VERSION 5.8 ;
BUSBITCHARS "[]" ;
DIVIDERCHAR "/" ;
UNITS
    DATABASE MICRONS 1000 ;
END UNITS

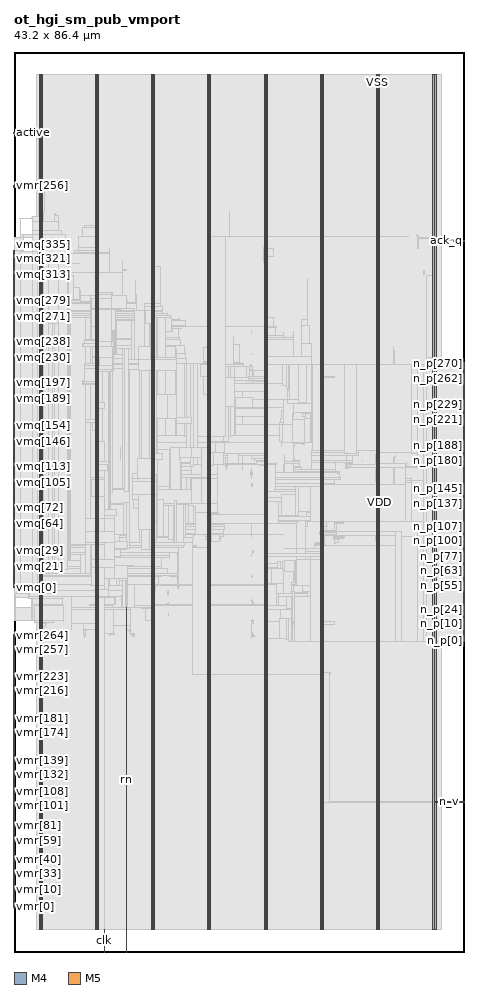
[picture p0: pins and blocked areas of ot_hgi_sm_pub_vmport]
MACRO ot_hgi_sm_pub_vmport
  FOREIGN ot_hgi_sm_pub_vmport 0 0 ;
  CLASS BLOCK ;
  SIZE 43.2 BY 86.4 ;
  PIN ack_q
    DIRECTION OUTPUT ;
    USE SIGNAL ;
    PORT
      LAYER M4 ;
        RECT  43.158 68.256 43.242 68.28 ;
    END
    PORT
      LAYER M4 ;
        RECT  42.145 68.256 43.2 68.28 ;
    END
  END ack_q
  PIN active
    DIRECTION OUTPUT ;
    USE SIGNAL ;
    PORT
      LAYER M4 ;
        RECT  -0.042 78.624 0.042 78.648 ;
    END
    PORT
      LAYER M4 ;
        RECT  0.012 78.624 2.408 78.648 ;
    END
  END active
  PIN clk
    DIRECTION INPUT ;
    USE SIGNAL ;
    PORT
      LAYER M5 ;
        RECT  8.64 -0.042 8.664 0.042 ;
    END
    PORT
      LAYER M5 ;
        RECT  8.64 0.016 8.664 2.137 ;
    END
  END clk
  PIN n_p[0]
    DIRECTION INPUT ;
    USE SIGNAL ;
    PORT
      LAYER M4 ;
        RECT  43.158 29.856 43.242 29.88 ;
    END
  END n_p[0]
  PIN n_p[100]
    DIRECTION INPUT ;
    USE SIGNAL ;
    PORT
      LAYER M4 ;
        RECT  43.158 39.456 43.242 39.48 ;
    END
  END n_p[100]
  PIN n_p[101]
    DIRECTION INPUT ;
    USE SIGNAL ;
    PORT
      LAYER M4 ;
        RECT  43.158 39.552 43.242 39.576 ;
    END
  END n_p[101]
  PIN n_p[102]
    DIRECTION INPUT ;
    USE SIGNAL ;
    PORT
      LAYER M4 ;
        RECT  43.158 39.648 43.242 39.672 ;
    END
  END n_p[102]
  PIN n_p[103]
    DIRECTION INPUT ;
    USE SIGNAL ;
    PORT
      LAYER M4 ;
        RECT  43.158 39.744 43.242 39.768 ;
    END
  END n_p[103]
  PIN n_p[104]
    DIRECTION INPUT ;
    USE SIGNAL ;
    PORT
      LAYER M4 ;
        RECT  43.158 39.84 43.242 39.864 ;
    END
  END n_p[104]
  PIN n_p[105]
    DIRECTION INPUT ;
    USE SIGNAL ;
    PORT
      LAYER M4 ;
        RECT  43.158 39.936 43.242 39.96 ;
    END
  END n_p[105]
  PIN n_p[106]
    DIRECTION INPUT ;
    USE SIGNAL ;
    PORT
      LAYER M4 ;
        RECT  43.158 40.032 43.242 40.056 ;
    END
  END n_p[106]
  PIN n_p[107]
    DIRECTION INPUT ;
    USE SIGNAL ;
    PORT
      LAYER M4 ;
        RECT  43.158 40.128 43.242 40.152 ;
    END
  END n_p[107]
  PIN n_p[108]
    DIRECTION INPUT ;
    USE SIGNAL ;
    PORT
      LAYER M4 ;
        RECT  43.158 40.224 43.242 40.248 ;
    END
  END n_p[108]
  PIN n_p[109]
    DIRECTION INPUT ;
    USE SIGNAL ;
    PORT
      LAYER M4 ;
        RECT  43.158 40.32 43.242 40.344 ;
    END
  END n_p[109]
  PIN n_p[10]
    DIRECTION INPUT ;
    USE SIGNAL ;
    PORT
      LAYER M4 ;
        RECT  43.158 30.816 43.242 30.84 ;
    END
  END n_p[10]
  PIN n_p[110]
    DIRECTION INPUT ;
    USE SIGNAL ;
    PORT
      LAYER M4 ;
        RECT  43.158 40.416 43.242 40.44 ;
    END
  END n_p[110]
  PIN n_p[111]
    DIRECTION INPUT ;
    USE SIGNAL ;
    PORT
      LAYER M4 ;
        RECT  43.158 40.512 43.242 40.536 ;
    END
  END n_p[111]
  PIN n_p[112]
    DIRECTION INPUT ;
    USE SIGNAL ;
    PORT
      LAYER M4 ;
        RECT  43.158 40.608 43.242 40.632 ;
    END
  END n_p[112]
  PIN n_p[113]
    DIRECTION INPUT ;
    USE SIGNAL ;
    PORT
      LAYER M4 ;
        RECT  43.158 40.704 43.242 40.728 ;
    END
  END n_p[113]
  PIN n_p[114]
    DIRECTION INPUT ;
    USE SIGNAL ;
    PORT
      LAYER M4 ;
        RECT  43.158 40.8 43.242 40.824 ;
    END
  END n_p[114]
  PIN n_p[115]
    DIRECTION INPUT ;
    USE SIGNAL ;
    PORT
      LAYER M4 ;
        RECT  43.158 40.896 43.242 40.92 ;
    END
  END n_p[115]
  PIN n_p[116]
    DIRECTION INPUT ;
    USE SIGNAL ;
    PORT
      LAYER M4 ;
        RECT  43.158 40.992 43.242 41.016 ;
    END
  END n_p[116]
  PIN n_p[117]
    DIRECTION INPUT ;
    USE SIGNAL ;
    PORT
      LAYER M4 ;
        RECT  43.158 41.088 43.242 41.112 ;
    END
  END n_p[117]
  PIN n_p[118]
    DIRECTION INPUT ;
    USE SIGNAL ;
    PORT
      LAYER M4 ;
        RECT  43.158 41.184 43.242 41.208 ;
    END
  END n_p[118]
  PIN n_p[119]
    DIRECTION INPUT ;
    USE SIGNAL ;
    PORT
      LAYER M4 ;
        RECT  43.158 41.28 43.242 41.304 ;
    END
  END n_p[119]
  PIN n_p[11]
    DIRECTION INPUT ;
    USE SIGNAL ;
    PORT
      LAYER M4 ;
        RECT  43.158 30.912 43.242 30.936 ;
    END
  END n_p[11]
  PIN n_p[120]
    DIRECTION INPUT ;
    USE SIGNAL ;
    PORT
      LAYER M4 ;
        RECT  43.158 41.376 43.242 41.4 ;
    END
  END n_p[120]
  PIN n_p[121]
    DIRECTION INPUT ;
    USE SIGNAL ;
    PORT
      LAYER M4 ;
        RECT  43.158 41.472 43.242 41.496 ;
    END
  END n_p[121]
  PIN n_p[122]
    DIRECTION INPUT ;
    USE SIGNAL ;
    PORT
      LAYER M4 ;
        RECT  43.158 41.568 43.242 41.592 ;
    END
  END n_p[122]
  PIN n_p[123]
    DIRECTION INPUT ;
    USE SIGNAL ;
    PORT
      LAYER M4 ;
        RECT  43.158 41.664 43.242 41.688 ;
    END
  END n_p[123]
  PIN n_p[124]
    DIRECTION INPUT ;
    USE SIGNAL ;
    PORT
      LAYER M4 ;
        RECT  43.158 41.76 43.242 41.784 ;
    END
  END n_p[124]
  PIN n_p[125]
    DIRECTION INPUT ;
    USE SIGNAL ;
    PORT
      LAYER M4 ;
        RECT  43.158 41.856 43.242 41.88 ;
    END
  END n_p[125]
  PIN n_p[126]
    DIRECTION INPUT ;
    USE SIGNAL ;
    PORT
      LAYER M4 ;
        RECT  43.158 41.952 43.242 41.976 ;
    END
  END n_p[126]
  PIN n_p[127]
    DIRECTION INPUT ;
    USE SIGNAL ;
    PORT
      LAYER M4 ;
        RECT  43.158 42.048 43.242 42.072 ;
    END
  END n_p[127]
  PIN n_p[128]
    DIRECTION INPUT ;
    USE SIGNAL ;
    PORT
      LAYER M4 ;
        RECT  43.158 42.144 43.242 42.168 ;
    END
  END n_p[128]
  PIN n_p[129]
    DIRECTION INPUT ;
    USE SIGNAL ;
    PORT
      LAYER M4 ;
        RECT  43.158 42.24 43.242 42.264 ;
    END
  END n_p[129]
  PIN n_p[12]
    DIRECTION INPUT ;
    USE SIGNAL ;
    PORT
      LAYER M4 ;
        RECT  43.158 31.008 43.242 31.032 ;
    END
  END n_p[12]
  PIN n_p[130]
    DIRECTION INPUT ;
    USE SIGNAL ;
    PORT
      LAYER M4 ;
        RECT  43.158 42.336 43.242 42.36 ;
    END
  END n_p[130]
  PIN n_p[131]
    DIRECTION INPUT ;
    USE SIGNAL ;
    PORT
      LAYER M4 ;
        RECT  43.158 42.432 43.242 42.456 ;
    END
  END n_p[131]
  PIN n_p[132]
    DIRECTION INPUT ;
    USE SIGNAL ;
    PORT
      LAYER M4 ;
        RECT  43.158 42.528 43.242 42.552 ;
    END
  END n_p[132]
  PIN n_p[133]
    DIRECTION INPUT ;
    USE SIGNAL ;
    PORT
      LAYER M4 ;
        RECT  43.158 42.624 43.242 42.648 ;
    END
  END n_p[133]
  PIN n_p[134]
    DIRECTION INPUT ;
    USE SIGNAL ;
    PORT
      LAYER M4 ;
        RECT  43.158 42.72 43.242 42.744 ;
    END
  END n_p[134]
  PIN n_p[135]
    DIRECTION INPUT ;
    USE SIGNAL ;
    PORT
      LAYER M4 ;
        RECT  43.158 42.816 43.242 42.84 ;
    END
  END n_p[135]
  PIN n_p[136]
    DIRECTION INPUT ;
    USE SIGNAL ;
    PORT
      LAYER M4 ;
        RECT  43.158 42.912 43.242 42.936 ;
    END
  END n_p[136]
  PIN n_p[137]
    DIRECTION INPUT ;
    USE SIGNAL ;
    PORT
      LAYER M4 ;
        RECT  43.158 43.008 43.242 43.032 ;
    END
  END n_p[137]
  PIN n_p[138]
    DIRECTION INPUT ;
    USE SIGNAL ;
    PORT
      LAYER M4 ;
        RECT  43.158 43.104 43.242 43.128 ;
    END
  END n_p[138]
  PIN n_p[139]
    DIRECTION INPUT ;
    USE SIGNAL ;
    PORT
      LAYER M4 ;
        RECT  43.158 43.2 43.242 43.224 ;
    END
  END n_p[139]
  PIN n_p[13]
    DIRECTION INPUT ;
    USE SIGNAL ;
    PORT
      LAYER M4 ;
        RECT  43.158 31.104 43.242 31.128 ;
    END
  END n_p[13]
  PIN n_p[140]
    DIRECTION INPUT ;
    USE SIGNAL ;
    PORT
      LAYER M4 ;
        RECT  43.158 43.296 43.242 43.32 ;
    END
  END n_p[140]
  PIN n_p[141]
    DIRECTION INPUT ;
    USE SIGNAL ;
    PORT
      LAYER M4 ;
        RECT  43.158 43.392 43.242 43.416 ;
    END
  END n_p[141]
  PIN n_p[142]
    DIRECTION INPUT ;
    USE SIGNAL ;
    PORT
      LAYER M4 ;
        RECT  43.158 43.488 43.242 43.512 ;
    END
  END n_p[142]
  PIN n_p[143]
    DIRECTION INPUT ;
    USE SIGNAL ;
    PORT
      LAYER M4 ;
        RECT  43.158 43.584 43.242 43.608 ;
    END
  END n_p[143]
  PIN n_p[144]
    DIRECTION INPUT ;
    USE SIGNAL ;
    PORT
      LAYER M4 ;
        RECT  43.158 43.68 43.242 43.704 ;
    END
  END n_p[144]
  PIN n_p[145]
    DIRECTION INPUT ;
    USE SIGNAL ;
    PORT
      LAYER M4 ;
        RECT  43.158 43.776 43.242 43.8 ;
    END
  END n_p[145]
  PIN n_p[146]
    DIRECTION INPUT ;
    USE SIGNAL ;
    PORT
      LAYER M4 ;
        RECT  43.158 43.872 43.242 43.896 ;
    END
  END n_p[146]
  PIN n_p[147]
    DIRECTION INPUT ;
    USE SIGNAL ;
    PORT
      LAYER M4 ;
        RECT  43.158 43.968 43.242 43.992 ;
    END
  END n_p[147]
  PIN n_p[148]
    DIRECTION INPUT ;
    USE SIGNAL ;
    PORT
      LAYER M4 ;
        RECT  43.158 44.064 43.242 44.088 ;
    END
  END n_p[148]
  PIN n_p[149]
    DIRECTION INPUT ;
    USE SIGNAL ;
    PORT
      LAYER M4 ;
        RECT  43.158 44.16 43.242 44.184 ;
    END
  END n_p[149]
  PIN n_p[14]
    DIRECTION INPUT ;
    USE SIGNAL ;
    PORT
      LAYER M4 ;
        RECT  43.158 31.2 43.242 31.224 ;
    END
  END n_p[14]
  PIN n_p[150]
    DIRECTION INPUT ;
    USE SIGNAL ;
    PORT
      LAYER M4 ;
        RECT  43.158 44.256 43.242 44.28 ;
    END
  END n_p[150]
  PIN n_p[151]
    DIRECTION INPUT ;
    USE SIGNAL ;
    PORT
      LAYER M4 ;
        RECT  43.158 44.352 43.242 44.376 ;
    END
  END n_p[151]
  PIN n_p[152]
    DIRECTION INPUT ;
    USE SIGNAL ;
    PORT
      LAYER M4 ;
        RECT  43.158 44.448 43.242 44.472 ;
    END
  END n_p[152]
  PIN n_p[153]
    DIRECTION INPUT ;
    USE SIGNAL ;
    PORT
      LAYER M4 ;
        RECT  43.158 44.544 43.242 44.568 ;
    END
  END n_p[153]
  PIN n_p[154]
    DIRECTION INPUT ;
    USE SIGNAL ;
    PORT
      LAYER M4 ;
        RECT  43.158 44.64 43.242 44.664 ;
    END
  END n_p[154]
  PIN n_p[155]
    DIRECTION INPUT ;
    USE SIGNAL ;
    PORT
      LAYER M4 ;
        RECT  43.158 44.736 43.242 44.76 ;
    END
  END n_p[155]
  PIN n_p[156]
    DIRECTION INPUT ;
    USE SIGNAL ;
    PORT
      LAYER M4 ;
        RECT  43.158 44.832 43.242 44.856 ;
    END
  END n_p[156]
  PIN n_p[157]
    DIRECTION INPUT ;
    USE SIGNAL ;
    PORT
      LAYER M4 ;
        RECT  43.158 44.928 43.242 44.952 ;
    END
  END n_p[157]
  PIN n_p[158]
    DIRECTION INPUT ;
    USE SIGNAL ;
    PORT
      LAYER M4 ;
        RECT  43.158 45.024 43.242 45.048 ;
    END
  END n_p[158]
  PIN n_p[159]
    DIRECTION INPUT ;
    USE SIGNAL ;
    PORT
      LAYER M4 ;
        RECT  43.158 45.12 43.242 45.144 ;
    END
  END n_p[159]
  PIN n_p[15]
    DIRECTION INPUT ;
    USE SIGNAL ;
    PORT
      LAYER M4 ;
        RECT  43.158 31.296 43.242 31.32 ;
    END
  END n_p[15]
  PIN n_p[160]
    DIRECTION INPUT ;
    USE SIGNAL ;
    PORT
      LAYER M4 ;
        RECT  43.158 45.216 43.242 45.24 ;
    END
  END n_p[160]
  PIN n_p[161]
    DIRECTION INPUT ;
    USE SIGNAL ;
    PORT
      LAYER M4 ;
        RECT  43.158 45.312 43.242 45.336 ;
    END
  END n_p[161]
  PIN n_p[162]
    DIRECTION INPUT ;
    USE SIGNAL ;
    PORT
      LAYER M4 ;
        RECT  43.158 45.408 43.242 45.432 ;
    END
  END n_p[162]
  PIN n_p[163]
    DIRECTION INPUT ;
    USE SIGNAL ;
    PORT
      LAYER M4 ;
        RECT  43.158 45.504 43.242 45.528 ;
    END
  END n_p[163]
  PIN n_p[164]
    DIRECTION INPUT ;
    USE SIGNAL ;
    PORT
      LAYER M4 ;
        RECT  43.158 45.6 43.242 45.624 ;
    END
  END n_p[164]
  PIN n_p[165]
    DIRECTION INPUT ;
    USE SIGNAL ;
    PORT
      LAYER M4 ;
        RECT  43.158 45.696 43.242 45.72 ;
    END
  END n_p[165]
  PIN n_p[166]
    DIRECTION INPUT ;
    USE SIGNAL ;
    PORT
      LAYER M4 ;
        RECT  43.158 45.792 43.242 45.816 ;
    END
  END n_p[166]
  PIN n_p[167]
    DIRECTION INPUT ;
    USE SIGNAL ;
    PORT
      LAYER M4 ;
        RECT  43.158 45.888 43.242 45.912 ;
    END
  END n_p[167]
  PIN n_p[168]
    DIRECTION INPUT ;
    USE SIGNAL ;
    PORT
      LAYER M4 ;
        RECT  43.158 45.984 43.242 46.008 ;
    END
  END n_p[168]
  PIN n_p[169]
    DIRECTION INPUT ;
    USE SIGNAL ;
    PORT
      LAYER M4 ;
        RECT  43.158 46.08 43.242 46.104 ;
    END
  END n_p[169]
  PIN n_p[16]
    DIRECTION INPUT ;
    USE SIGNAL ;
    PORT
      LAYER M4 ;
        RECT  43.158 31.392 43.242 31.416 ;
    END
  END n_p[16]
  PIN n_p[170]
    DIRECTION INPUT ;
    USE SIGNAL ;
    PORT
      LAYER M4 ;
        RECT  43.158 46.176 43.242 46.2 ;
    END
  END n_p[170]
  PIN n_p[171]
    DIRECTION INPUT ;
    USE SIGNAL ;
    PORT
      LAYER M4 ;
        RECT  43.158 46.272 43.242 46.296 ;
    END
  END n_p[171]
  PIN n_p[172]
    DIRECTION INPUT ;
    USE SIGNAL ;
    PORT
      LAYER M4 ;
        RECT  43.158 46.368 43.242 46.392 ;
    END
  END n_p[172]
  PIN n_p[173]
    DIRECTION INPUT ;
    USE SIGNAL ;
    PORT
      LAYER M4 ;
        RECT  43.158 46.464 43.242 46.488 ;
    END
  END n_p[173]
  PIN n_p[174]
    DIRECTION INPUT ;
    USE SIGNAL ;
    PORT
      LAYER M4 ;
        RECT  43.158 46.56 43.242 46.584 ;
    END
  END n_p[174]
  PIN n_p[175]
    DIRECTION INPUT ;
    USE SIGNAL ;
    PORT
      LAYER M4 ;
        RECT  43.158 46.656 43.242 46.68 ;
    END
  END n_p[175]
  PIN n_p[176]
    DIRECTION INPUT ;
    USE SIGNAL ;
    PORT
      LAYER M4 ;
        RECT  43.158 46.752 43.242 46.776 ;
    END
  END n_p[176]
  PIN n_p[177]
    DIRECTION INPUT ;
    USE SIGNAL ;
    PORT
      LAYER M4 ;
        RECT  43.158 46.848 43.242 46.872 ;
    END
  END n_p[177]
  PIN n_p[178]
    DIRECTION INPUT ;
    USE SIGNAL ;
    PORT
      LAYER M4 ;
        RECT  43.158 46.944 43.242 46.968 ;
    END
  END n_p[178]
  PIN n_p[179]
    DIRECTION INPUT ;
    USE SIGNAL ;
    PORT
      LAYER M4 ;
        RECT  43.158 47.04 43.242 47.064 ;
    END
  END n_p[179]
  PIN n_p[17]
    DIRECTION INPUT ;
    USE SIGNAL ;
    PORT
      LAYER M4 ;
        RECT  43.158 31.488 43.242 31.512 ;
    END
  END n_p[17]
  PIN n_p[180]
    DIRECTION INPUT ;
    USE SIGNAL ;
    PORT
      LAYER M4 ;
        RECT  43.158 47.136 43.242 47.16 ;
    END
  END n_p[180]
  PIN n_p[181]
    DIRECTION INPUT ;
    USE SIGNAL ;
    PORT
      LAYER M4 ;
        RECT  43.158 47.232 43.242 47.256 ;
    END
  END n_p[181]
  PIN n_p[182]
    DIRECTION INPUT ;
    USE SIGNAL ;
    PORT
      LAYER M4 ;
        RECT  43.158 47.328 43.242 47.352 ;
    END
  END n_p[182]
  PIN n_p[183]
    DIRECTION INPUT ;
    USE SIGNAL ;
    PORT
      LAYER M4 ;
        RECT  43.158 47.424 43.242 47.448 ;
    END
  END n_p[183]
  PIN n_p[184]
    DIRECTION INPUT ;
    USE SIGNAL ;
    PORT
      LAYER M4 ;
        RECT  43.158 47.52 43.242 47.544 ;
    END
  END n_p[184]
  PIN n_p[185]
    DIRECTION INPUT ;
    USE SIGNAL ;
    PORT
      LAYER M4 ;
        RECT  43.158 47.616 43.242 47.64 ;
    END
  END n_p[185]
  PIN n_p[186]
    DIRECTION INPUT ;
    USE SIGNAL ;
    PORT
      LAYER M4 ;
        RECT  43.158 47.712 43.242 47.736 ;
    END
  END n_p[186]
  PIN n_p[187]
    DIRECTION INPUT ;
    USE SIGNAL ;
    PORT
      LAYER M4 ;
        RECT  43.158 47.808 43.242 47.832 ;
    END
  END n_p[187]
  PIN n_p[188]
    DIRECTION INPUT ;
    USE SIGNAL ;
    PORT
      LAYER M4 ;
        RECT  43.158 47.904 43.242 47.928 ;
    END
  END n_p[188]
  PIN n_p[189]
    DIRECTION INPUT ;
    USE SIGNAL ;
    PORT
      LAYER M4 ;
        RECT  43.158 48 43.242 48.024 ;
    END
  END n_p[189]
  PIN n_p[18]
    DIRECTION INPUT ;
    USE SIGNAL ;
    PORT
      LAYER M4 ;
        RECT  43.158 31.584 43.242 31.608 ;
    END
  END n_p[18]
  PIN n_p[190]
    DIRECTION INPUT ;
    USE SIGNAL ;
    PORT
      LAYER M4 ;
        RECT  43.158 48.096 43.242 48.12 ;
    END
  END n_p[190]
  PIN n_p[191]
    DIRECTION INPUT ;
    USE SIGNAL ;
    PORT
      LAYER M4 ;
        RECT  43.158 48.192 43.242 48.216 ;
    END
  END n_p[191]
  PIN n_p[192]
    DIRECTION INPUT ;
    USE SIGNAL ;
    PORT
      LAYER M4 ;
        RECT  43.158 48.288 43.242 48.312 ;
    END
  END n_p[192]
  PIN n_p[193]
    DIRECTION INPUT ;
    USE SIGNAL ;
    PORT
      LAYER M4 ;
        RECT  43.158 48.384 43.242 48.408 ;
    END
  END n_p[193]
  PIN n_p[194]
    DIRECTION INPUT ;
    USE SIGNAL ;
    PORT
      LAYER M4 ;
        RECT  43.158 48.48 43.242 48.504 ;
    END
  END n_p[194]
  PIN n_p[195]
    DIRECTION INPUT ;
    USE SIGNAL ;
    PORT
      LAYER M4 ;
        RECT  43.158 48.576 43.242 48.6 ;
    END
  END n_p[195]
  PIN n_p[196]
    DIRECTION INPUT ;
    USE SIGNAL ;
    PORT
      LAYER M4 ;
        RECT  43.158 48.672 43.242 48.696 ;
    END
  END n_p[196]
  PIN n_p[197]
    DIRECTION INPUT ;
    USE SIGNAL ;
    PORT
      LAYER M4 ;
        RECT  43.158 48.768 43.242 48.792 ;
    END
  END n_p[197]
  PIN n_p[198]
    DIRECTION INPUT ;
    USE SIGNAL ;
    PORT
      LAYER M4 ;
        RECT  43.158 48.864 43.242 48.888 ;
    END
  END n_p[198]
  PIN n_p[199]
    DIRECTION INPUT ;
    USE SIGNAL ;
    PORT
      LAYER M4 ;
        RECT  43.158 48.96 43.242 48.984 ;
    END
  END n_p[199]
  PIN n_p[19]
    DIRECTION INPUT ;
    USE SIGNAL ;
    PORT
      LAYER M4 ;
        RECT  43.158 31.68 43.242 31.704 ;
    END
  END n_p[19]
  PIN n_p[1]
    DIRECTION INPUT ;
    USE SIGNAL ;
    PORT
      LAYER M4 ;
        RECT  43.158 29.952 43.242 29.976 ;
    END
  END n_p[1]
  PIN n_p[200]
    DIRECTION INPUT ;
    USE SIGNAL ;
    PORT
      LAYER M4 ;
        RECT  43.158 49.056 43.242 49.08 ;
    END
  END n_p[200]
  PIN n_p[201]
    DIRECTION INPUT ;
    USE SIGNAL ;
    PORT
      LAYER M4 ;
        RECT  43.158 49.152 43.242 49.176 ;
    END
  END n_p[201]
  PIN n_p[202]
    DIRECTION INPUT ;
    USE SIGNAL ;
    PORT
      LAYER M4 ;
        RECT  43.158 49.248 43.242 49.272 ;
    END
  END n_p[202]
  PIN n_p[203]
    DIRECTION INPUT ;
    USE SIGNAL ;
    PORT
      LAYER M4 ;
        RECT  43.158 49.344 43.242 49.368 ;
    END
  END n_p[203]
  PIN n_p[204]
    DIRECTION INPUT ;
    USE SIGNAL ;
    PORT
      LAYER M4 ;
        RECT  43.158 49.44 43.242 49.464 ;
    END
  END n_p[204]
  PIN n_p[205]
    DIRECTION INPUT ;
    USE SIGNAL ;
    PORT
      LAYER M4 ;
        RECT  43.158 49.536 43.242 49.56 ;
    END
  END n_p[205]
  PIN n_p[206]
    DIRECTION INPUT ;
    USE SIGNAL ;
    PORT
      LAYER M4 ;
        RECT  43.158 49.632 43.242 49.656 ;
    END
  END n_p[206]
  PIN n_p[207]
    DIRECTION INPUT ;
    USE SIGNAL ;
    PORT
      LAYER M4 ;
        RECT  43.158 49.728 43.242 49.752 ;
    END
  END n_p[207]
  PIN n_p[208]
    DIRECTION INPUT ;
    USE SIGNAL ;
    PORT
      LAYER M4 ;
        RECT  43.158 49.824 43.242 49.848 ;
    END
  END n_p[208]
  PIN n_p[209]
    DIRECTION INPUT ;
    USE SIGNAL ;
    PORT
      LAYER M4 ;
        RECT  43.158 49.92 43.242 49.944 ;
    END
  END n_p[209]
  PIN n_p[20]
    DIRECTION INPUT ;
    USE SIGNAL ;
    PORT
      LAYER M4 ;
        RECT  43.158 31.776 43.242 31.8 ;
    END
  END n_p[20]
  PIN n_p[210]
    DIRECTION INPUT ;
    USE SIGNAL ;
    PORT
      LAYER M4 ;
        RECT  43.158 50.016 43.242 50.04 ;
    END
  END n_p[210]
  PIN n_p[211]
    DIRECTION INPUT ;
    USE SIGNAL ;
    PORT
      LAYER M4 ;
        RECT  43.158 50.112 43.242 50.136 ;
    END
  END n_p[211]
  PIN n_p[212]
    DIRECTION INPUT ;
    USE SIGNAL ;
    PORT
      LAYER M4 ;
        RECT  43.158 50.208 43.242 50.232 ;
    END
  END n_p[212]
  PIN n_p[213]
    DIRECTION INPUT ;
    USE SIGNAL ;
    PORT
      LAYER M4 ;
        RECT  43.158 50.304 43.242 50.328 ;
    END
  END n_p[213]
  PIN n_p[214]
    DIRECTION INPUT ;
    USE SIGNAL ;
    PORT
      LAYER M4 ;
        RECT  43.158 50.4 43.242 50.424 ;
    END
  END n_p[214]
  PIN n_p[215]
    DIRECTION INPUT ;
    USE SIGNAL ;
    PORT
      LAYER M4 ;
        RECT  43.158 50.496 43.242 50.52 ;
    END
  END n_p[215]
  PIN n_p[216]
    DIRECTION INPUT ;
    USE SIGNAL ;
    PORT
      LAYER M4 ;
        RECT  43.158 50.592 43.242 50.616 ;
    END
  END n_p[216]
  PIN n_p[217]
    DIRECTION INPUT ;
    USE SIGNAL ;
    PORT
      LAYER M4 ;
        RECT  43.158 50.688 43.242 50.712 ;
    END
  END n_p[217]
  PIN n_p[218]
    DIRECTION INPUT ;
    USE SIGNAL ;
    PORT
      LAYER M4 ;
        RECT  43.158 50.784 43.242 50.808 ;
    END
  END n_p[218]
  PIN n_p[219]
    DIRECTION INPUT ;
    USE SIGNAL ;
    PORT
      LAYER M4 ;
        RECT  43.158 50.88 43.242 50.904 ;
    END
  END n_p[219]
  PIN n_p[21]
    DIRECTION INPUT ;
    USE SIGNAL ;
    PORT
      LAYER M4 ;
        RECT  43.158 31.872 43.242 31.896 ;
    END
  END n_p[21]
  PIN n_p[220]
    DIRECTION INPUT ;
    USE SIGNAL ;
    PORT
      LAYER M4 ;
        RECT  43.158 50.976 43.242 51 ;
    END
  END n_p[220]
  PIN n_p[221]
    DIRECTION INPUT ;
    USE SIGNAL ;
    PORT
      LAYER M4 ;
        RECT  43.158 51.072 43.242 51.096 ;
    END
  END n_p[221]
  PIN n_p[222]
    DIRECTION INPUT ;
    USE SIGNAL ;
    PORT
      LAYER M4 ;
        RECT  43.158 51.168 43.242 51.192 ;
    END
  END n_p[222]
  PIN n_p[223]
    DIRECTION INPUT ;
    USE SIGNAL ;
    PORT
      LAYER M4 ;
        RECT  43.158 51.264 43.242 51.288 ;
    END
  END n_p[223]
  PIN n_p[224]
    DIRECTION INPUT ;
    USE SIGNAL ;
    PORT
      LAYER M4 ;
        RECT  43.158 51.36 43.242 51.384 ;
    END
  END n_p[224]
  PIN n_p[225]
    DIRECTION INPUT ;
    USE SIGNAL ;
    PORT
      LAYER M4 ;
        RECT  43.158 51.456 43.242 51.48 ;
    END
  END n_p[225]
  PIN n_p[226]
    DIRECTION INPUT ;
    USE SIGNAL ;
    PORT
      LAYER M4 ;
        RECT  43.158 51.552 43.242 51.576 ;
    END
  END n_p[226]
  PIN n_p[227]
    DIRECTION INPUT ;
    USE SIGNAL ;
    PORT
      LAYER M4 ;
        RECT  43.158 51.648 43.242 51.672 ;
    END
  END n_p[227]
  PIN n_p[228]
    DIRECTION INPUT ;
    USE SIGNAL ;
    PORT
      LAYER M4 ;
        RECT  43.158 51.744 43.242 51.768 ;
    END
  END n_p[228]
  PIN n_p[229]
    DIRECTION INPUT ;
    USE SIGNAL ;
    PORT
      LAYER M4 ;
        RECT  43.158 51.84 43.242 51.864 ;
    END
  END n_p[229]
  PIN n_p[22]
    DIRECTION INPUT ;
    USE SIGNAL ;
    PORT
      LAYER M4 ;
        RECT  43.158 31.968 43.242 31.992 ;
    END
  END n_p[22]
  PIN n_p[230]
    DIRECTION INPUT ;
    USE SIGNAL ;
    PORT
      LAYER M4 ;
        RECT  43.158 51.936 43.242 51.96 ;
    END
  END n_p[230]
  PIN n_p[231]
    DIRECTION INPUT ;
    USE SIGNAL ;
    PORT
      LAYER M4 ;
        RECT  43.158 52.032 43.242 52.056 ;
    END
  END n_p[231]
  PIN n_p[232]
    DIRECTION INPUT ;
    USE SIGNAL ;
    PORT
      LAYER M4 ;
        RECT  43.158 52.128 43.242 52.152 ;
    END
  END n_p[232]
  PIN n_p[233]
    DIRECTION INPUT ;
    USE SIGNAL ;
    PORT
      LAYER M4 ;
        RECT  43.158 52.224 43.242 52.248 ;
    END
  END n_p[233]
  PIN n_p[234]
    DIRECTION INPUT ;
    USE SIGNAL ;
    PORT
      LAYER M4 ;
        RECT  43.158 52.32 43.242 52.344 ;
    END
  END n_p[234]
  PIN n_p[235]
    DIRECTION INPUT ;
    USE SIGNAL ;
    PORT
      LAYER M4 ;
        RECT  43.158 52.416 43.242 52.44 ;
    END
  END n_p[235]
  PIN n_p[236]
    DIRECTION INPUT ;
    USE SIGNAL ;
    PORT
      LAYER M4 ;
        RECT  43.158 52.512 43.242 52.536 ;
    END
  END n_p[236]
  PIN n_p[237]
    DIRECTION INPUT ;
    USE SIGNAL ;
    PORT
      LAYER M4 ;
        RECT  43.158 52.608 43.242 52.632 ;
    END
  END n_p[237]
  PIN n_p[238]
    DIRECTION INPUT ;
    USE SIGNAL ;
    PORT
      LAYER M4 ;
        RECT  43.158 52.704 43.242 52.728 ;
    END
  END n_p[238]
  PIN n_p[239]
    DIRECTION INPUT ;
    USE SIGNAL ;
    PORT
      LAYER M4 ;
        RECT  43.158 52.8 43.242 52.824 ;
    END
  END n_p[239]
  PIN n_p[23]
    DIRECTION INPUT ;
    USE SIGNAL ;
    PORT
      LAYER M4 ;
        RECT  43.158 32.064 43.242 32.088 ;
    END
  END n_p[23]
  PIN n_p[240]
    DIRECTION INPUT ;
    USE SIGNAL ;
    PORT
      LAYER M4 ;
        RECT  43.158 52.896 43.242 52.92 ;
    END
  END n_p[240]
  PIN n_p[241]
    DIRECTION INPUT ;
    USE SIGNAL ;
    PORT
      LAYER M4 ;
        RECT  43.158 52.992 43.242 53.016 ;
    END
  END n_p[241]
  PIN n_p[242]
    DIRECTION INPUT ;
    USE SIGNAL ;
    PORT
      LAYER M4 ;
        RECT  43.158 53.088 43.242 53.112 ;
    END
  END n_p[242]
  PIN n_p[243]
    DIRECTION INPUT ;
    USE SIGNAL ;
    PORT
      LAYER M4 ;
        RECT  43.158 53.184 43.242 53.208 ;
    END
  END n_p[243]
  PIN n_p[244]
    DIRECTION INPUT ;
    USE SIGNAL ;
    PORT
      LAYER M4 ;
        RECT  43.158 53.28 43.242 53.304 ;
    END
  END n_p[244]
  PIN n_p[245]
    DIRECTION INPUT ;
    USE SIGNAL ;
    PORT
      LAYER M4 ;
        RECT  43.158 53.376 43.242 53.4 ;
    END
  END n_p[245]
  PIN n_p[246]
    DIRECTION INPUT ;
    USE SIGNAL ;
    PORT
      LAYER M4 ;
        RECT  43.158 53.472 43.242 53.496 ;
    END
  END n_p[246]
  PIN n_p[247]
    DIRECTION INPUT ;
    USE SIGNAL ;
    PORT
      LAYER M4 ;
        RECT  43.158 53.568 43.242 53.592 ;
    END
  END n_p[247]
  PIN n_p[248]
    DIRECTION INPUT ;
    USE SIGNAL ;
    PORT
      LAYER M4 ;
        RECT  43.158 53.664 43.242 53.688 ;
    END
  END n_p[248]
  PIN n_p[249]
    DIRECTION INPUT ;
    USE SIGNAL ;
    PORT
      LAYER M4 ;
        RECT  43.158 53.76 43.242 53.784 ;
    END
  END n_p[249]
  PIN n_p[24]
    DIRECTION INPUT ;
    USE SIGNAL ;
    PORT
      LAYER M4 ;
        RECT  43.158 32.16 43.242 32.184 ;
    END
  END n_p[24]
  PIN n_p[250]
    DIRECTION INPUT ;
    USE SIGNAL ;
    PORT
      LAYER M4 ;
        RECT  43.158 53.856 43.242 53.88 ;
    END
  END n_p[250]
  PIN n_p[251]
    DIRECTION INPUT ;
    USE SIGNAL ;
    PORT
      LAYER M4 ;
        RECT  43.158 53.952 43.242 53.976 ;
    END
  END n_p[251]
  PIN n_p[252]
    DIRECTION INPUT ;
    USE SIGNAL ;
    PORT
      LAYER M4 ;
        RECT  43.158 54.048 43.242 54.072 ;
    END
  END n_p[252]
  PIN n_p[253]
    DIRECTION INPUT ;
    USE SIGNAL ;
    PORT
      LAYER M4 ;
        RECT  43.158 54.144 43.242 54.168 ;
    END
  END n_p[253]
  PIN n_p[254]
    DIRECTION INPUT ;
    USE SIGNAL ;
    PORT
      LAYER M4 ;
        RECT  43.158 54.24 43.242 54.264 ;
    END
  END n_p[254]
  PIN n_p[255]
    DIRECTION INPUT ;
    USE SIGNAL ;
    PORT
      LAYER M4 ;
        RECT  43.158 54.336 43.242 54.36 ;
    END
  END n_p[255]
  PIN n_p[256]
    DIRECTION INPUT ;
    USE SIGNAL ;
    PORT
      LAYER M4 ;
        RECT  43.158 54.432 43.242 54.456 ;
    END
  END n_p[256]
  PIN n_p[257]
    DIRECTION INPUT ;
    USE SIGNAL ;
    PORT
      LAYER M4 ;
        RECT  43.158 54.528 43.242 54.552 ;
    END
  END n_p[257]
  PIN n_p[258]
    DIRECTION INPUT ;
    USE SIGNAL ;
    PORT
      LAYER M4 ;
        RECT  43.158 54.624 43.242 54.648 ;
    END
  END n_p[258]
  PIN n_p[259]
    DIRECTION INPUT ;
    USE SIGNAL ;
    PORT
      LAYER M4 ;
        RECT  43.158 54.72 43.242 54.744 ;
    END
  END n_p[259]
  PIN n_p[25]
    DIRECTION INPUT ;
    USE SIGNAL ;
    PORT
      LAYER M4 ;
        RECT  43.158 32.256 43.242 32.28 ;
    END
  END n_p[25]
  PIN n_p[260]
    DIRECTION INPUT ;
    USE SIGNAL ;
    PORT
      LAYER M4 ;
        RECT  43.158 54.816 43.242 54.84 ;
    END
  END n_p[260]
  PIN n_p[261]
    DIRECTION INPUT ;
    USE SIGNAL ;
    PORT
      LAYER M4 ;
        RECT  43.158 54.912 43.242 54.936 ;
    END
  END n_p[261]
  PIN n_p[262]
    DIRECTION INPUT ;
    USE SIGNAL ;
    PORT
      LAYER M4 ;
        RECT  43.158 55.008 43.242 55.032 ;
    END
  END n_p[262]
  PIN n_p[263]
    DIRECTION INPUT ;
    USE SIGNAL ;
    PORT
      LAYER M4 ;
        RECT  43.158 55.104 43.242 55.128 ;
    END
  END n_p[263]
  PIN n_p[264]
    DIRECTION INPUT ;
    USE SIGNAL ;
    PORT
      LAYER M4 ;
        RECT  43.158 55.2 43.242 55.224 ;
    END
  END n_p[264]
  PIN n_p[265]
    DIRECTION INPUT ;
    USE SIGNAL ;
    PORT
      LAYER M4 ;
        RECT  43.158 55.296 43.242 55.32 ;
    END
  END n_p[265]
  PIN n_p[266]
    DIRECTION INPUT ;
    USE SIGNAL ;
    PORT
      LAYER M4 ;
        RECT  43.158 55.392 43.242 55.416 ;
    END
  END n_p[266]
  PIN n_p[267]
    DIRECTION INPUT ;
    USE SIGNAL ;
    PORT
      LAYER M4 ;
        RECT  43.158 55.488 43.242 55.512 ;
    END
  END n_p[267]
  PIN n_p[268]
    DIRECTION INPUT ;
    USE SIGNAL ;
    PORT
      LAYER M4 ;
        RECT  43.158 55.584 43.242 55.608 ;
    END
  END n_p[268]
  PIN n_p[269]
    DIRECTION INPUT ;
    USE SIGNAL ;
    PORT
      LAYER M4 ;
        RECT  43.158 55.68 43.242 55.704 ;
    END
  END n_p[269]
  PIN n_p[26]
    DIRECTION INPUT ;
    USE SIGNAL ;
    PORT
      LAYER M4 ;
        RECT  43.158 32.352 43.242 32.376 ;
    END
  END n_p[26]
  PIN n_p[270]
    DIRECTION INPUT ;
    USE SIGNAL ;
    PORT
      LAYER M4 ;
        RECT  43.158 55.776 43.242 55.8 ;
    END
  END n_p[270]
  PIN n_p[271]
    DIRECTION INPUT ;
    USE SIGNAL ;
    PORT
      LAYER M4 ;
        RECT  43.158 55.872 43.242 55.896 ;
    END
  END n_p[271]
  PIN n_p[272]
    DIRECTION INPUT ;
    USE SIGNAL ;
    PORT
      LAYER M4 ;
        RECT  43.158 55.968 43.242 55.992 ;
    END
  END n_p[272]
  PIN n_p[273]
    DIRECTION INPUT ;
    USE SIGNAL ;
    PORT
      LAYER M4 ;
        RECT  43.158 56.064 43.242 56.088 ;
    END
  END n_p[273]
  PIN n_p[274]
    DIRECTION INPUT ;
    USE SIGNAL ;
    PORT
      LAYER M4 ;
        RECT  43.158 56.16 43.242 56.184 ;
    END
  END n_p[274]
  PIN n_p[275]
    DIRECTION INPUT ;
    USE SIGNAL ;
    PORT
      LAYER M4 ;
        RECT  43.158 56.256 43.242 56.28 ;
    END
  END n_p[275]
  PIN n_p[276]
    DIRECTION INPUT ;
    USE SIGNAL ;
    PORT
      LAYER M4 ;
        RECT  43.158 56.352 43.242 56.376 ;
    END
  END n_p[276]
  PIN n_p[277]
    DIRECTION INPUT ;
    USE SIGNAL ;
    PORT
      LAYER M4 ;
        RECT  43.158 56.448 43.242 56.472 ;
    END
  END n_p[277]
  PIN n_p[278]
    DIRECTION INPUT ;
    USE SIGNAL ;
    PORT
      LAYER M4 ;
        RECT  43.158 56.544 43.242 56.568 ;
    END
  END n_p[278]
  PIN n_p[27]
    DIRECTION INPUT ;
    USE SIGNAL ;
    PORT
      LAYER M4 ;
        RECT  43.158 32.448 43.242 32.472 ;
    END
  END n_p[27]
  PIN n_p[28]
    DIRECTION INPUT ;
    USE SIGNAL ;
    PORT
      LAYER M4 ;
        RECT  43.158 32.544 43.242 32.568 ;
    END
  END n_p[28]
  PIN n_p[29]
    DIRECTION INPUT ;
    USE SIGNAL ;
    PORT
      LAYER M4 ;
        RECT  43.158 32.64 43.242 32.664 ;
    END
  END n_p[29]
  PIN n_p[2]
    DIRECTION INPUT ;
    USE SIGNAL ;
    PORT
      LAYER M4 ;
        RECT  43.158 30.048 43.242 30.072 ;
    END
  END n_p[2]
  PIN n_p[30]
    DIRECTION INPUT ;
    USE SIGNAL ;
    PORT
      LAYER M4 ;
        RECT  43.158 32.736 43.242 32.76 ;
    END
  END n_p[30]
  PIN n_p[31]
    DIRECTION INPUT ;
    USE SIGNAL ;
    PORT
      LAYER M4 ;
        RECT  43.158 32.832 43.242 32.856 ;
    END
  END n_p[31]
  PIN n_p[32]
    DIRECTION INPUT ;
    USE SIGNAL ;
    PORT
      LAYER M4 ;
        RECT  43.158 32.928 43.242 32.952 ;
    END
  END n_p[32]
  PIN n_p[33]
    DIRECTION INPUT ;
    USE SIGNAL ;
    PORT
      LAYER M4 ;
        RECT  43.158 33.024 43.242 33.048 ;
    END
  END n_p[33]
  PIN n_p[34]
    DIRECTION INPUT ;
    USE SIGNAL ;
    PORT
      LAYER M4 ;
        RECT  43.158 33.12 43.242 33.144 ;
    END
  END n_p[34]
  PIN n_p[35]
    DIRECTION INPUT ;
    USE SIGNAL ;
    PORT
      LAYER M4 ;
        RECT  43.158 33.216 43.242 33.24 ;
    END
  END n_p[35]
  PIN n_p[36]
    DIRECTION INPUT ;
    USE SIGNAL ;
    PORT
      LAYER M4 ;
        RECT  43.158 33.312 43.242 33.336 ;
    END
  END n_p[36]
  PIN n_p[37]
    DIRECTION INPUT ;
    USE SIGNAL ;
    PORT
      LAYER M4 ;
        RECT  43.158 33.408 43.242 33.432 ;
    END
  END n_p[37]
  PIN n_p[38]
    DIRECTION INPUT ;
    USE SIGNAL ;
    PORT
      LAYER M4 ;
        RECT  43.158 33.504 43.242 33.528 ;
    END
  END n_p[38]
  PIN n_p[39]
    DIRECTION INPUT ;
    USE SIGNAL ;
    PORT
      LAYER M4 ;
        RECT  43.158 33.6 43.242 33.624 ;
    END
  END n_p[39]
  PIN n_p[3]
    DIRECTION INPUT ;
    USE SIGNAL ;
    PORT
      LAYER M4 ;
        RECT  43.158 30.144 43.242 30.168 ;
    END
  END n_p[3]
  PIN n_p[40]
    DIRECTION INPUT ;
    USE SIGNAL ;
    PORT
      LAYER M4 ;
        RECT  43.158 33.696 43.242 33.72 ;
    END
  END n_p[40]
  PIN n_p[41]
    DIRECTION INPUT ;
    USE SIGNAL ;
    PORT
      LAYER M4 ;
        RECT  43.158 33.792 43.242 33.816 ;
    END
  END n_p[41]
  PIN n_p[42]
    DIRECTION INPUT ;
    USE SIGNAL ;
    PORT
      LAYER M4 ;
        RECT  43.158 33.888 43.242 33.912 ;
    END
  END n_p[42]
  PIN n_p[43]
    DIRECTION INPUT ;
    USE SIGNAL ;
    PORT
      LAYER M4 ;
        RECT  43.158 33.984 43.242 34.008 ;
    END
  END n_p[43]
  PIN n_p[44]
    DIRECTION INPUT ;
    USE SIGNAL ;
    PORT
      LAYER M4 ;
        RECT  43.158 34.08 43.242 34.104 ;
    END
  END n_p[44]
  PIN n_p[45]
    DIRECTION INPUT ;
    USE SIGNAL ;
    PORT
      LAYER M4 ;
        RECT  43.158 34.176 43.242 34.2 ;
    END
  END n_p[45]
  PIN n_p[46]
    DIRECTION INPUT ;
    USE SIGNAL ;
    PORT
      LAYER M4 ;
        RECT  43.158 34.272 43.242 34.296 ;
    END
  END n_p[46]
  PIN n_p[47]
    DIRECTION INPUT ;
    USE SIGNAL ;
    PORT
      LAYER M4 ;
        RECT  43.158 34.368 43.242 34.392 ;
    END
  END n_p[47]
  PIN n_p[48]
    DIRECTION INPUT ;
    USE SIGNAL ;
    PORT
      LAYER M4 ;
        RECT  43.158 34.464 43.242 34.488 ;
    END
  END n_p[48]
  PIN n_p[49]
    DIRECTION INPUT ;
    USE SIGNAL ;
    PORT
      LAYER M4 ;
        RECT  43.158 34.56 43.242 34.584 ;
    END
  END n_p[49]
  PIN n_p[4]
    DIRECTION INPUT ;
    USE SIGNAL ;
    PORT
      LAYER M4 ;
        RECT  43.158 30.24 43.242 30.264 ;
    END
  END n_p[4]
  PIN n_p[50]
    DIRECTION INPUT ;
    USE SIGNAL ;
    PORT
      LAYER M4 ;
        RECT  43.158 34.656 43.242 34.68 ;
    END
  END n_p[50]
  PIN n_p[51]
    DIRECTION INPUT ;
    USE SIGNAL ;
    PORT
      LAYER M4 ;
        RECT  43.158 34.752 43.242 34.776 ;
    END
  END n_p[51]
  PIN n_p[52]
    DIRECTION INPUT ;
    USE SIGNAL ;
    PORT
      LAYER M4 ;
        RECT  43.158 34.848 43.242 34.872 ;
    END
  END n_p[52]
  PIN n_p[53]
    DIRECTION INPUT ;
    USE SIGNAL ;
    PORT
      LAYER M4 ;
        RECT  43.158 34.944 43.242 34.968 ;
    END
  END n_p[53]
  PIN n_p[54]
    DIRECTION INPUT ;
    USE SIGNAL ;
    PORT
      LAYER M4 ;
        RECT  43.158 35.04 43.242 35.064 ;
    END
  END n_p[54]
  PIN n_p[55]
    DIRECTION INPUT ;
    USE SIGNAL ;
    PORT
      LAYER M4 ;
        RECT  43.158 35.136 43.242 35.16 ;
    END
  END n_p[55]
  PIN n_p[56]
    DIRECTION INPUT ;
    USE SIGNAL ;
    PORT
      LAYER M4 ;
        RECT  43.158 35.232 43.242 35.256 ;
    END
  END n_p[56]
  PIN n_p[57]
    DIRECTION INPUT ;
    USE SIGNAL ;
    PORT
      LAYER M4 ;
        RECT  43.158 35.328 43.242 35.352 ;
    END
  END n_p[57]
  PIN n_p[58]
    DIRECTION INPUT ;
    USE SIGNAL ;
    PORT
      LAYER M4 ;
        RECT  43.158 35.424 43.242 35.448 ;
    END
  END n_p[58]
  PIN n_p[59]
    DIRECTION INPUT ;
    USE SIGNAL ;
    PORT
      LAYER M4 ;
        RECT  43.158 35.52 43.242 35.544 ;
    END
  END n_p[59]
  PIN n_p[5]
    DIRECTION INPUT ;
    USE SIGNAL ;
    PORT
      LAYER M4 ;
        RECT  43.158 30.336 43.242 30.36 ;
    END
  END n_p[5]
  PIN n_p[60]
    DIRECTION INPUT ;
    USE SIGNAL ;
    PORT
      LAYER M4 ;
        RECT  43.158 35.616 43.242 35.64 ;
    END
  END n_p[60]
  PIN n_p[61]
    DIRECTION INPUT ;
    USE SIGNAL ;
    PORT
      LAYER M4 ;
        RECT  43.158 35.712 43.242 35.736 ;
    END
  END n_p[61]
  PIN n_p[62]
    DIRECTION INPUT ;
    USE SIGNAL ;
    PORT
      LAYER M4 ;
        RECT  43.158 35.808 43.242 35.832 ;
    END
  END n_p[62]
  PIN n_p[63]
    DIRECTION INPUT ;
    USE SIGNAL ;
    PORT
      LAYER M4 ;
        RECT  43.158 35.904 43.242 35.928 ;
    END
  END n_p[63]
  PIN n_p[64]
    DIRECTION INPUT ;
    USE SIGNAL ;
    PORT
      LAYER M4 ;
        RECT  43.158 36 43.242 36.024 ;
    END
  END n_p[64]
  PIN n_p[65]
    DIRECTION INPUT ;
    USE SIGNAL ;
    PORT
      LAYER M4 ;
        RECT  43.158 36.096 43.242 36.12 ;
    END
  END n_p[65]
  PIN n_p[66]
    DIRECTION INPUT ;
    USE SIGNAL ;
    PORT
      LAYER M4 ;
        RECT  43.158 36.192 43.242 36.216 ;
    END
  END n_p[66]
  PIN n_p[67]
    DIRECTION INPUT ;
    USE SIGNAL ;
    PORT
      LAYER M4 ;
        RECT  43.158 36.288 43.242 36.312 ;
    END
  END n_p[67]
  PIN n_p[68]
    DIRECTION INPUT ;
    USE SIGNAL ;
    PORT
      LAYER M4 ;
        RECT  43.158 36.384 43.242 36.408 ;
    END
  END n_p[68]
  PIN n_p[69]
    DIRECTION INPUT ;
    USE SIGNAL ;
    PORT
      LAYER M4 ;
        RECT  43.158 36.48 43.242 36.504 ;
    END
  END n_p[69]
  PIN n_p[6]
    DIRECTION INPUT ;
    USE SIGNAL ;
    PORT
      LAYER M4 ;
        RECT  43.158 30.432 43.242 30.456 ;
    END
  END n_p[6]
  PIN n_p[70]
    DIRECTION INPUT ;
    USE SIGNAL ;
    PORT
      LAYER M4 ;
        RECT  43.158 36.576 43.242 36.6 ;
    END
  END n_p[70]
  PIN n_p[71]
    DIRECTION INPUT ;
    USE SIGNAL ;
    PORT
      LAYER M4 ;
        RECT  43.158 36.672 43.242 36.696 ;
    END
  END n_p[71]
  PIN n_p[72]
    DIRECTION INPUT ;
    USE SIGNAL ;
    PORT
      LAYER M4 ;
        RECT  43.158 36.768 43.242 36.792 ;
    END
  END n_p[72]
  PIN n_p[73]
    DIRECTION INPUT ;
    USE SIGNAL ;
    PORT
      LAYER M4 ;
        RECT  43.158 36.864 43.242 36.888 ;
    END
  END n_p[73]
  PIN n_p[74]
    DIRECTION INPUT ;
    USE SIGNAL ;
    PORT
      LAYER M4 ;
        RECT  43.158 36.96 43.242 36.984 ;
    END
  END n_p[74]
  PIN n_p[75]
    DIRECTION INPUT ;
    USE SIGNAL ;
    PORT
      LAYER M4 ;
        RECT  43.158 37.056 43.242 37.08 ;
    END
  END n_p[75]
  PIN n_p[76]
    DIRECTION INPUT ;
    USE SIGNAL ;
    PORT
      LAYER M4 ;
        RECT  43.158 37.152 43.242 37.176 ;
    END
  END n_p[76]
  PIN n_p[77]
    DIRECTION INPUT ;
    USE SIGNAL ;
    PORT
      LAYER M4 ;
        RECT  43.158 37.248 43.242 37.272 ;
    END
  END n_p[77]
  PIN n_p[78]
    DIRECTION INPUT ;
    USE SIGNAL ;
    PORT
      LAYER M4 ;
        RECT  43.158 37.344 43.242 37.368 ;
    END
  END n_p[78]
  PIN n_p[79]
    DIRECTION INPUT ;
    USE SIGNAL ;
    PORT
      LAYER M4 ;
        RECT  43.158 37.44 43.242 37.464 ;
    END
  END n_p[79]
  PIN n_p[7]
    DIRECTION INPUT ;
    USE SIGNAL ;
    PORT
      LAYER M4 ;
        RECT  43.158 30.528 43.242 30.552 ;
    END
  END n_p[7]
  PIN n_p[80]
    DIRECTION INPUT ;
    USE SIGNAL ;
    PORT
      LAYER M4 ;
        RECT  43.158 37.536 43.242 37.56 ;
    END
  END n_p[80]
  PIN n_p[81]
    DIRECTION INPUT ;
    USE SIGNAL ;
    PORT
      LAYER M4 ;
        RECT  43.158 37.632 43.242 37.656 ;
    END
  END n_p[81]
  PIN n_p[82]
    DIRECTION INPUT ;
    USE SIGNAL ;
    PORT
      LAYER M4 ;
        RECT  43.158 37.728 43.242 37.752 ;
    END
  END n_p[82]
  PIN n_p[83]
    DIRECTION INPUT ;
    USE SIGNAL ;
    PORT
      LAYER M4 ;
        RECT  43.158 37.824 43.242 37.848 ;
    END
  END n_p[83]
  PIN n_p[84]
    DIRECTION INPUT ;
    USE SIGNAL ;
    PORT
      LAYER M4 ;
        RECT  43.158 37.92 43.242 37.944 ;
    END
  END n_p[84]
  PIN n_p[85]
    DIRECTION INPUT ;
    USE SIGNAL ;
    PORT
      LAYER M4 ;
        RECT  43.158 38.016 43.242 38.04 ;
    END
  END n_p[85]
  PIN n_p[86]
    DIRECTION INPUT ;
    USE SIGNAL ;
    PORT
      LAYER M4 ;
        RECT  43.158 38.112 43.242 38.136 ;
    END
  END n_p[86]
  PIN n_p[87]
    DIRECTION INPUT ;
    USE SIGNAL ;
    PORT
      LAYER M4 ;
        RECT  43.158 38.208 43.242 38.232 ;
    END
  END n_p[87]
  PIN n_p[88]
    DIRECTION INPUT ;
    USE SIGNAL ;
    PORT
      LAYER M4 ;
        RECT  43.158 38.304 43.242 38.328 ;
    END
  END n_p[88]
  PIN n_p[89]
    DIRECTION INPUT ;
    USE SIGNAL ;
    PORT
      LAYER M4 ;
        RECT  43.158 38.4 43.242 38.424 ;
    END
  END n_p[89]
  PIN n_p[8]
    DIRECTION INPUT ;
    USE SIGNAL ;
    PORT
      LAYER M4 ;
        RECT  43.158 30.624 43.242 30.648 ;
    END
  END n_p[8]
  PIN n_p[90]
    DIRECTION INPUT ;
    USE SIGNAL ;
    PORT
      LAYER M4 ;
        RECT  43.158 38.496 43.242 38.52 ;
    END
  END n_p[90]
  PIN n_p[91]
    DIRECTION INPUT ;
    USE SIGNAL ;
    PORT
      LAYER M4 ;
        RECT  43.158 38.592 43.242 38.616 ;
    END
  END n_p[91]
  PIN n_p[92]
    DIRECTION INPUT ;
    USE SIGNAL ;
    PORT
      LAYER M4 ;
        RECT  43.158 38.688 43.242 38.712 ;
    END
  END n_p[92]
  PIN n_p[93]
    DIRECTION INPUT ;
    USE SIGNAL ;
    PORT
      LAYER M4 ;
        RECT  43.158 38.784 43.242 38.808 ;
    END
  END n_p[93]
  PIN n_p[94]
    DIRECTION INPUT ;
    USE SIGNAL ;
    PORT
      LAYER M4 ;
        RECT  43.158 38.88 43.242 38.904 ;
    END
  END n_p[94]
  PIN n_p[95]
    DIRECTION INPUT ;
    USE SIGNAL ;
    PORT
      LAYER M4 ;
        RECT  43.158 38.976 43.242 39 ;
    END
  END n_p[95]
  PIN n_p[96]
    DIRECTION INPUT ;
    USE SIGNAL ;
    PORT
      LAYER M4 ;
        RECT  43.158 39.072 43.242 39.096 ;
    END
  END n_p[96]
  PIN n_p[97]
    DIRECTION INPUT ;
    USE SIGNAL ;
    PORT
      LAYER M4 ;
        RECT  43.158 39.168 43.242 39.192 ;
    END
  END n_p[97]
  PIN n_p[98]
    DIRECTION INPUT ;
    USE SIGNAL ;
    PORT
      LAYER M4 ;
        RECT  43.158 39.264 43.242 39.288 ;
    END
  END n_p[98]
  PIN n_p[99]
    DIRECTION INPUT ;
    USE SIGNAL ;
    PORT
      LAYER M4 ;
        RECT  43.158 39.36 43.242 39.384 ;
    END
  END n_p[99]
  PIN n_p[9]
    DIRECTION INPUT ;
    USE SIGNAL ;
    PORT
      LAYER M4 ;
        RECT  43.158 30.72 43.242 30.744 ;
    END
  END n_p[9]
  PIN n_v
    DIRECTION INPUT ;
    USE SIGNAL ;
    PORT
      LAYER M4 ;
        RECT  43.158 14.4 43.242 14.424 ;
    END
    PORT
      LAYER M4 ;
        RECT  40.504 14.4 43.2 14.424 ;
    END
  END n_v
  PIN rn
    DIRECTION INPUT ;
    USE SIGNAL ;
    PORT
      LAYER M5 ;
        RECT  10.8 -0.042 10.824 0.042 ;
    END
    PORT
      LAYER M5 ;
        RECT  10.8 0.016 10.824 33.107 ;
    END
  END rn
  PIN vmq[0]
    DIRECTION OUTPUT ;
    USE SIGNAL ;
    PORT
      LAYER M4 ;
        RECT  -0.042 34.992 0.042 35.016 ;
    END
  END vmq[0]
  PIN vmq[100]
    DIRECTION OUTPUT ;
    USE SIGNAL ;
    PORT
      LAYER M4 ;
        RECT  -0.042 44.592 0.042 44.616 ;
    END
  END vmq[100]
  PIN vmq[101]
    DIRECTION OUTPUT ;
    USE SIGNAL ;
    PORT
      LAYER M4 ;
        RECT  -0.042 44.688 0.042 44.712 ;
    END
  END vmq[101]
  PIN vmq[102]
    DIRECTION OUTPUT ;
    USE SIGNAL ;
    PORT
      LAYER M4 ;
        RECT  -0.042 44.784 0.042 44.808 ;
    END
  END vmq[102]
  PIN vmq[103]
    DIRECTION OUTPUT ;
    USE SIGNAL ;
    PORT
      LAYER M4 ;
        RECT  -0.042 44.88 0.042 44.904 ;
    END
  END vmq[103]
  PIN vmq[104]
    DIRECTION OUTPUT ;
    USE SIGNAL ;
    PORT
      LAYER M4 ;
        RECT  -0.042 44.976 0.042 45 ;
    END
  END vmq[104]
  PIN vmq[105]
    DIRECTION OUTPUT ;
    USE SIGNAL ;
    PORT
      LAYER M4 ;
        RECT  -0.042 45.072 0.042 45.096 ;
    END
  END vmq[105]
  PIN vmq[106]
    DIRECTION OUTPUT ;
    USE SIGNAL ;
    PORT
      LAYER M4 ;
        RECT  -0.042 45.168 0.042 45.192 ;
    END
  END vmq[106]
  PIN vmq[107]
    DIRECTION OUTPUT ;
    USE SIGNAL ;
    PORT
      LAYER M4 ;
        RECT  -0.042 45.264 0.042 45.288 ;
    END
  END vmq[107]
  PIN vmq[108]
    DIRECTION OUTPUT ;
    USE SIGNAL ;
    PORT
      LAYER M4 ;
        RECT  -0.042 45.36 0.042 45.384 ;
    END
  END vmq[108]
  PIN vmq[109]
    DIRECTION OUTPUT ;
    USE SIGNAL ;
    PORT
      LAYER M4 ;
        RECT  -0.042 45.456 0.042 45.48 ;
    END
  END vmq[109]
  PIN vmq[10]
    DIRECTION OUTPUT ;
    USE SIGNAL ;
    PORT
      LAYER M4 ;
        RECT  -0.042 35.952 0.042 35.976 ;
    END
  END vmq[10]
  PIN vmq[110]
    DIRECTION OUTPUT ;
    USE SIGNAL ;
    PORT
      LAYER M4 ;
        RECT  -0.042 45.552 0.042 45.576 ;
    END
  END vmq[110]
  PIN vmq[111]
    DIRECTION OUTPUT ;
    USE SIGNAL ;
    PORT
      LAYER M4 ;
        RECT  -0.042 45.648 0.042 45.672 ;
    END
  END vmq[111]
  PIN vmq[112]
    DIRECTION OUTPUT ;
    USE SIGNAL ;
    PORT
      LAYER M4 ;
        RECT  -0.042 45.744 0.042 45.768 ;
    END
  END vmq[112]
  PIN vmq[113]
    DIRECTION OUTPUT ;
    USE SIGNAL ;
    PORT
      LAYER M4 ;
        RECT  -0.042 45.84 0.042 45.864 ;
    END
  END vmq[113]
  PIN vmq[114]
    DIRECTION OUTPUT ;
    USE SIGNAL ;
    PORT
      LAYER M4 ;
        RECT  -0.042 45.936 0.042 45.96 ;
    END
  END vmq[114]
  PIN vmq[115]
    DIRECTION OUTPUT ;
    USE SIGNAL ;
    PORT
      LAYER M4 ;
        RECT  -0.042 46.032 0.042 46.056 ;
    END
  END vmq[115]
  PIN vmq[116]
    DIRECTION OUTPUT ;
    USE SIGNAL ;
    PORT
      LAYER M4 ;
        RECT  -0.042 46.128 0.042 46.152 ;
    END
  END vmq[116]
  PIN vmq[117]
    DIRECTION OUTPUT ;
    USE SIGNAL ;
    PORT
      LAYER M4 ;
        RECT  -0.042 46.224 0.042 46.248 ;
    END
  END vmq[117]
  PIN vmq[118]
    DIRECTION OUTPUT ;
    USE SIGNAL ;
    PORT
      LAYER M4 ;
        RECT  -0.042 46.32 0.042 46.344 ;
    END
  END vmq[118]
  PIN vmq[119]
    DIRECTION OUTPUT ;
    USE SIGNAL ;
    PORT
      LAYER M4 ;
        RECT  -0.042 46.416 0.042 46.44 ;
    END
  END vmq[119]
  PIN vmq[11]
    DIRECTION OUTPUT ;
    USE SIGNAL ;
    PORT
      LAYER M4 ;
        RECT  -0.042 36.048 0.042 36.072 ;
    END
  END vmq[11]
  PIN vmq[120]
    DIRECTION OUTPUT ;
    USE SIGNAL ;
    PORT
      LAYER M4 ;
        RECT  -0.042 46.512 0.042 46.536 ;
    END
  END vmq[120]
  PIN vmq[121]
    DIRECTION OUTPUT ;
    USE SIGNAL ;
    PORT
      LAYER M4 ;
        RECT  -0.042 46.608 0.042 46.632 ;
    END
  END vmq[121]
  PIN vmq[122]
    DIRECTION OUTPUT ;
    USE SIGNAL ;
    PORT
      LAYER M4 ;
        RECT  -0.042 46.704 0.042 46.728 ;
    END
  END vmq[122]
  PIN vmq[123]
    DIRECTION OUTPUT ;
    USE SIGNAL ;
    PORT
      LAYER M4 ;
        RECT  -0.042 46.8 0.042 46.824 ;
    END
  END vmq[123]
  PIN vmq[124]
    DIRECTION OUTPUT ;
    USE SIGNAL ;
    PORT
      LAYER M4 ;
        RECT  -0.042 46.896 0.042 46.92 ;
    END
  END vmq[124]
  PIN vmq[125]
    DIRECTION OUTPUT ;
    USE SIGNAL ;
    PORT
      LAYER M4 ;
        RECT  -0.042 46.992 0.042 47.016 ;
    END
  END vmq[125]
  PIN vmq[126]
    DIRECTION OUTPUT ;
    USE SIGNAL ;
    PORT
      LAYER M4 ;
        RECT  -0.042 47.088 0.042 47.112 ;
    END
  END vmq[126]
  PIN vmq[127]
    DIRECTION OUTPUT ;
    USE SIGNAL ;
    PORT
      LAYER M4 ;
        RECT  -0.042 47.184 0.042 47.208 ;
    END
  END vmq[127]
  PIN vmq[128]
    DIRECTION OUTPUT ;
    USE SIGNAL ;
    PORT
      LAYER M4 ;
        RECT  -0.042 47.28 0.042 47.304 ;
    END
  END vmq[128]
  PIN vmq[129]
    DIRECTION OUTPUT ;
    USE SIGNAL ;
    PORT
      LAYER M4 ;
        RECT  -0.042 47.376 0.042 47.4 ;
    END
  END vmq[129]
  PIN vmq[12]
    DIRECTION OUTPUT ;
    USE SIGNAL ;
    PORT
      LAYER M4 ;
        RECT  -0.042 36.144 0.042 36.168 ;
    END
  END vmq[12]
  PIN vmq[130]
    DIRECTION OUTPUT ;
    USE SIGNAL ;
    PORT
      LAYER M4 ;
        RECT  -0.042 47.472 0.042 47.496 ;
    END
  END vmq[130]
  PIN vmq[131]
    DIRECTION OUTPUT ;
    USE SIGNAL ;
    PORT
      LAYER M4 ;
        RECT  -0.042 47.568 0.042 47.592 ;
    END
  END vmq[131]
  PIN vmq[132]
    DIRECTION OUTPUT ;
    USE SIGNAL ;
    PORT
      LAYER M4 ;
        RECT  -0.042 47.664 0.042 47.688 ;
    END
  END vmq[132]
  PIN vmq[133]
    DIRECTION OUTPUT ;
    USE SIGNAL ;
    PORT
      LAYER M4 ;
        RECT  -0.042 47.76 0.042 47.784 ;
    END
  END vmq[133]
  PIN vmq[134]
    DIRECTION OUTPUT ;
    USE SIGNAL ;
    PORT
      LAYER M4 ;
        RECT  -0.042 47.856 0.042 47.88 ;
    END
  END vmq[134]
  PIN vmq[135]
    DIRECTION OUTPUT ;
    USE SIGNAL ;
    PORT
      LAYER M4 ;
        RECT  -0.042 47.952 0.042 47.976 ;
    END
  END vmq[135]
  PIN vmq[136]
    DIRECTION OUTPUT ;
    USE SIGNAL ;
    PORT
      LAYER M4 ;
        RECT  -0.042 48.048 0.042 48.072 ;
    END
  END vmq[136]
  PIN vmq[137]
    DIRECTION OUTPUT ;
    USE SIGNAL ;
    PORT
      LAYER M4 ;
        RECT  -0.042 48.144 0.042 48.168 ;
    END
  END vmq[137]
  PIN vmq[138]
    DIRECTION OUTPUT ;
    USE SIGNAL ;
    PORT
      LAYER M4 ;
        RECT  -0.042 48.24 0.042 48.264 ;
    END
  END vmq[138]
  PIN vmq[139]
    DIRECTION OUTPUT ;
    USE SIGNAL ;
    PORT
      LAYER M4 ;
        RECT  -0.042 48.336 0.042 48.36 ;
    END
  END vmq[139]
  PIN vmq[13]
    DIRECTION OUTPUT ;
    USE SIGNAL ;
    PORT
      LAYER M4 ;
        RECT  -0.042 36.24 0.042 36.264 ;
    END
  END vmq[13]
  PIN vmq[140]
    DIRECTION OUTPUT ;
    USE SIGNAL ;
    PORT
      LAYER M4 ;
        RECT  -0.042 48.432 0.042 48.456 ;
    END
  END vmq[140]
  PIN vmq[141]
    DIRECTION OUTPUT ;
    USE SIGNAL ;
    PORT
      LAYER M4 ;
        RECT  -0.042 48.528 0.042 48.552 ;
    END
  END vmq[141]
  PIN vmq[142]
    DIRECTION OUTPUT ;
    USE SIGNAL ;
    PORT
      LAYER M4 ;
        RECT  -0.042 48.624 0.042 48.648 ;
    END
  END vmq[142]
  PIN vmq[143]
    DIRECTION OUTPUT ;
    USE SIGNAL ;
    PORT
      LAYER M4 ;
        RECT  -0.042 48.72 0.042 48.744 ;
    END
  END vmq[143]
  PIN vmq[144]
    DIRECTION OUTPUT ;
    USE SIGNAL ;
    PORT
      LAYER M4 ;
        RECT  -0.042 48.816 0.042 48.84 ;
    END
  END vmq[144]
  PIN vmq[145]
    DIRECTION OUTPUT ;
    USE SIGNAL ;
    PORT
      LAYER M4 ;
        RECT  -0.042 48.912 0.042 48.936 ;
    END
  END vmq[145]
  PIN vmq[146]
    DIRECTION OUTPUT ;
    USE SIGNAL ;
    PORT
      LAYER M4 ;
        RECT  -0.042 49.008 0.042 49.032 ;
    END
  END vmq[146]
  PIN vmq[147]
    DIRECTION OUTPUT ;
    USE SIGNAL ;
    PORT
      LAYER M4 ;
        RECT  -0.042 49.104 0.042 49.128 ;
    END
  END vmq[147]
  PIN vmq[148]
    DIRECTION OUTPUT ;
    USE SIGNAL ;
    PORT
      LAYER M4 ;
        RECT  -0.042 49.2 0.042 49.224 ;
    END
  END vmq[148]
  PIN vmq[149]
    DIRECTION OUTPUT ;
    USE SIGNAL ;
    PORT
      LAYER M4 ;
        RECT  -0.042 49.296 0.042 49.32 ;
    END
  END vmq[149]
  PIN vmq[14]
    DIRECTION OUTPUT ;
    USE SIGNAL ;
    PORT
      LAYER M4 ;
        RECT  -0.042 36.336 0.042 36.36 ;
    END
  END vmq[14]
  PIN vmq[150]
    DIRECTION OUTPUT ;
    USE SIGNAL ;
    PORT
      LAYER M4 ;
        RECT  -0.042 49.392 0.042 49.416 ;
    END
  END vmq[150]
  PIN vmq[151]
    DIRECTION OUTPUT ;
    USE SIGNAL ;
    PORT
      LAYER M4 ;
        RECT  -0.042 49.488 0.042 49.512 ;
    END
  END vmq[151]
  PIN vmq[152]
    DIRECTION OUTPUT ;
    USE SIGNAL ;
    PORT
      LAYER M4 ;
        RECT  -0.042 49.584 0.042 49.608 ;
    END
  END vmq[152]
  PIN vmq[153]
    DIRECTION OUTPUT ;
    USE SIGNAL ;
    PORT
      LAYER M4 ;
        RECT  -0.042 49.68 0.042 49.704 ;
    END
  END vmq[153]
  PIN vmq[154]
    DIRECTION OUTPUT ;
    USE SIGNAL ;
    PORT
      LAYER M4 ;
        RECT  -0.042 49.776 0.042 49.8 ;
    END
  END vmq[154]
  PIN vmq[155]
    DIRECTION OUTPUT ;
    USE SIGNAL ;
    PORT
      LAYER M4 ;
        RECT  -0.042 49.872 0.042 49.896 ;
    END
  END vmq[155]
  PIN vmq[156]
    DIRECTION OUTPUT ;
    USE SIGNAL ;
    PORT
      LAYER M4 ;
        RECT  -0.042 49.968 0.042 49.992 ;
    END
  END vmq[156]
  PIN vmq[157]
    DIRECTION OUTPUT ;
    USE SIGNAL ;
    PORT
      LAYER M4 ;
        RECT  -0.042 50.064 0.042 50.088 ;
    END
  END vmq[157]
  PIN vmq[158]
    DIRECTION OUTPUT ;
    USE SIGNAL ;
    PORT
      LAYER M4 ;
        RECT  -0.042 50.16 0.042 50.184 ;
    END
  END vmq[158]
  PIN vmq[159]
    DIRECTION OUTPUT ;
    USE SIGNAL ;
    PORT
      LAYER M4 ;
        RECT  -0.042 50.256 0.042 50.28 ;
    END
  END vmq[159]
  PIN vmq[15]
    DIRECTION OUTPUT ;
    USE SIGNAL ;
    PORT
      LAYER M4 ;
        RECT  -0.042 36.432 0.042 36.456 ;
    END
  END vmq[15]
  PIN vmq[160]
    DIRECTION OUTPUT ;
    USE SIGNAL ;
    PORT
      LAYER M4 ;
        RECT  -0.042 50.352 0.042 50.376 ;
    END
  END vmq[160]
  PIN vmq[161]
    DIRECTION OUTPUT ;
    USE SIGNAL ;
    PORT
      LAYER M4 ;
        RECT  -0.042 50.448 0.042 50.472 ;
    END
  END vmq[161]
  PIN vmq[162]
    DIRECTION OUTPUT ;
    USE SIGNAL ;
    PORT
      LAYER M4 ;
        RECT  -0.042 50.544 0.042 50.568 ;
    END
  END vmq[162]
  PIN vmq[163]
    DIRECTION OUTPUT ;
    USE SIGNAL ;
    PORT
      LAYER M4 ;
        RECT  -0.042 50.64 0.042 50.664 ;
    END
  END vmq[163]
  PIN vmq[164]
    DIRECTION OUTPUT ;
    USE SIGNAL ;
    PORT
      LAYER M4 ;
        RECT  -0.042 50.736 0.042 50.76 ;
    END
  END vmq[164]
  PIN vmq[165]
    DIRECTION OUTPUT ;
    USE SIGNAL ;
    PORT
      LAYER M4 ;
        RECT  -0.042 50.832 0.042 50.856 ;
    END
  END vmq[165]
  PIN vmq[166]
    DIRECTION OUTPUT ;
    USE SIGNAL ;
    PORT
      LAYER M4 ;
        RECT  -0.042 50.928 0.042 50.952 ;
    END
  END vmq[166]
  PIN vmq[167]
    DIRECTION OUTPUT ;
    USE SIGNAL ;
    PORT
      LAYER M4 ;
        RECT  -0.042 51.024 0.042 51.048 ;
    END
  END vmq[167]
  PIN vmq[168]
    DIRECTION OUTPUT ;
    USE SIGNAL ;
    PORT
      LAYER M4 ;
        RECT  -0.042 51.12 0.042 51.144 ;
    END
  END vmq[168]
  PIN vmq[169]
    DIRECTION OUTPUT ;
    USE SIGNAL ;
    PORT
      LAYER M4 ;
        RECT  -0.042 51.216 0.042 51.24 ;
    END
  END vmq[169]
  PIN vmq[16]
    DIRECTION OUTPUT ;
    USE SIGNAL ;
    PORT
      LAYER M4 ;
        RECT  -0.042 36.528 0.042 36.552 ;
    END
  END vmq[16]
  PIN vmq[170]
    DIRECTION OUTPUT ;
    USE SIGNAL ;
    PORT
      LAYER M4 ;
        RECT  -0.042 51.312 0.042 51.336 ;
    END
  END vmq[170]
  PIN vmq[171]
    DIRECTION OUTPUT ;
    USE SIGNAL ;
    PORT
      LAYER M4 ;
        RECT  -0.042 51.408 0.042 51.432 ;
    END
  END vmq[171]
  PIN vmq[172]
    DIRECTION OUTPUT ;
    USE SIGNAL ;
    PORT
      LAYER M4 ;
        RECT  -0.042 51.504 0.042 51.528 ;
    END
  END vmq[172]
  PIN vmq[173]
    DIRECTION OUTPUT ;
    USE SIGNAL ;
    PORT
      LAYER M4 ;
        RECT  -0.042 51.6 0.042 51.624 ;
    END
  END vmq[173]
  PIN vmq[174]
    DIRECTION OUTPUT ;
    USE SIGNAL ;
    PORT
      LAYER M4 ;
        RECT  -0.042 51.696 0.042 51.72 ;
    END
  END vmq[174]
  PIN vmq[175]
    DIRECTION OUTPUT ;
    USE SIGNAL ;
    PORT
      LAYER M4 ;
        RECT  -0.042 51.792 0.042 51.816 ;
    END
  END vmq[175]
  PIN vmq[176]
    DIRECTION OUTPUT ;
    USE SIGNAL ;
    PORT
      LAYER M4 ;
        RECT  -0.042 51.888 0.042 51.912 ;
    END
  END vmq[176]
  PIN vmq[177]
    DIRECTION OUTPUT ;
    USE SIGNAL ;
    PORT
      LAYER M4 ;
        RECT  -0.042 51.984 0.042 52.008 ;
    END
  END vmq[177]
  PIN vmq[178]
    DIRECTION OUTPUT ;
    USE SIGNAL ;
    PORT
      LAYER M4 ;
        RECT  -0.042 52.08 0.042 52.104 ;
    END
  END vmq[178]
  PIN vmq[179]
    DIRECTION OUTPUT ;
    USE SIGNAL ;
    PORT
      LAYER M4 ;
        RECT  -0.042 52.176 0.042 52.2 ;
    END
  END vmq[179]
  PIN vmq[17]
    DIRECTION OUTPUT ;
    USE SIGNAL ;
    PORT
      LAYER M4 ;
        RECT  -0.042 36.624 0.042 36.648 ;
    END
  END vmq[17]
  PIN vmq[180]
    DIRECTION OUTPUT ;
    USE SIGNAL ;
    PORT
      LAYER M4 ;
        RECT  -0.042 52.272 0.042 52.296 ;
    END
  END vmq[180]
  PIN vmq[181]
    DIRECTION OUTPUT ;
    USE SIGNAL ;
    PORT
      LAYER M4 ;
        RECT  -0.042 52.368 0.042 52.392 ;
    END
  END vmq[181]
  PIN vmq[182]
    DIRECTION OUTPUT ;
    USE SIGNAL ;
    PORT
      LAYER M4 ;
        RECT  -0.042 52.464 0.042 52.488 ;
    END
  END vmq[182]
  PIN vmq[183]
    DIRECTION OUTPUT ;
    USE SIGNAL ;
    PORT
      LAYER M4 ;
        RECT  -0.042 52.56 0.042 52.584 ;
    END
  END vmq[183]
  PIN vmq[184]
    DIRECTION OUTPUT ;
    USE SIGNAL ;
    PORT
      LAYER M4 ;
        RECT  -0.042 52.656 0.042 52.68 ;
    END
  END vmq[184]
  PIN vmq[185]
    DIRECTION OUTPUT ;
    USE SIGNAL ;
    PORT
      LAYER M4 ;
        RECT  -0.042 52.752 0.042 52.776 ;
    END
  END vmq[185]
  PIN vmq[186]
    DIRECTION OUTPUT ;
    USE SIGNAL ;
    PORT
      LAYER M4 ;
        RECT  -0.042 52.848 0.042 52.872 ;
    END
  END vmq[186]
  PIN vmq[187]
    DIRECTION OUTPUT ;
    USE SIGNAL ;
    PORT
      LAYER M4 ;
        RECT  -0.042 52.944 0.042 52.968 ;
    END
  END vmq[187]
  PIN vmq[188]
    DIRECTION OUTPUT ;
    USE SIGNAL ;
    PORT
      LAYER M4 ;
        RECT  -0.042 53.04 0.042 53.064 ;
    END
  END vmq[188]
  PIN vmq[189]
    DIRECTION OUTPUT ;
    USE SIGNAL ;
    PORT
      LAYER M4 ;
        RECT  -0.042 53.136 0.042 53.16 ;
    END
  END vmq[189]
  PIN vmq[18]
    DIRECTION OUTPUT ;
    USE SIGNAL ;
    PORT
      LAYER M4 ;
        RECT  -0.042 36.72 0.042 36.744 ;
    END
  END vmq[18]
  PIN vmq[190]
    DIRECTION OUTPUT ;
    USE SIGNAL ;
    PORT
      LAYER M4 ;
        RECT  -0.042 53.232 0.042 53.256 ;
    END
  END vmq[190]
  PIN vmq[191]
    DIRECTION OUTPUT ;
    USE SIGNAL ;
    PORT
      LAYER M4 ;
        RECT  -0.042 53.328 0.042 53.352 ;
    END
  END vmq[191]
  PIN vmq[192]
    DIRECTION OUTPUT ;
    USE SIGNAL ;
    PORT
      LAYER M4 ;
        RECT  -0.042 53.424 0.042 53.448 ;
    END
  END vmq[192]
  PIN vmq[193]
    DIRECTION OUTPUT ;
    USE SIGNAL ;
    PORT
      LAYER M4 ;
        RECT  -0.042 53.52 0.042 53.544 ;
    END
  END vmq[193]
  PIN vmq[194]
    DIRECTION OUTPUT ;
    USE SIGNAL ;
    PORT
      LAYER M4 ;
        RECT  -0.042 53.616 0.042 53.64 ;
    END
  END vmq[194]
  PIN vmq[195]
    DIRECTION OUTPUT ;
    USE SIGNAL ;
    PORT
      LAYER M4 ;
        RECT  -0.042 53.712 0.042 53.736 ;
    END
  END vmq[195]
  PIN vmq[196]
    DIRECTION OUTPUT ;
    USE SIGNAL ;
    PORT
      LAYER M4 ;
        RECT  -0.042 53.808 0.042 53.832 ;
    END
  END vmq[196]
  PIN vmq[197]
    DIRECTION OUTPUT ;
    USE SIGNAL ;
    PORT
      LAYER M4 ;
        RECT  -0.042 53.904 0.042 53.928 ;
    END
  END vmq[197]
  PIN vmq[198]
    DIRECTION OUTPUT ;
    USE SIGNAL ;
    PORT
      LAYER M4 ;
        RECT  -0.042 54 0.042 54.024 ;
    END
  END vmq[198]
  PIN vmq[199]
    DIRECTION OUTPUT ;
    USE SIGNAL ;
    PORT
      LAYER M4 ;
        RECT  -0.042 54.096 0.042 54.12 ;
    END
  END vmq[199]
  PIN vmq[19]
    DIRECTION OUTPUT ;
    USE SIGNAL ;
    PORT
      LAYER M4 ;
        RECT  -0.042 36.816 0.042 36.84 ;
    END
  END vmq[19]
  PIN vmq[1]
    DIRECTION OUTPUT ;
    USE SIGNAL ;
    PORT
      LAYER M4 ;
        RECT  -0.042 35.088 0.042 35.112 ;
    END
  END vmq[1]
  PIN vmq[200]
    DIRECTION OUTPUT ;
    USE SIGNAL ;
    PORT
      LAYER M4 ;
        RECT  -0.042 54.192 0.042 54.216 ;
    END
  END vmq[200]
  PIN vmq[201]
    DIRECTION OUTPUT ;
    USE SIGNAL ;
    PORT
      LAYER M4 ;
        RECT  -0.042 54.288 0.042 54.312 ;
    END
  END vmq[201]
  PIN vmq[202]
    DIRECTION OUTPUT ;
    USE SIGNAL ;
    PORT
      LAYER M4 ;
        RECT  -0.042 54.384 0.042 54.408 ;
    END
  END vmq[202]
  PIN vmq[203]
    DIRECTION OUTPUT ;
    USE SIGNAL ;
    PORT
      LAYER M4 ;
        RECT  -0.042 54.48 0.042 54.504 ;
    END
  END vmq[203]
  PIN vmq[204]
    DIRECTION OUTPUT ;
    USE SIGNAL ;
    PORT
      LAYER M4 ;
        RECT  -0.042 54.576 0.042 54.6 ;
    END
  END vmq[204]
  PIN vmq[205]
    DIRECTION OUTPUT ;
    USE SIGNAL ;
    PORT
      LAYER M4 ;
        RECT  -0.042 54.672 0.042 54.696 ;
    END
  END vmq[205]
  PIN vmq[206]
    DIRECTION OUTPUT ;
    USE SIGNAL ;
    PORT
      LAYER M4 ;
        RECT  -0.042 54.768 0.042 54.792 ;
    END
  END vmq[206]
  PIN vmq[207]
    DIRECTION OUTPUT ;
    USE SIGNAL ;
    PORT
      LAYER M4 ;
        RECT  -0.042 54.864 0.042 54.888 ;
    END
  END vmq[207]
  PIN vmq[208]
    DIRECTION OUTPUT ;
    USE SIGNAL ;
    PORT
      LAYER M4 ;
        RECT  -0.042 54.96 0.042 54.984 ;
    END
  END vmq[208]
  PIN vmq[209]
    DIRECTION OUTPUT ;
    USE SIGNAL ;
    PORT
      LAYER M4 ;
        RECT  -0.042 55.056 0.042 55.08 ;
    END
  END vmq[209]
  PIN vmq[20]
    DIRECTION OUTPUT ;
    USE SIGNAL ;
    PORT
      LAYER M4 ;
        RECT  -0.042 36.912 0.042 36.936 ;
    END
  END vmq[20]
  PIN vmq[210]
    DIRECTION OUTPUT ;
    USE SIGNAL ;
    PORT
      LAYER M4 ;
        RECT  -0.042 55.152 0.042 55.176 ;
    END
  END vmq[210]
  PIN vmq[211]
    DIRECTION OUTPUT ;
    USE SIGNAL ;
    PORT
      LAYER M4 ;
        RECT  -0.042 55.248 0.042 55.272 ;
    END
  END vmq[211]
  PIN vmq[212]
    DIRECTION OUTPUT ;
    USE SIGNAL ;
    PORT
      LAYER M4 ;
        RECT  -0.042 55.344 0.042 55.368 ;
    END
  END vmq[212]
  PIN vmq[213]
    DIRECTION OUTPUT ;
    USE SIGNAL ;
    PORT
      LAYER M4 ;
        RECT  -0.042 55.44 0.042 55.464 ;
    END
  END vmq[213]
  PIN vmq[214]
    DIRECTION OUTPUT ;
    USE SIGNAL ;
    PORT
      LAYER M4 ;
        RECT  -0.042 55.536 0.042 55.56 ;
    END
  END vmq[214]
  PIN vmq[215]
    DIRECTION OUTPUT ;
    USE SIGNAL ;
    PORT
      LAYER M4 ;
        RECT  -0.042 55.632 0.042 55.656 ;
    END
  END vmq[215]
  PIN vmq[216]
    DIRECTION OUTPUT ;
    USE SIGNAL ;
    PORT
      LAYER M4 ;
        RECT  -0.042 55.728 0.042 55.752 ;
    END
  END vmq[216]
  PIN vmq[217]
    DIRECTION OUTPUT ;
    USE SIGNAL ;
    PORT
      LAYER M4 ;
        RECT  -0.042 55.824 0.042 55.848 ;
    END
  END vmq[217]
  PIN vmq[218]
    DIRECTION OUTPUT ;
    USE SIGNAL ;
    PORT
      LAYER M4 ;
        RECT  -0.042 55.92 0.042 55.944 ;
    END
  END vmq[218]
  PIN vmq[219]
    DIRECTION OUTPUT ;
    USE SIGNAL ;
    PORT
      LAYER M4 ;
        RECT  -0.042 56.016 0.042 56.04 ;
    END
  END vmq[219]
  PIN vmq[21]
    DIRECTION OUTPUT ;
    USE SIGNAL ;
    PORT
      LAYER M4 ;
        RECT  -0.042 37.008 0.042 37.032 ;
    END
  END vmq[21]
  PIN vmq[220]
    DIRECTION OUTPUT ;
    USE SIGNAL ;
    PORT
      LAYER M4 ;
        RECT  -0.042 56.112 0.042 56.136 ;
    END
  END vmq[220]
  PIN vmq[221]
    DIRECTION OUTPUT ;
    USE SIGNAL ;
    PORT
      LAYER M4 ;
        RECT  -0.042 56.208 0.042 56.232 ;
    END
  END vmq[221]
  PIN vmq[222]
    DIRECTION OUTPUT ;
    USE SIGNAL ;
    PORT
      LAYER M4 ;
        RECT  -0.042 56.304 0.042 56.328 ;
    END
  END vmq[222]
  PIN vmq[223]
    DIRECTION OUTPUT ;
    USE SIGNAL ;
    PORT
      LAYER M4 ;
        RECT  -0.042 56.4 0.042 56.424 ;
    END
  END vmq[223]
  PIN vmq[224]
    DIRECTION OUTPUT ;
    USE SIGNAL ;
    PORT
      LAYER M4 ;
        RECT  -0.042 56.496 0.042 56.52 ;
    END
  END vmq[224]
  PIN vmq[225]
    DIRECTION OUTPUT ;
    USE SIGNAL ;
    PORT
      LAYER M4 ;
        RECT  -0.042 56.592 0.042 56.616 ;
    END
  END vmq[225]
  PIN vmq[226]
    DIRECTION OUTPUT ;
    USE SIGNAL ;
    PORT
      LAYER M4 ;
        RECT  -0.042 56.688 0.042 56.712 ;
    END
  END vmq[226]
  PIN vmq[227]
    DIRECTION OUTPUT ;
    USE SIGNAL ;
    PORT
      LAYER M4 ;
        RECT  -0.042 56.784 0.042 56.808 ;
    END
  END vmq[227]
  PIN vmq[228]
    DIRECTION OUTPUT ;
    USE SIGNAL ;
    PORT
      LAYER M4 ;
        RECT  -0.042 56.88 0.042 56.904 ;
    END
  END vmq[228]
  PIN vmq[229]
    DIRECTION OUTPUT ;
    USE SIGNAL ;
    PORT
      LAYER M4 ;
        RECT  -0.042 56.976 0.042 57 ;
    END
  END vmq[229]
  PIN vmq[22]
    DIRECTION OUTPUT ;
    USE SIGNAL ;
    PORT
      LAYER M4 ;
        RECT  -0.042 37.104 0.042 37.128 ;
    END
  END vmq[22]
  PIN vmq[230]
    DIRECTION OUTPUT ;
    USE SIGNAL ;
    PORT
      LAYER M4 ;
        RECT  -0.042 57.072 0.042 57.096 ;
    END
  END vmq[230]
  PIN vmq[231]
    DIRECTION OUTPUT ;
    USE SIGNAL ;
    PORT
      LAYER M4 ;
        RECT  -0.042 57.168 0.042 57.192 ;
    END
  END vmq[231]
  PIN vmq[232]
    DIRECTION OUTPUT ;
    USE SIGNAL ;
    PORT
      LAYER M4 ;
        RECT  -0.042 57.264 0.042 57.288 ;
    END
  END vmq[232]
  PIN vmq[233]
    DIRECTION OUTPUT ;
    USE SIGNAL ;
    PORT
      LAYER M4 ;
        RECT  -0.042 57.36 0.042 57.384 ;
    END
  END vmq[233]
  PIN vmq[234]
    DIRECTION OUTPUT ;
    USE SIGNAL ;
    PORT
      LAYER M4 ;
        RECT  -0.042 57.456 0.042 57.48 ;
    END
  END vmq[234]
  PIN vmq[235]
    DIRECTION OUTPUT ;
    USE SIGNAL ;
    PORT
      LAYER M4 ;
        RECT  -0.042 57.552 0.042 57.576 ;
    END
  END vmq[235]
  PIN vmq[236]
    DIRECTION OUTPUT ;
    USE SIGNAL ;
    PORT
      LAYER M4 ;
        RECT  -0.042 57.648 0.042 57.672 ;
    END
  END vmq[236]
  PIN vmq[237]
    DIRECTION OUTPUT ;
    USE SIGNAL ;
    PORT
      LAYER M4 ;
        RECT  -0.042 57.744 0.042 57.768 ;
    END
  END vmq[237]
  PIN vmq[238]
    DIRECTION OUTPUT ;
    USE SIGNAL ;
    PORT
      LAYER M4 ;
        RECT  -0.042 57.84 0.042 57.864 ;
    END
  END vmq[238]
  PIN vmq[239]
    DIRECTION OUTPUT ;
    USE SIGNAL ;
    PORT
      LAYER M4 ;
        RECT  -0.042 57.936 0.042 57.96 ;
    END
  END vmq[239]
  PIN vmq[23]
    DIRECTION OUTPUT ;
    USE SIGNAL ;
    PORT
      LAYER M4 ;
        RECT  -0.042 37.2 0.042 37.224 ;
    END
  END vmq[23]
  PIN vmq[240]
    DIRECTION OUTPUT ;
    USE SIGNAL ;
    PORT
      LAYER M4 ;
        RECT  -0.042 58.032 0.042 58.056 ;
    END
  END vmq[240]
  PIN vmq[241]
    DIRECTION OUTPUT ;
    USE SIGNAL ;
    PORT
      LAYER M4 ;
        RECT  -0.042 58.128 0.042 58.152 ;
    END
  END vmq[241]
  PIN vmq[242]
    DIRECTION OUTPUT ;
    USE SIGNAL ;
    PORT
      LAYER M4 ;
        RECT  -0.042 58.224 0.042 58.248 ;
    END
  END vmq[242]
  PIN vmq[243]
    DIRECTION OUTPUT ;
    USE SIGNAL ;
    PORT
      LAYER M4 ;
        RECT  -0.042 58.32 0.042 58.344 ;
    END
  END vmq[243]
  PIN vmq[244]
    DIRECTION OUTPUT ;
    USE SIGNAL ;
    PORT
      LAYER M4 ;
        RECT  -0.042 58.416 0.042 58.44 ;
    END
  END vmq[244]
  PIN vmq[245]
    DIRECTION OUTPUT ;
    USE SIGNAL ;
    PORT
      LAYER M4 ;
        RECT  -0.042 58.512 0.042 58.536 ;
    END
  END vmq[245]
  PIN vmq[246]
    DIRECTION OUTPUT ;
    USE SIGNAL ;
    PORT
      LAYER M4 ;
        RECT  -0.042 58.608 0.042 58.632 ;
    END
  END vmq[246]
  PIN vmq[247]
    DIRECTION OUTPUT ;
    USE SIGNAL ;
    PORT
      LAYER M4 ;
        RECT  -0.042 58.704 0.042 58.728 ;
    END
  END vmq[247]
  PIN vmq[248]
    DIRECTION OUTPUT ;
    USE SIGNAL ;
    PORT
      LAYER M4 ;
        RECT  -0.042 58.8 0.042 58.824 ;
    END
  END vmq[248]
  PIN vmq[249]
    DIRECTION OUTPUT ;
    USE SIGNAL ;
    PORT
      LAYER M4 ;
        RECT  -0.042 58.896 0.042 58.92 ;
    END
  END vmq[249]
  PIN vmq[24]
    DIRECTION OUTPUT ;
    USE SIGNAL ;
    PORT
      LAYER M4 ;
        RECT  -0.042 37.296 0.042 37.32 ;
    END
  END vmq[24]
  PIN vmq[250]
    DIRECTION OUTPUT ;
    USE SIGNAL ;
    PORT
      LAYER M4 ;
        RECT  -0.042 58.992 0.042 59.016 ;
    END
  END vmq[250]
  PIN vmq[251]
    DIRECTION OUTPUT ;
    USE SIGNAL ;
    PORT
      LAYER M4 ;
        RECT  -0.042 59.088 0.042 59.112 ;
    END
  END vmq[251]
  PIN vmq[252]
    DIRECTION OUTPUT ;
    USE SIGNAL ;
    PORT
      LAYER M4 ;
        RECT  -0.042 59.184 0.042 59.208 ;
    END
  END vmq[252]
  PIN vmq[253]
    DIRECTION OUTPUT ;
    USE SIGNAL ;
    PORT
      LAYER M4 ;
        RECT  -0.042 59.28 0.042 59.304 ;
    END
  END vmq[253]
  PIN vmq[254]
    DIRECTION OUTPUT ;
    USE SIGNAL ;
    PORT
      LAYER M4 ;
        RECT  -0.042 59.376 0.042 59.4 ;
    END
  END vmq[254]
  PIN vmq[255]
    DIRECTION OUTPUT ;
    USE SIGNAL ;
    PORT
      LAYER M4 ;
        RECT  -0.042 59.472 0.042 59.496 ;
    END
  END vmq[255]
  PIN vmq[256]
    DIRECTION OUTPUT ;
    USE SIGNAL ;
    PORT
      LAYER M4 ;
        RECT  -0.042 59.568 0.042 59.592 ;
    END
  END vmq[256]
  PIN vmq[257]
    DIRECTION OUTPUT ;
    USE SIGNAL ;
    PORT
      LAYER M4 ;
        RECT  -0.042 59.664 0.042 59.688 ;
    END
  END vmq[257]
  PIN vmq[258]
    DIRECTION OUTPUT ;
    USE SIGNAL ;
    PORT
      LAYER M4 ;
        RECT  -0.042 59.76 0.042 59.784 ;
    END
  END vmq[258]
  PIN vmq[259]
    DIRECTION OUTPUT ;
    USE SIGNAL ;
    PORT
      LAYER M4 ;
        RECT  -0.042 59.856 0.042 59.88 ;
    END
  END vmq[259]
  PIN vmq[25]
    DIRECTION OUTPUT ;
    USE SIGNAL ;
    PORT
      LAYER M4 ;
        RECT  -0.042 37.392 0.042 37.416 ;
    END
  END vmq[25]
  PIN vmq[260]
    DIRECTION OUTPUT ;
    USE SIGNAL ;
    PORT
      LAYER M4 ;
        RECT  -0.042 59.952 0.042 59.976 ;
    END
  END vmq[260]
  PIN vmq[261]
    DIRECTION OUTPUT ;
    USE SIGNAL ;
    PORT
      LAYER M4 ;
        RECT  -0.042 60.048 0.042 60.072 ;
    END
  END vmq[261]
  PIN vmq[262]
    DIRECTION OUTPUT ;
    USE SIGNAL ;
    PORT
      LAYER M4 ;
        RECT  -0.042 60.144 0.042 60.168 ;
    END
  END vmq[262]
  PIN vmq[263]
    DIRECTION OUTPUT ;
    USE SIGNAL ;
    PORT
      LAYER M4 ;
        RECT  -0.042 60.24 0.042 60.264 ;
    END
  END vmq[263]
  PIN vmq[264]
    DIRECTION OUTPUT ;
    USE SIGNAL ;
    PORT
      LAYER M4 ;
        RECT  -0.042 60.336 0.042 60.36 ;
    END
  END vmq[264]
  PIN vmq[265]
    DIRECTION OUTPUT ;
    USE SIGNAL ;
    PORT
      LAYER M4 ;
        RECT  -0.042 60.432 0.042 60.456 ;
    END
  END vmq[265]
  PIN vmq[266]
    DIRECTION OUTPUT ;
    USE SIGNAL ;
    PORT
      LAYER M4 ;
        RECT  -0.042 60.528 0.042 60.552 ;
    END
  END vmq[266]
  PIN vmq[267]
    DIRECTION OUTPUT ;
    USE SIGNAL ;
    PORT
      LAYER M4 ;
        RECT  -0.042 60.624 0.042 60.648 ;
    END
  END vmq[267]
  PIN vmq[268]
    DIRECTION OUTPUT ;
    USE SIGNAL ;
    PORT
      LAYER M4 ;
        RECT  -0.042 60.72 0.042 60.744 ;
    END
  END vmq[268]
  PIN vmq[269]
    DIRECTION OUTPUT ;
    USE SIGNAL ;
    PORT
      LAYER M4 ;
        RECT  -0.042 60.816 0.042 60.84 ;
    END
  END vmq[269]
  PIN vmq[26]
    DIRECTION OUTPUT ;
    USE SIGNAL ;
    PORT
      LAYER M4 ;
        RECT  -0.042 37.488 0.042 37.512 ;
    END
  END vmq[26]
  PIN vmq[270]
    DIRECTION OUTPUT ;
    USE SIGNAL ;
    PORT
      LAYER M4 ;
        RECT  -0.042 60.912 0.042 60.936 ;
    END
  END vmq[270]
  PIN vmq[271]
    DIRECTION OUTPUT ;
    USE SIGNAL ;
    PORT
      LAYER M4 ;
        RECT  -0.042 61.008 0.042 61.032 ;
    END
  END vmq[271]
  PIN vmq[272]
    DIRECTION OUTPUT ;
    USE SIGNAL ;
    PORT
      LAYER M4 ;
        RECT  -0.042 61.104 0.042 61.128 ;
    END
  END vmq[272]
  PIN vmq[273]
    DIRECTION OUTPUT ;
    USE SIGNAL ;
    PORT
      LAYER M4 ;
        RECT  -0.042 61.2 0.042 61.224 ;
    END
  END vmq[273]
  PIN vmq[274]
    DIRECTION OUTPUT ;
    USE SIGNAL ;
    PORT
      LAYER M4 ;
        RECT  -0.042 61.296 0.042 61.32 ;
    END
  END vmq[274]
  PIN vmq[275]
    DIRECTION OUTPUT ;
    USE SIGNAL ;
    PORT
      LAYER M4 ;
        RECT  -0.042 61.392 0.042 61.416 ;
    END
  END vmq[275]
  PIN vmq[276]
    DIRECTION OUTPUT ;
    USE SIGNAL ;
    PORT
      LAYER M4 ;
        RECT  -0.042 61.488 0.042 61.512 ;
    END
  END vmq[276]
  PIN vmq[277]
    DIRECTION OUTPUT ;
    USE SIGNAL ;
    PORT
      LAYER M4 ;
        RECT  -0.042 61.584 0.042 61.608 ;
    END
  END vmq[277]
  PIN vmq[278]
    DIRECTION OUTPUT ;
    USE SIGNAL ;
    PORT
      LAYER M4 ;
        RECT  -0.042 61.68 0.042 61.704 ;
    END
  END vmq[278]
  PIN vmq[279]
    DIRECTION OUTPUT ;
    USE SIGNAL ;
    PORT
      LAYER M4 ;
        RECT  -0.042 61.776 0.042 61.8 ;
    END
  END vmq[279]
  PIN vmq[27]
    DIRECTION OUTPUT ;
    USE SIGNAL ;
    PORT
      LAYER M4 ;
        RECT  -0.042 37.584 0.042 37.608 ;
    END
  END vmq[27]
  PIN vmq[280]
    DIRECTION OUTPUT ;
    USE SIGNAL ;
    PORT
      LAYER M4 ;
        RECT  -0.042 61.872 0.042 61.896 ;
    END
  END vmq[280]
  PIN vmq[281]
    DIRECTION OUTPUT ;
    USE SIGNAL ;
    PORT
      LAYER M4 ;
        RECT  -0.042 61.968 0.042 61.992 ;
    END
  END vmq[281]
  PIN vmq[282]
    DIRECTION OUTPUT ;
    USE SIGNAL ;
    PORT
      LAYER M4 ;
        RECT  -0.042 62.064 0.042 62.088 ;
    END
  END vmq[282]
  PIN vmq[283]
    DIRECTION OUTPUT ;
    USE SIGNAL ;
    PORT
      LAYER M4 ;
        RECT  -0.042 62.16 0.042 62.184 ;
    END
  END vmq[283]
  PIN vmq[284]
    DIRECTION OUTPUT ;
    USE SIGNAL ;
    PORT
      LAYER M4 ;
        RECT  -0.042 62.256 0.042 62.28 ;
    END
  END vmq[284]
  PIN vmq[285]
    DIRECTION OUTPUT ;
    USE SIGNAL ;
    PORT
      LAYER M4 ;
        RECT  -0.042 62.352 0.042 62.376 ;
    END
  END vmq[285]
  PIN vmq[286]
    DIRECTION OUTPUT ;
    USE SIGNAL ;
    PORT
      LAYER M4 ;
        RECT  -0.042 62.448 0.042 62.472 ;
    END
  END vmq[286]
  PIN vmq[287]
    DIRECTION OUTPUT ;
    USE SIGNAL ;
    PORT
      LAYER M4 ;
        RECT  -0.042 62.544 0.042 62.568 ;
    END
  END vmq[287]
  PIN vmq[288]
    DIRECTION OUTPUT ;
    USE SIGNAL ;
    PORT
      LAYER M4 ;
        RECT  -0.042 62.64 0.042 62.664 ;
    END
  END vmq[288]
  PIN vmq[289]
    DIRECTION OUTPUT ;
    USE SIGNAL ;
    PORT
      LAYER M4 ;
        RECT  -0.042 62.736 0.042 62.76 ;
    END
  END vmq[289]
  PIN vmq[28]
    DIRECTION OUTPUT ;
    USE SIGNAL ;
    PORT
      LAYER M4 ;
        RECT  -0.042 37.68 0.042 37.704 ;
    END
  END vmq[28]
  PIN vmq[290]
    DIRECTION OUTPUT ;
    USE SIGNAL ;
    PORT
      LAYER M4 ;
        RECT  -0.042 62.832 0.042 62.856 ;
    END
  END vmq[290]
  PIN vmq[291]
    DIRECTION OUTPUT ;
    USE SIGNAL ;
    PORT
      LAYER M4 ;
        RECT  -0.042 62.928 0.042 62.952 ;
    END
  END vmq[291]
  PIN vmq[292]
    DIRECTION OUTPUT ;
    USE SIGNAL ;
    PORT
      LAYER M4 ;
        RECT  -0.042 63.024 0.042 63.048 ;
    END
  END vmq[292]
  PIN vmq[293]
    DIRECTION OUTPUT ;
    USE SIGNAL ;
    PORT
      LAYER M4 ;
        RECT  -0.042 63.12 0.042 63.144 ;
    END
  END vmq[293]
  PIN vmq[294]
    DIRECTION OUTPUT ;
    USE SIGNAL ;
    PORT
      LAYER M4 ;
        RECT  -0.042 63.216 0.042 63.24 ;
    END
  END vmq[294]
  PIN vmq[295]
    DIRECTION OUTPUT ;
    USE SIGNAL ;
    PORT
      LAYER M4 ;
        RECT  -0.042 63.312 0.042 63.336 ;
    END
  END vmq[295]
  PIN vmq[296]
    DIRECTION OUTPUT ;
    USE SIGNAL ;
    PORT
      LAYER M4 ;
        RECT  -0.042 63.408 0.042 63.432 ;
    END
  END vmq[296]
  PIN vmq[297]
    DIRECTION OUTPUT ;
    USE SIGNAL ;
    PORT
      LAYER M4 ;
        RECT  -0.042 63.504 0.042 63.528 ;
    END
  END vmq[297]
  PIN vmq[298]
    DIRECTION OUTPUT ;
    USE SIGNAL ;
    PORT
      LAYER M4 ;
        RECT  -0.042 63.6 0.042 63.624 ;
    END
  END vmq[298]
  PIN vmq[299]
    DIRECTION OUTPUT ;
    USE SIGNAL ;
    PORT
      LAYER M4 ;
        RECT  -0.042 63.696 0.042 63.72 ;
    END
  END vmq[299]
  PIN vmq[29]
    DIRECTION OUTPUT ;
    USE SIGNAL ;
    PORT
      LAYER M4 ;
        RECT  -0.042 37.776 0.042 37.8 ;
    END
  END vmq[29]
  PIN vmq[2]
    DIRECTION OUTPUT ;
    USE SIGNAL ;
    PORT
      LAYER M4 ;
        RECT  -0.042 35.184 0.042 35.208 ;
    END
  END vmq[2]
  PIN vmq[300]
    DIRECTION OUTPUT ;
    USE SIGNAL ;
    PORT
      LAYER M4 ;
        RECT  -0.042 63.792 0.042 63.816 ;
    END
  END vmq[300]
  PIN vmq[301]
    DIRECTION OUTPUT ;
    USE SIGNAL ;
    PORT
      LAYER M4 ;
        RECT  -0.042 63.888 0.042 63.912 ;
    END
  END vmq[301]
  PIN vmq[302]
    DIRECTION OUTPUT ;
    USE SIGNAL ;
    PORT
      LAYER M4 ;
        RECT  -0.042 63.984 0.042 64.008 ;
    END
  END vmq[302]
  PIN vmq[303]
    DIRECTION OUTPUT ;
    USE SIGNAL ;
    PORT
      LAYER M4 ;
        RECT  -0.042 64.08 0.042 64.104 ;
    END
  END vmq[303]
  PIN vmq[304]
    DIRECTION OUTPUT ;
    USE SIGNAL ;
    PORT
      LAYER M4 ;
        RECT  -0.042 64.176 0.042 64.2 ;
    END
  END vmq[304]
  PIN vmq[305]
    DIRECTION OUTPUT ;
    USE SIGNAL ;
    PORT
      LAYER M4 ;
        RECT  -0.042 64.272 0.042 64.296 ;
    END
  END vmq[305]
  PIN vmq[306]
    DIRECTION OUTPUT ;
    USE SIGNAL ;
    PORT
      LAYER M4 ;
        RECT  -0.042 64.368 0.042 64.392 ;
    END
  END vmq[306]
  PIN vmq[307]
    DIRECTION OUTPUT ;
    USE SIGNAL ;
    PORT
      LAYER M4 ;
        RECT  -0.042 64.464 0.042 64.488 ;
    END
  END vmq[307]
  PIN vmq[308]
    DIRECTION OUTPUT ;
    USE SIGNAL ;
    PORT
      LAYER M4 ;
        RECT  -0.042 64.56 0.042 64.584 ;
    END
  END vmq[308]
  PIN vmq[309]
    DIRECTION OUTPUT ;
    USE SIGNAL ;
    PORT
      LAYER M4 ;
        RECT  -0.042 64.656 0.042 64.68 ;
    END
  END vmq[309]
  PIN vmq[30]
    DIRECTION OUTPUT ;
    USE SIGNAL ;
    PORT
      LAYER M4 ;
        RECT  -0.042 37.872 0.042 37.896 ;
    END
  END vmq[30]
  PIN vmq[310]
    DIRECTION OUTPUT ;
    USE SIGNAL ;
    PORT
      LAYER M4 ;
        RECT  -0.042 64.752 0.042 64.776 ;
    END
  END vmq[310]
  PIN vmq[311]
    DIRECTION OUTPUT ;
    USE SIGNAL ;
    PORT
      LAYER M4 ;
        RECT  -0.042 64.848 0.042 64.872 ;
    END
  END vmq[311]
  PIN vmq[312]
    DIRECTION OUTPUT ;
    USE SIGNAL ;
    PORT
      LAYER M4 ;
        RECT  -0.042 64.944 0.042 64.968 ;
    END
  END vmq[312]
  PIN vmq[313]
    DIRECTION OUTPUT ;
    USE SIGNAL ;
    PORT
      LAYER M4 ;
        RECT  -0.042 65.04 0.042 65.064 ;
    END
  END vmq[313]
  PIN vmq[314]
    DIRECTION OUTPUT ;
    USE SIGNAL ;
    PORT
      LAYER M4 ;
        RECT  -0.042 65.136 0.042 65.16 ;
    END
  END vmq[314]
  PIN vmq[315]
    DIRECTION OUTPUT ;
    USE SIGNAL ;
    PORT
      LAYER M4 ;
        RECT  -0.042 65.232 0.042 65.256 ;
    END
  END vmq[315]
  PIN vmq[316]
    DIRECTION OUTPUT ;
    USE SIGNAL ;
    PORT
      LAYER M4 ;
        RECT  -0.042 65.328 0.042 65.352 ;
    END
  END vmq[316]
  PIN vmq[317]
    DIRECTION OUTPUT ;
    USE SIGNAL ;
    PORT
      LAYER M4 ;
        RECT  -0.042 65.424 0.042 65.448 ;
    END
  END vmq[317]
  PIN vmq[318]
    DIRECTION OUTPUT ;
    USE SIGNAL ;
    PORT
      LAYER M4 ;
        RECT  -0.042 65.52 0.042 65.544 ;
    END
  END vmq[318]
  PIN vmq[319]
    DIRECTION OUTPUT ;
    USE SIGNAL ;
    PORT
      LAYER M4 ;
        RECT  -0.042 65.616 0.042 65.64 ;
    END
  END vmq[319]
  PIN vmq[31]
    DIRECTION OUTPUT ;
    USE SIGNAL ;
    PORT
      LAYER M4 ;
        RECT  -0.042 37.968 0.042 37.992 ;
    END
  END vmq[31]
  PIN vmq[320]
    DIRECTION OUTPUT ;
    USE SIGNAL ;
    PORT
      LAYER M4 ;
        RECT  -0.042 65.712 0.042 65.736 ;
    END
  END vmq[320]
  PIN vmq[321]
    DIRECTION OUTPUT ;
    USE SIGNAL ;
    PORT
      LAYER M4 ;
        RECT  -0.042 65.808 0.042 65.832 ;
    END
  END vmq[321]
  PIN vmq[322]
    DIRECTION OUTPUT ;
    USE SIGNAL ;
    PORT
      LAYER M4 ;
        RECT  -0.042 65.904 0.042 65.928 ;
    END
  END vmq[322]
  PIN vmq[323]
    DIRECTION OUTPUT ;
    USE SIGNAL ;
    PORT
      LAYER M4 ;
        RECT  -0.042 66 0.042 66.024 ;
    END
  END vmq[323]
  PIN vmq[324]
    DIRECTION OUTPUT ;
    USE SIGNAL ;
    PORT
      LAYER M4 ;
        RECT  -0.042 66.096 0.042 66.12 ;
    END
  END vmq[324]
  PIN vmq[325]
    DIRECTION OUTPUT ;
    USE SIGNAL ;
    PORT
      LAYER M4 ;
        RECT  -0.042 66.192 0.042 66.216 ;
    END
  END vmq[325]
  PIN vmq[326]
    DIRECTION OUTPUT ;
    USE SIGNAL ;
    PORT
      LAYER M4 ;
        RECT  -0.042 66.288 0.042 66.312 ;
    END
  END vmq[326]
  PIN vmq[327]
    DIRECTION OUTPUT ;
    USE SIGNAL ;
    PORT
      LAYER M4 ;
        RECT  -0.042 66.384 0.042 66.408 ;
    END
  END vmq[327]
  PIN vmq[328]
    DIRECTION OUTPUT ;
    USE SIGNAL ;
    PORT
      LAYER M4 ;
        RECT  -0.042 66.48 0.042 66.504 ;
    END
  END vmq[328]
  PIN vmq[329]
    DIRECTION OUTPUT ;
    USE SIGNAL ;
    PORT
      LAYER M4 ;
        RECT  -0.042 66.576 0.042 66.6 ;
    END
  END vmq[329]
  PIN vmq[32]
    DIRECTION OUTPUT ;
    USE SIGNAL ;
    PORT
      LAYER M4 ;
        RECT  -0.042 38.064 0.042 38.088 ;
    END
  END vmq[32]
  PIN vmq[330]
    DIRECTION OUTPUT ;
    USE SIGNAL ;
    PORT
      LAYER M4 ;
        RECT  -0.042 66.672 0.042 66.696 ;
    END
  END vmq[330]
  PIN vmq[331]
    DIRECTION OUTPUT ;
    USE SIGNAL ;
    PORT
      LAYER M4 ;
        RECT  -0.042 66.768 0.042 66.792 ;
    END
  END vmq[331]
  PIN vmq[332]
    DIRECTION OUTPUT ;
    USE SIGNAL ;
    PORT
      LAYER M4 ;
        RECT  -0.042 66.864 0.042 66.888 ;
    END
  END vmq[332]
  PIN vmq[333]
    DIRECTION OUTPUT ;
    USE SIGNAL ;
    PORT
      LAYER M4 ;
        RECT  -0.042 66.96 0.042 66.984 ;
    END
  END vmq[333]
  PIN vmq[334]
    DIRECTION OUTPUT ;
    USE SIGNAL ;
    PORT
      LAYER M4 ;
        RECT  -0.042 67.056 0.042 67.08 ;
    END
  END vmq[334]
  PIN vmq[335]
    DIRECTION OUTPUT ;
    USE SIGNAL ;
    PORT
      LAYER M4 ;
        RECT  -0.042 67.152 0.042 67.176 ;
    END
  END vmq[335]
  PIN vmq[336]
    DIRECTION OUTPUT ;
    USE SIGNAL ;
    PORT
      LAYER M4 ;
        RECT  -0.042 67.248 0.042 67.272 ;
    END
  END vmq[336]
  PIN vmq[337]
    DIRECTION OUTPUT ;
    USE SIGNAL ;
    PORT
      LAYER M4 ;
        RECT  -0.042 67.344 0.042 67.368 ;
    END
  END vmq[337]
  PIN vmq[33]
    DIRECTION OUTPUT ;
    USE SIGNAL ;
    PORT
      LAYER M4 ;
        RECT  -0.042 38.16 0.042 38.184 ;
    END
  END vmq[33]
  PIN vmq[34]
    DIRECTION OUTPUT ;
    USE SIGNAL ;
    PORT
      LAYER M4 ;
        RECT  -0.042 38.256 0.042 38.28 ;
    END
  END vmq[34]
  PIN vmq[35]
    DIRECTION OUTPUT ;
    USE SIGNAL ;
    PORT
      LAYER M4 ;
        RECT  -0.042 38.352 0.042 38.376 ;
    END
  END vmq[35]
  PIN vmq[36]
    DIRECTION OUTPUT ;
    USE SIGNAL ;
    PORT
      LAYER M4 ;
        RECT  -0.042 38.448 0.042 38.472 ;
    END
  END vmq[36]
  PIN vmq[37]
    DIRECTION OUTPUT ;
    USE SIGNAL ;
    PORT
      LAYER M4 ;
        RECT  -0.042 38.544 0.042 38.568 ;
    END
  END vmq[37]
  PIN vmq[38]
    DIRECTION OUTPUT ;
    USE SIGNAL ;
    PORT
      LAYER M4 ;
        RECT  -0.042 38.64 0.042 38.664 ;
    END
  END vmq[38]
  PIN vmq[39]
    DIRECTION OUTPUT ;
    USE SIGNAL ;
    PORT
      LAYER M4 ;
        RECT  -0.042 38.736 0.042 38.76 ;
    END
  END vmq[39]
  PIN vmq[3]
    DIRECTION OUTPUT ;
    USE SIGNAL ;
    PORT
      LAYER M4 ;
        RECT  -0.042 35.28 0.042 35.304 ;
    END
  END vmq[3]
  PIN vmq[40]
    DIRECTION OUTPUT ;
    USE SIGNAL ;
    PORT
      LAYER M4 ;
        RECT  -0.042 38.832 0.042 38.856 ;
    END
  END vmq[40]
  PIN vmq[41]
    DIRECTION OUTPUT ;
    USE SIGNAL ;
    PORT
      LAYER M4 ;
        RECT  -0.042 38.928 0.042 38.952 ;
    END
  END vmq[41]
  PIN vmq[42]
    DIRECTION OUTPUT ;
    USE SIGNAL ;
    PORT
      LAYER M4 ;
        RECT  -0.042 39.024 0.042 39.048 ;
    END
  END vmq[42]
  PIN vmq[43]
    DIRECTION OUTPUT ;
    USE SIGNAL ;
    PORT
      LAYER M4 ;
        RECT  -0.042 39.12 0.042 39.144 ;
    END
  END vmq[43]
  PIN vmq[44]
    DIRECTION OUTPUT ;
    USE SIGNAL ;
    PORT
      LAYER M4 ;
        RECT  -0.042 39.216 0.042 39.24 ;
    END
  END vmq[44]
  PIN vmq[45]
    DIRECTION OUTPUT ;
    USE SIGNAL ;
    PORT
      LAYER M4 ;
        RECT  -0.042 39.312 0.042 39.336 ;
    END
  END vmq[45]
  PIN vmq[46]
    DIRECTION OUTPUT ;
    USE SIGNAL ;
    PORT
      LAYER M4 ;
        RECT  -0.042 39.408 0.042 39.432 ;
    END
  END vmq[46]
  PIN vmq[47]
    DIRECTION OUTPUT ;
    USE SIGNAL ;
    PORT
      LAYER M4 ;
        RECT  -0.042 39.504 0.042 39.528 ;
    END
  END vmq[47]
  PIN vmq[48]
    DIRECTION OUTPUT ;
    USE SIGNAL ;
    PORT
      LAYER M4 ;
        RECT  -0.042 39.6 0.042 39.624 ;
    END
  END vmq[48]
  PIN vmq[49]
    DIRECTION OUTPUT ;
    USE SIGNAL ;
    PORT
      LAYER M4 ;
        RECT  -0.042 39.696 0.042 39.72 ;
    END
  END vmq[49]
  PIN vmq[4]
    DIRECTION OUTPUT ;
    USE SIGNAL ;
    PORT
      LAYER M4 ;
        RECT  -0.042 35.376 0.042 35.4 ;
    END
  END vmq[4]
  PIN vmq[50]
    DIRECTION OUTPUT ;
    USE SIGNAL ;
    PORT
      LAYER M4 ;
        RECT  -0.042 39.792 0.042 39.816 ;
    END
  END vmq[50]
  PIN vmq[51]
    DIRECTION OUTPUT ;
    USE SIGNAL ;
    PORT
      LAYER M4 ;
        RECT  -0.042 39.888 0.042 39.912 ;
    END
  END vmq[51]
  PIN vmq[52]
    DIRECTION OUTPUT ;
    USE SIGNAL ;
    PORT
      LAYER M4 ;
        RECT  -0.042 39.984 0.042 40.008 ;
    END
  END vmq[52]
  PIN vmq[53]
    DIRECTION OUTPUT ;
    USE SIGNAL ;
    PORT
      LAYER M4 ;
        RECT  -0.042 40.08 0.042 40.104 ;
    END
  END vmq[53]
  PIN vmq[54]
    DIRECTION OUTPUT ;
    USE SIGNAL ;
    PORT
      LAYER M4 ;
        RECT  -0.042 40.176 0.042 40.2 ;
    END
  END vmq[54]
  PIN vmq[55]
    DIRECTION OUTPUT ;
    USE SIGNAL ;
    PORT
      LAYER M4 ;
        RECT  -0.042 40.272 0.042 40.296 ;
    END
  END vmq[55]
  PIN vmq[56]
    DIRECTION OUTPUT ;
    USE SIGNAL ;
    PORT
      LAYER M4 ;
        RECT  -0.042 40.368 0.042 40.392 ;
    END
  END vmq[56]
  PIN vmq[57]
    DIRECTION OUTPUT ;
    USE SIGNAL ;
    PORT
      LAYER M4 ;
        RECT  -0.042 40.464 0.042 40.488 ;
    END
  END vmq[57]
  PIN vmq[58]
    DIRECTION OUTPUT ;
    USE SIGNAL ;
    PORT
      LAYER M4 ;
        RECT  -0.042 40.56 0.042 40.584 ;
    END
  END vmq[58]
  PIN vmq[59]
    DIRECTION OUTPUT ;
    USE SIGNAL ;
    PORT
      LAYER M4 ;
        RECT  -0.042 40.656 0.042 40.68 ;
    END
  END vmq[59]
  PIN vmq[5]
    DIRECTION OUTPUT ;
    USE SIGNAL ;
    PORT
      LAYER M4 ;
        RECT  -0.042 35.472 0.042 35.496 ;
    END
  END vmq[5]
  PIN vmq[60]
    DIRECTION OUTPUT ;
    USE SIGNAL ;
    PORT
      LAYER M4 ;
        RECT  -0.042 40.752 0.042 40.776 ;
    END
  END vmq[60]
  PIN vmq[61]
    DIRECTION OUTPUT ;
    USE SIGNAL ;
    PORT
      LAYER M4 ;
        RECT  -0.042 40.848 0.042 40.872 ;
    END
  END vmq[61]
  PIN vmq[62]
    DIRECTION OUTPUT ;
    USE SIGNAL ;
    PORT
      LAYER M4 ;
        RECT  -0.042 40.944 0.042 40.968 ;
    END
  END vmq[62]
  PIN vmq[63]
    DIRECTION OUTPUT ;
    USE SIGNAL ;
    PORT
      LAYER M4 ;
        RECT  -0.042 41.04 0.042 41.064 ;
    END
  END vmq[63]
  PIN vmq[64]
    DIRECTION OUTPUT ;
    USE SIGNAL ;
    PORT
      LAYER M4 ;
        RECT  -0.042 41.136 0.042 41.16 ;
    END
  END vmq[64]
  PIN vmq[65]
    DIRECTION OUTPUT ;
    USE SIGNAL ;
    PORT
      LAYER M4 ;
        RECT  -0.042 41.232 0.042 41.256 ;
    END
  END vmq[65]
  PIN vmq[66]
    DIRECTION OUTPUT ;
    USE SIGNAL ;
    PORT
      LAYER M4 ;
        RECT  -0.042 41.328 0.042 41.352 ;
    END
  END vmq[66]
  PIN vmq[67]
    DIRECTION OUTPUT ;
    USE SIGNAL ;
    PORT
      LAYER M4 ;
        RECT  -0.042 41.424 0.042 41.448 ;
    END
  END vmq[67]
  PIN vmq[68]
    DIRECTION OUTPUT ;
    USE SIGNAL ;
    PORT
      LAYER M4 ;
        RECT  -0.042 41.52 0.042 41.544 ;
    END
  END vmq[68]
  PIN vmq[69]
    DIRECTION OUTPUT ;
    USE SIGNAL ;
    PORT
      LAYER M4 ;
        RECT  -0.042 41.616 0.042 41.64 ;
    END
  END vmq[69]
  PIN vmq[6]
    DIRECTION OUTPUT ;
    USE SIGNAL ;
    PORT
      LAYER M4 ;
        RECT  -0.042 35.568 0.042 35.592 ;
    END
  END vmq[6]
  PIN vmq[70]
    DIRECTION OUTPUT ;
    USE SIGNAL ;
    PORT
      LAYER M4 ;
        RECT  -0.042 41.712 0.042 41.736 ;
    END
  END vmq[70]
  PIN vmq[71]
    DIRECTION OUTPUT ;
    USE SIGNAL ;
    PORT
      LAYER M4 ;
        RECT  -0.042 41.808 0.042 41.832 ;
    END
  END vmq[71]
  PIN vmq[72]
    DIRECTION OUTPUT ;
    USE SIGNAL ;
    PORT
      LAYER M4 ;
        RECT  -0.042 41.904 0.042 41.928 ;
    END
  END vmq[72]
  PIN vmq[73]
    DIRECTION OUTPUT ;
    USE SIGNAL ;
    PORT
      LAYER M4 ;
        RECT  -0.042 42 0.042 42.024 ;
    END
  END vmq[73]
  PIN vmq[74]
    DIRECTION OUTPUT ;
    USE SIGNAL ;
    PORT
      LAYER M4 ;
        RECT  -0.042 42.096 0.042 42.12 ;
    END
  END vmq[74]
  PIN vmq[75]
    DIRECTION OUTPUT ;
    USE SIGNAL ;
    PORT
      LAYER M4 ;
        RECT  -0.042 42.192 0.042 42.216 ;
    END
  END vmq[75]
  PIN vmq[76]
    DIRECTION OUTPUT ;
    USE SIGNAL ;
    PORT
      LAYER M4 ;
        RECT  -0.042 42.288 0.042 42.312 ;
    END
  END vmq[76]
  PIN vmq[77]
    DIRECTION OUTPUT ;
    USE SIGNAL ;
    PORT
      LAYER M4 ;
        RECT  -0.042 42.384 0.042 42.408 ;
    END
  END vmq[77]
  PIN vmq[78]
    DIRECTION OUTPUT ;
    USE SIGNAL ;
    PORT
      LAYER M4 ;
        RECT  -0.042 42.48 0.042 42.504 ;
    END
  END vmq[78]
  PIN vmq[79]
    DIRECTION OUTPUT ;
    USE SIGNAL ;
    PORT
      LAYER M4 ;
        RECT  -0.042 42.576 0.042 42.6 ;
    END
  END vmq[79]
  PIN vmq[7]
    DIRECTION OUTPUT ;
    USE SIGNAL ;
    PORT
      LAYER M4 ;
        RECT  -0.042 35.664 0.042 35.688 ;
    END
  END vmq[7]
  PIN vmq[80]
    DIRECTION OUTPUT ;
    USE SIGNAL ;
    PORT
      LAYER M4 ;
        RECT  -0.042 42.672 0.042 42.696 ;
    END
  END vmq[80]
  PIN vmq[81]
    DIRECTION OUTPUT ;
    USE SIGNAL ;
    PORT
      LAYER M4 ;
        RECT  -0.042 42.768 0.042 42.792 ;
    END
  END vmq[81]
  PIN vmq[82]
    DIRECTION OUTPUT ;
    USE SIGNAL ;
    PORT
      LAYER M4 ;
        RECT  -0.042 42.864 0.042 42.888 ;
    END
  END vmq[82]
  PIN vmq[83]
    DIRECTION OUTPUT ;
    USE SIGNAL ;
    PORT
      LAYER M4 ;
        RECT  -0.042 42.96 0.042 42.984 ;
    END
  END vmq[83]
  PIN vmq[84]
    DIRECTION OUTPUT ;
    USE SIGNAL ;
    PORT
      LAYER M4 ;
        RECT  -0.042 43.056 0.042 43.08 ;
    END
  END vmq[84]
  PIN vmq[85]
    DIRECTION OUTPUT ;
    USE SIGNAL ;
    PORT
      LAYER M4 ;
        RECT  -0.042 43.152 0.042 43.176 ;
    END
  END vmq[85]
  PIN vmq[86]
    DIRECTION OUTPUT ;
    USE SIGNAL ;
    PORT
      LAYER M4 ;
        RECT  -0.042 43.248 0.042 43.272 ;
    END
  END vmq[86]
  PIN vmq[87]
    DIRECTION OUTPUT ;
    USE SIGNAL ;
    PORT
      LAYER M4 ;
        RECT  -0.042 43.344 0.042 43.368 ;
    END
  END vmq[87]
  PIN vmq[88]
    DIRECTION OUTPUT ;
    USE SIGNAL ;
    PORT
      LAYER M4 ;
        RECT  -0.042 43.44 0.042 43.464 ;
    END
  END vmq[88]
  PIN vmq[89]
    DIRECTION OUTPUT ;
    USE SIGNAL ;
    PORT
      LAYER M4 ;
        RECT  -0.042 43.536 0.042 43.56 ;
    END
  END vmq[89]
  PIN vmq[8]
    DIRECTION OUTPUT ;
    USE SIGNAL ;
    PORT
      LAYER M4 ;
        RECT  -0.042 35.76 0.042 35.784 ;
    END
  END vmq[8]
  PIN vmq[90]
    DIRECTION OUTPUT ;
    USE SIGNAL ;
    PORT
      LAYER M4 ;
        RECT  -0.042 43.632 0.042 43.656 ;
    END
  END vmq[90]
  PIN vmq[91]
    DIRECTION OUTPUT ;
    USE SIGNAL ;
    PORT
      LAYER M4 ;
        RECT  -0.042 43.728 0.042 43.752 ;
    END
  END vmq[91]
  PIN vmq[92]
    DIRECTION OUTPUT ;
    USE SIGNAL ;
    PORT
      LAYER M4 ;
        RECT  -0.042 43.824 0.042 43.848 ;
    END
  END vmq[92]
  PIN vmq[93]
    DIRECTION OUTPUT ;
    USE SIGNAL ;
    PORT
      LAYER M4 ;
        RECT  -0.042 43.92 0.042 43.944 ;
    END
  END vmq[93]
  PIN vmq[94]
    DIRECTION OUTPUT ;
    USE SIGNAL ;
    PORT
      LAYER M4 ;
        RECT  -0.042 44.016 0.042 44.04 ;
    END
  END vmq[94]
  PIN vmq[95]
    DIRECTION OUTPUT ;
    USE SIGNAL ;
    PORT
      LAYER M4 ;
        RECT  -0.042 44.112 0.042 44.136 ;
    END
  END vmq[95]
  PIN vmq[96]
    DIRECTION OUTPUT ;
    USE SIGNAL ;
    PORT
      LAYER M4 ;
        RECT  -0.042 44.208 0.042 44.232 ;
    END
  END vmq[96]
  PIN vmq[97]
    DIRECTION OUTPUT ;
    USE SIGNAL ;
    PORT
      LAYER M4 ;
        RECT  -0.042 44.304 0.042 44.328 ;
    END
  END vmq[97]
  PIN vmq[98]
    DIRECTION OUTPUT ;
    USE SIGNAL ;
    PORT
      LAYER M4 ;
        RECT  -0.042 44.4 0.042 44.424 ;
    END
  END vmq[98]
  PIN vmq[99]
    DIRECTION OUTPUT ;
    USE SIGNAL ;
    PORT
      LAYER M4 ;
        RECT  -0.042 44.496 0.042 44.52 ;
    END
  END vmq[99]
  PIN vmq[9]
    DIRECTION OUTPUT ;
    USE SIGNAL ;
    PORT
      LAYER M4 ;
        RECT  -0.042 35.856 0.042 35.88 ;
    END
  END vmq[9]
  PIN vmr[0]
    DIRECTION INPUT ;
    USE SIGNAL ;
    PORT
      LAYER M4 ;
        RECT  -0.042 4.32 0.042 4.344 ;
    END
  END vmr[0]
  PIN vmr[100]
    DIRECTION INPUT ;
    USE SIGNAL ;
    PORT
      LAYER M4 ;
        RECT  -0.042 13.92 0.042 13.944 ;
    END
  END vmr[100]
  PIN vmr[101]
    DIRECTION INPUT ;
    USE SIGNAL ;
    PORT
      LAYER M4 ;
        RECT  -0.042 14.016 0.042 14.04 ;
    END
  END vmr[101]
  PIN vmr[102]
    DIRECTION INPUT ;
    USE SIGNAL ;
    PORT
      LAYER M4 ;
        RECT  -0.042 14.112 0.042 14.136 ;
    END
  END vmr[102]
  PIN vmr[103]
    DIRECTION INPUT ;
    USE SIGNAL ;
    PORT
      LAYER M4 ;
        RECT  -0.042 14.208 0.042 14.232 ;
    END
  END vmr[103]
  PIN vmr[104]
    DIRECTION INPUT ;
    USE SIGNAL ;
    PORT
      LAYER M4 ;
        RECT  -0.042 14.304 0.042 14.328 ;
    END
  END vmr[104]
  PIN vmr[105]
    DIRECTION INPUT ;
    USE SIGNAL ;
    PORT
      LAYER M4 ;
        RECT  -0.042 14.4 0.042 14.424 ;
    END
  END vmr[105]
  PIN vmr[106]
    DIRECTION INPUT ;
    USE SIGNAL ;
    PORT
      LAYER M4 ;
        RECT  -0.042 14.496 0.042 14.52 ;
    END
  END vmr[106]
  PIN vmr[107]
    DIRECTION INPUT ;
    USE SIGNAL ;
    PORT
      LAYER M4 ;
        RECT  -0.042 14.592 0.042 14.616 ;
    END
  END vmr[107]
  PIN vmr[108]
    DIRECTION INPUT ;
    USE SIGNAL ;
    PORT
      LAYER M4 ;
        RECT  -0.042 14.688 0.042 14.712 ;
    END
  END vmr[108]
  PIN vmr[109]
    DIRECTION INPUT ;
    USE SIGNAL ;
    PORT
      LAYER M4 ;
        RECT  -0.042 14.784 0.042 14.808 ;
    END
  END vmr[109]
  PIN vmr[10]
    DIRECTION INPUT ;
    USE SIGNAL ;
    PORT
      LAYER M4 ;
        RECT  -0.042 5.28 0.042 5.304 ;
    END
  END vmr[10]
  PIN vmr[110]
    DIRECTION INPUT ;
    USE SIGNAL ;
    PORT
      LAYER M4 ;
        RECT  -0.042 14.88 0.042 14.904 ;
    END
  END vmr[110]
  PIN vmr[111]
    DIRECTION INPUT ;
    USE SIGNAL ;
    PORT
      LAYER M4 ;
        RECT  -0.042 14.976 0.042 15 ;
    END
  END vmr[111]
  PIN vmr[112]
    DIRECTION INPUT ;
    USE SIGNAL ;
    PORT
      LAYER M4 ;
        RECT  -0.042 15.072 0.042 15.096 ;
    END
  END vmr[112]
  PIN vmr[113]
    DIRECTION INPUT ;
    USE SIGNAL ;
    PORT
      LAYER M4 ;
        RECT  -0.042 15.168 0.042 15.192 ;
    END
  END vmr[113]
  PIN vmr[114]
    DIRECTION INPUT ;
    USE SIGNAL ;
    PORT
      LAYER M4 ;
        RECT  -0.042 15.264 0.042 15.288 ;
    END
  END vmr[114]
  PIN vmr[115]
    DIRECTION INPUT ;
    USE SIGNAL ;
    PORT
      LAYER M4 ;
        RECT  -0.042 15.36 0.042 15.384 ;
    END
  END vmr[115]
  PIN vmr[116]
    DIRECTION INPUT ;
    USE SIGNAL ;
    PORT
      LAYER M4 ;
        RECT  -0.042 15.456 0.042 15.48 ;
    END
  END vmr[116]
  PIN vmr[117]
    DIRECTION INPUT ;
    USE SIGNAL ;
    PORT
      LAYER M4 ;
        RECT  -0.042 15.552 0.042 15.576 ;
    END
  END vmr[117]
  PIN vmr[118]
    DIRECTION INPUT ;
    USE SIGNAL ;
    PORT
      LAYER M4 ;
        RECT  -0.042 15.648 0.042 15.672 ;
    END
  END vmr[118]
  PIN vmr[119]
    DIRECTION INPUT ;
    USE SIGNAL ;
    PORT
      LAYER M4 ;
        RECT  -0.042 15.744 0.042 15.768 ;
    END
  END vmr[119]
  PIN vmr[11]
    DIRECTION INPUT ;
    USE SIGNAL ;
    PORT
      LAYER M4 ;
        RECT  -0.042 5.376 0.042 5.4 ;
    END
  END vmr[11]
  PIN vmr[120]
    DIRECTION INPUT ;
    USE SIGNAL ;
    PORT
      LAYER M4 ;
        RECT  -0.042 15.84 0.042 15.864 ;
    END
  END vmr[120]
  PIN vmr[121]
    DIRECTION INPUT ;
    USE SIGNAL ;
    PORT
      LAYER M4 ;
        RECT  -0.042 15.936 0.042 15.96 ;
    END
  END vmr[121]
  PIN vmr[122]
    DIRECTION INPUT ;
    USE SIGNAL ;
    PORT
      LAYER M4 ;
        RECT  -0.042 16.032 0.042 16.056 ;
    END
  END vmr[122]
  PIN vmr[123]
    DIRECTION INPUT ;
    USE SIGNAL ;
    PORT
      LAYER M4 ;
        RECT  -0.042 16.128 0.042 16.152 ;
    END
  END vmr[123]
  PIN vmr[124]
    DIRECTION INPUT ;
    USE SIGNAL ;
    PORT
      LAYER M4 ;
        RECT  -0.042 16.224 0.042 16.248 ;
    END
  END vmr[124]
  PIN vmr[125]
    DIRECTION INPUT ;
    USE SIGNAL ;
    PORT
      LAYER M4 ;
        RECT  -0.042 16.32 0.042 16.344 ;
    END
  END vmr[125]
  PIN vmr[126]
    DIRECTION INPUT ;
    USE SIGNAL ;
    PORT
      LAYER M4 ;
        RECT  -0.042 16.416 0.042 16.44 ;
    END
  END vmr[126]
  PIN vmr[127]
    DIRECTION INPUT ;
    USE SIGNAL ;
    PORT
      LAYER M4 ;
        RECT  -0.042 16.512 0.042 16.536 ;
    END
  END vmr[127]
  PIN vmr[128]
    DIRECTION INPUT ;
    USE SIGNAL ;
    PORT
      LAYER M4 ;
        RECT  -0.042 16.608 0.042 16.632 ;
    END
  END vmr[128]
  PIN vmr[129]
    DIRECTION INPUT ;
    USE SIGNAL ;
    PORT
      LAYER M4 ;
        RECT  -0.042 16.704 0.042 16.728 ;
    END
  END vmr[129]
  PIN vmr[12]
    DIRECTION INPUT ;
    USE SIGNAL ;
    PORT
      LAYER M4 ;
        RECT  -0.042 5.472 0.042 5.496 ;
    END
  END vmr[12]
  PIN vmr[130]
    DIRECTION INPUT ;
    USE SIGNAL ;
    PORT
      LAYER M4 ;
        RECT  -0.042 16.8 0.042 16.824 ;
    END
  END vmr[130]
  PIN vmr[131]
    DIRECTION INPUT ;
    USE SIGNAL ;
    PORT
      LAYER M4 ;
        RECT  -0.042 16.896 0.042 16.92 ;
    END
  END vmr[131]
  PIN vmr[132]
    DIRECTION INPUT ;
    USE SIGNAL ;
    PORT
      LAYER M4 ;
        RECT  -0.042 16.992 0.042 17.016 ;
    END
  END vmr[132]
  PIN vmr[133]
    DIRECTION INPUT ;
    USE SIGNAL ;
    PORT
      LAYER M4 ;
        RECT  -0.042 17.088 0.042 17.112 ;
    END
  END vmr[133]
  PIN vmr[134]
    DIRECTION INPUT ;
    USE SIGNAL ;
    PORT
      LAYER M4 ;
        RECT  -0.042 17.184 0.042 17.208 ;
    END
  END vmr[134]
  PIN vmr[135]
    DIRECTION INPUT ;
    USE SIGNAL ;
    PORT
      LAYER M4 ;
        RECT  -0.042 17.28 0.042 17.304 ;
    END
  END vmr[135]
  PIN vmr[136]
    DIRECTION INPUT ;
    USE SIGNAL ;
    PORT
      LAYER M4 ;
        RECT  -0.042 17.376 0.042 17.4 ;
    END
  END vmr[136]
  PIN vmr[137]
    DIRECTION INPUT ;
    USE SIGNAL ;
    PORT
      LAYER M4 ;
        RECT  -0.042 17.472 0.042 17.496 ;
    END
  END vmr[137]
  PIN vmr[138]
    DIRECTION INPUT ;
    USE SIGNAL ;
    PORT
      LAYER M4 ;
        RECT  -0.042 17.568 0.042 17.592 ;
    END
  END vmr[138]
  PIN vmr[139]
    DIRECTION INPUT ;
    USE SIGNAL ;
    PORT
      LAYER M4 ;
        RECT  -0.042 17.664 0.042 17.688 ;
    END
  END vmr[139]
  PIN vmr[13]
    DIRECTION INPUT ;
    USE SIGNAL ;
    PORT
      LAYER M4 ;
        RECT  -0.042 5.568 0.042 5.592 ;
    END
  END vmr[13]
  PIN vmr[140]
    DIRECTION INPUT ;
    USE SIGNAL ;
    PORT
      LAYER M4 ;
        RECT  -0.042 17.76 0.042 17.784 ;
    END
  END vmr[140]
  PIN vmr[141]
    DIRECTION INPUT ;
    USE SIGNAL ;
    PORT
      LAYER M4 ;
        RECT  -0.042 17.856 0.042 17.88 ;
    END
  END vmr[141]
  PIN vmr[142]
    DIRECTION INPUT ;
    USE SIGNAL ;
    PORT
      LAYER M4 ;
        RECT  -0.042 17.952 0.042 17.976 ;
    END
  END vmr[142]
  PIN vmr[143]
    DIRECTION INPUT ;
    USE SIGNAL ;
    PORT
      LAYER M4 ;
        RECT  -0.042 18.048 0.042 18.072 ;
    END
  END vmr[143]
  PIN vmr[144]
    DIRECTION INPUT ;
    USE SIGNAL ;
    PORT
      LAYER M4 ;
        RECT  -0.042 18.144 0.042 18.168 ;
    END
  END vmr[144]
  PIN vmr[145]
    DIRECTION INPUT ;
    USE SIGNAL ;
    PORT
      LAYER M4 ;
        RECT  -0.042 18.24 0.042 18.264 ;
    END
  END vmr[145]
  PIN vmr[146]
    DIRECTION INPUT ;
    USE SIGNAL ;
    PORT
      LAYER M4 ;
        RECT  -0.042 18.336 0.042 18.36 ;
    END
  END vmr[146]
  PIN vmr[147]
    DIRECTION INPUT ;
    USE SIGNAL ;
    PORT
      LAYER M4 ;
        RECT  -0.042 18.432 0.042 18.456 ;
    END
  END vmr[147]
  PIN vmr[148]
    DIRECTION INPUT ;
    USE SIGNAL ;
    PORT
      LAYER M4 ;
        RECT  -0.042 18.528 0.042 18.552 ;
    END
  END vmr[148]
  PIN vmr[149]
    DIRECTION INPUT ;
    USE SIGNAL ;
    PORT
      LAYER M4 ;
        RECT  -0.042 18.624 0.042 18.648 ;
    END
  END vmr[149]
  PIN vmr[14]
    DIRECTION INPUT ;
    USE SIGNAL ;
    PORT
      LAYER M4 ;
        RECT  -0.042 5.664 0.042 5.688 ;
    END
  END vmr[14]
  PIN vmr[150]
    DIRECTION INPUT ;
    USE SIGNAL ;
    PORT
      LAYER M4 ;
        RECT  -0.042 18.72 0.042 18.744 ;
    END
  END vmr[150]
  PIN vmr[151]
    DIRECTION INPUT ;
    USE SIGNAL ;
    PORT
      LAYER M4 ;
        RECT  -0.042 18.816 0.042 18.84 ;
    END
  END vmr[151]
  PIN vmr[152]
    DIRECTION INPUT ;
    USE SIGNAL ;
    PORT
      LAYER M4 ;
        RECT  -0.042 18.912 0.042 18.936 ;
    END
  END vmr[152]
  PIN vmr[153]
    DIRECTION INPUT ;
    USE SIGNAL ;
    PORT
      LAYER M4 ;
        RECT  -0.042 19.008 0.042 19.032 ;
    END
  END vmr[153]
  PIN vmr[154]
    DIRECTION INPUT ;
    USE SIGNAL ;
    PORT
      LAYER M4 ;
        RECT  -0.042 19.104 0.042 19.128 ;
    END
  END vmr[154]
  PIN vmr[155]
    DIRECTION INPUT ;
    USE SIGNAL ;
    PORT
      LAYER M4 ;
        RECT  -0.042 19.2 0.042 19.224 ;
    END
  END vmr[155]
  PIN vmr[156]
    DIRECTION INPUT ;
    USE SIGNAL ;
    PORT
      LAYER M4 ;
        RECT  -0.042 19.296 0.042 19.32 ;
    END
  END vmr[156]
  PIN vmr[157]
    DIRECTION INPUT ;
    USE SIGNAL ;
    PORT
      LAYER M4 ;
        RECT  -0.042 19.392 0.042 19.416 ;
    END
  END vmr[157]
  PIN vmr[158]
    DIRECTION INPUT ;
    USE SIGNAL ;
    PORT
      LAYER M4 ;
        RECT  -0.042 19.488 0.042 19.512 ;
    END
  END vmr[158]
  PIN vmr[159]
    DIRECTION INPUT ;
    USE SIGNAL ;
    PORT
      LAYER M4 ;
        RECT  -0.042 19.584 0.042 19.608 ;
    END
  END vmr[159]
  PIN vmr[15]
    DIRECTION INPUT ;
    USE SIGNAL ;
    PORT
      LAYER M4 ;
        RECT  -0.042 5.76 0.042 5.784 ;
    END
  END vmr[15]
  PIN vmr[160]
    DIRECTION INPUT ;
    USE SIGNAL ;
    PORT
      LAYER M4 ;
        RECT  -0.042 19.68 0.042 19.704 ;
    END
  END vmr[160]
  PIN vmr[161]
    DIRECTION INPUT ;
    USE SIGNAL ;
    PORT
      LAYER M4 ;
        RECT  -0.042 19.776 0.042 19.8 ;
    END
  END vmr[161]
  PIN vmr[162]
    DIRECTION INPUT ;
    USE SIGNAL ;
    PORT
      LAYER M4 ;
        RECT  -0.042 19.872 0.042 19.896 ;
    END
  END vmr[162]
  PIN vmr[163]
    DIRECTION INPUT ;
    USE SIGNAL ;
    PORT
      LAYER M4 ;
        RECT  -0.042 19.968 0.042 19.992 ;
    END
  END vmr[163]
  PIN vmr[164]
    DIRECTION INPUT ;
    USE SIGNAL ;
    PORT
      LAYER M4 ;
        RECT  -0.042 20.064 0.042 20.088 ;
    END
  END vmr[164]
  PIN vmr[165]
    DIRECTION INPUT ;
    USE SIGNAL ;
    PORT
      LAYER M4 ;
        RECT  -0.042 20.16 0.042 20.184 ;
    END
  END vmr[165]
  PIN vmr[166]
    DIRECTION INPUT ;
    USE SIGNAL ;
    PORT
      LAYER M4 ;
        RECT  -0.042 20.256 0.042 20.28 ;
    END
  END vmr[166]
  PIN vmr[167]
    DIRECTION INPUT ;
    USE SIGNAL ;
    PORT
      LAYER M4 ;
        RECT  -0.042 20.352 0.042 20.376 ;
    END
  END vmr[167]
  PIN vmr[168]
    DIRECTION INPUT ;
    USE SIGNAL ;
    PORT
      LAYER M4 ;
        RECT  -0.042 20.448 0.042 20.472 ;
    END
  END vmr[168]
  PIN vmr[169]
    DIRECTION INPUT ;
    USE SIGNAL ;
    PORT
      LAYER M4 ;
        RECT  -0.042 20.544 0.042 20.568 ;
    END
  END vmr[169]
  PIN vmr[16]
    DIRECTION INPUT ;
    USE SIGNAL ;
    PORT
      LAYER M4 ;
        RECT  -0.042 5.856 0.042 5.88 ;
    END
  END vmr[16]
  PIN vmr[170]
    DIRECTION INPUT ;
    USE SIGNAL ;
    PORT
      LAYER M4 ;
        RECT  -0.042 20.64 0.042 20.664 ;
    END
  END vmr[170]
  PIN vmr[171]
    DIRECTION INPUT ;
    USE SIGNAL ;
    PORT
      LAYER M4 ;
        RECT  -0.042 20.736 0.042 20.76 ;
    END
  END vmr[171]
  PIN vmr[172]
    DIRECTION INPUT ;
    USE SIGNAL ;
    PORT
      LAYER M4 ;
        RECT  -0.042 20.832 0.042 20.856 ;
    END
  END vmr[172]
  PIN vmr[173]
    DIRECTION INPUT ;
    USE SIGNAL ;
    PORT
      LAYER M4 ;
        RECT  -0.042 20.928 0.042 20.952 ;
    END
  END vmr[173]
  PIN vmr[174]
    DIRECTION INPUT ;
    USE SIGNAL ;
    PORT
      LAYER M4 ;
        RECT  -0.042 21.024 0.042 21.048 ;
    END
  END vmr[174]
  PIN vmr[175]
    DIRECTION INPUT ;
    USE SIGNAL ;
    PORT
      LAYER M4 ;
        RECT  -0.042 21.12 0.042 21.144 ;
    END
  END vmr[175]
  PIN vmr[176]
    DIRECTION INPUT ;
    USE SIGNAL ;
    PORT
      LAYER M4 ;
        RECT  -0.042 21.216 0.042 21.24 ;
    END
  END vmr[176]
  PIN vmr[177]
    DIRECTION INPUT ;
    USE SIGNAL ;
    PORT
      LAYER M4 ;
        RECT  -0.042 21.312 0.042 21.336 ;
    END
  END vmr[177]
  PIN vmr[178]
    DIRECTION INPUT ;
    USE SIGNAL ;
    PORT
      LAYER M4 ;
        RECT  -0.042 21.408 0.042 21.432 ;
    END
  END vmr[178]
  PIN vmr[179]
    DIRECTION INPUT ;
    USE SIGNAL ;
    PORT
      LAYER M4 ;
        RECT  -0.042 21.504 0.042 21.528 ;
    END
  END vmr[179]
  PIN vmr[17]
    DIRECTION INPUT ;
    USE SIGNAL ;
    PORT
      LAYER M4 ;
        RECT  -0.042 5.952 0.042 5.976 ;
    END
  END vmr[17]
  PIN vmr[180]
    DIRECTION INPUT ;
    USE SIGNAL ;
    PORT
      LAYER M4 ;
        RECT  -0.042 21.6 0.042 21.624 ;
    END
  END vmr[180]
  PIN vmr[181]
    DIRECTION INPUT ;
    USE SIGNAL ;
    PORT
      LAYER M4 ;
        RECT  -0.042 21.696 0.042 21.72 ;
    END
  END vmr[181]
  PIN vmr[182]
    DIRECTION INPUT ;
    USE SIGNAL ;
    PORT
      LAYER M4 ;
        RECT  -0.042 21.792 0.042 21.816 ;
    END
  END vmr[182]
  PIN vmr[183]
    DIRECTION INPUT ;
    USE SIGNAL ;
    PORT
      LAYER M4 ;
        RECT  -0.042 21.888 0.042 21.912 ;
    END
  END vmr[183]
  PIN vmr[184]
    DIRECTION INPUT ;
    USE SIGNAL ;
    PORT
      LAYER M4 ;
        RECT  -0.042 21.984 0.042 22.008 ;
    END
  END vmr[184]
  PIN vmr[185]
    DIRECTION INPUT ;
    USE SIGNAL ;
    PORT
      LAYER M4 ;
        RECT  -0.042 22.08 0.042 22.104 ;
    END
  END vmr[185]
  PIN vmr[186]
    DIRECTION INPUT ;
    USE SIGNAL ;
    PORT
      LAYER M4 ;
        RECT  -0.042 22.176 0.042 22.2 ;
    END
  END vmr[186]
  PIN vmr[187]
    DIRECTION INPUT ;
    USE SIGNAL ;
    PORT
      LAYER M4 ;
        RECT  -0.042 22.272 0.042 22.296 ;
    END
  END vmr[187]
  PIN vmr[188]
    DIRECTION INPUT ;
    USE SIGNAL ;
    PORT
      LAYER M4 ;
        RECT  -0.042 22.368 0.042 22.392 ;
    END
  END vmr[188]
  PIN vmr[189]
    DIRECTION INPUT ;
    USE SIGNAL ;
    PORT
      LAYER M4 ;
        RECT  -0.042 22.464 0.042 22.488 ;
    END
  END vmr[189]
  PIN vmr[18]
    DIRECTION INPUT ;
    USE SIGNAL ;
    PORT
      LAYER M4 ;
        RECT  -0.042 6.048 0.042 6.072 ;
    END
  END vmr[18]
  PIN vmr[190]
    DIRECTION INPUT ;
    USE SIGNAL ;
    PORT
      LAYER M4 ;
        RECT  -0.042 22.56 0.042 22.584 ;
    END
  END vmr[190]
  PIN vmr[191]
    DIRECTION INPUT ;
    USE SIGNAL ;
    PORT
      LAYER M4 ;
        RECT  -0.042 22.656 0.042 22.68 ;
    END
  END vmr[191]
  PIN vmr[192]
    DIRECTION INPUT ;
    USE SIGNAL ;
    PORT
      LAYER M4 ;
        RECT  -0.042 22.752 0.042 22.776 ;
    END
  END vmr[192]
  PIN vmr[193]
    DIRECTION INPUT ;
    USE SIGNAL ;
    PORT
      LAYER M4 ;
        RECT  -0.042 22.848 0.042 22.872 ;
    END
  END vmr[193]
  PIN vmr[194]
    DIRECTION INPUT ;
    USE SIGNAL ;
    PORT
      LAYER M4 ;
        RECT  -0.042 22.944 0.042 22.968 ;
    END
  END vmr[194]
  PIN vmr[195]
    DIRECTION INPUT ;
    USE SIGNAL ;
    PORT
      LAYER M4 ;
        RECT  -0.042 23.04 0.042 23.064 ;
    END
  END vmr[195]
  PIN vmr[196]
    DIRECTION INPUT ;
    USE SIGNAL ;
    PORT
      LAYER M4 ;
        RECT  -0.042 23.136 0.042 23.16 ;
    END
  END vmr[196]
  PIN vmr[197]
    DIRECTION INPUT ;
    USE SIGNAL ;
    PORT
      LAYER M4 ;
        RECT  -0.042 23.232 0.042 23.256 ;
    END
  END vmr[197]
  PIN vmr[198]
    DIRECTION INPUT ;
    USE SIGNAL ;
    PORT
      LAYER M4 ;
        RECT  -0.042 23.328 0.042 23.352 ;
    END
  END vmr[198]
  PIN vmr[199]
    DIRECTION INPUT ;
    USE SIGNAL ;
    PORT
      LAYER M4 ;
        RECT  -0.042 23.424 0.042 23.448 ;
    END
  END vmr[199]
  PIN vmr[19]
    DIRECTION INPUT ;
    USE SIGNAL ;
    PORT
      LAYER M4 ;
        RECT  -0.042 6.144 0.042 6.168 ;
    END
  END vmr[19]
  PIN vmr[1]
    DIRECTION INPUT ;
    USE SIGNAL ;
    PORT
      LAYER M4 ;
        RECT  -0.042 4.416 0.042 4.44 ;
    END
  END vmr[1]
  PIN vmr[200]
    DIRECTION INPUT ;
    USE SIGNAL ;
    PORT
      LAYER M4 ;
        RECT  -0.042 23.52 0.042 23.544 ;
    END
  END vmr[200]
  PIN vmr[201]
    DIRECTION INPUT ;
    USE SIGNAL ;
    PORT
      LAYER M4 ;
        RECT  -0.042 23.616 0.042 23.64 ;
    END
  END vmr[201]
  PIN vmr[202]
    DIRECTION INPUT ;
    USE SIGNAL ;
    PORT
      LAYER M4 ;
        RECT  -0.042 23.712 0.042 23.736 ;
    END
  END vmr[202]
  PIN vmr[203]
    DIRECTION INPUT ;
    USE SIGNAL ;
    PORT
      LAYER M4 ;
        RECT  -0.042 23.808 0.042 23.832 ;
    END
  END vmr[203]
  PIN vmr[204]
    DIRECTION INPUT ;
    USE SIGNAL ;
    PORT
      LAYER M4 ;
        RECT  -0.042 23.904 0.042 23.928 ;
    END
  END vmr[204]
  PIN vmr[205]
    DIRECTION INPUT ;
    USE SIGNAL ;
    PORT
      LAYER M4 ;
        RECT  -0.042 24 0.042 24.024 ;
    END
  END vmr[205]
  PIN vmr[206]
    DIRECTION INPUT ;
    USE SIGNAL ;
    PORT
      LAYER M4 ;
        RECT  -0.042 24.096 0.042 24.12 ;
    END
  END vmr[206]
  PIN vmr[207]
    DIRECTION INPUT ;
    USE SIGNAL ;
    PORT
      LAYER M4 ;
        RECT  -0.042 24.192 0.042 24.216 ;
    END
  END vmr[207]
  PIN vmr[208]
    DIRECTION INPUT ;
    USE SIGNAL ;
    PORT
      LAYER M4 ;
        RECT  -0.042 24.288 0.042 24.312 ;
    END
  END vmr[208]
  PIN vmr[209]
    DIRECTION INPUT ;
    USE SIGNAL ;
    PORT
      LAYER M4 ;
        RECT  -0.042 24.384 0.042 24.408 ;
    END
  END vmr[209]
  PIN vmr[20]
    DIRECTION INPUT ;
    USE SIGNAL ;
    PORT
      LAYER M4 ;
        RECT  -0.042 6.24 0.042 6.264 ;
    END
  END vmr[20]
  PIN vmr[210]
    DIRECTION INPUT ;
    USE SIGNAL ;
    PORT
      LAYER M4 ;
        RECT  -0.042 24.48 0.042 24.504 ;
    END
  END vmr[210]
  PIN vmr[211]
    DIRECTION INPUT ;
    USE SIGNAL ;
    PORT
      LAYER M4 ;
        RECT  -0.042 24.576 0.042 24.6 ;
    END
  END vmr[211]
  PIN vmr[212]
    DIRECTION INPUT ;
    USE SIGNAL ;
    PORT
      LAYER M4 ;
        RECT  -0.042 24.672 0.042 24.696 ;
    END
  END vmr[212]
  PIN vmr[213]
    DIRECTION INPUT ;
    USE SIGNAL ;
    PORT
      LAYER M4 ;
        RECT  -0.042 24.768 0.042 24.792 ;
    END
  END vmr[213]
  PIN vmr[214]
    DIRECTION INPUT ;
    USE SIGNAL ;
    PORT
      LAYER M4 ;
        RECT  -0.042 24.864 0.042 24.888 ;
    END
  END vmr[214]
  PIN vmr[215]
    DIRECTION INPUT ;
    USE SIGNAL ;
    PORT
      LAYER M4 ;
        RECT  -0.042 24.96 0.042 24.984 ;
    END
  END vmr[215]
  PIN vmr[216]
    DIRECTION INPUT ;
    USE SIGNAL ;
    PORT
      LAYER M4 ;
        RECT  -0.042 25.056 0.042 25.08 ;
    END
  END vmr[216]
  PIN vmr[217]
    DIRECTION INPUT ;
    USE SIGNAL ;
    PORT
      LAYER M4 ;
        RECT  -0.042 25.152 0.042 25.176 ;
    END
  END vmr[217]
  PIN vmr[218]
    DIRECTION INPUT ;
    USE SIGNAL ;
    PORT
      LAYER M4 ;
        RECT  -0.042 25.248 0.042 25.272 ;
    END
  END vmr[218]
  PIN vmr[219]
    DIRECTION INPUT ;
    USE SIGNAL ;
    PORT
      LAYER M4 ;
        RECT  -0.042 25.344 0.042 25.368 ;
    END
  END vmr[219]
  PIN vmr[21]
    DIRECTION INPUT ;
    USE SIGNAL ;
    PORT
      LAYER M4 ;
        RECT  -0.042 6.336 0.042 6.36 ;
    END
  END vmr[21]
  PIN vmr[220]
    DIRECTION INPUT ;
    USE SIGNAL ;
    PORT
      LAYER M4 ;
        RECT  -0.042 25.44 0.042 25.464 ;
    END
  END vmr[220]
  PIN vmr[221]
    DIRECTION INPUT ;
    USE SIGNAL ;
    PORT
      LAYER M4 ;
        RECT  -0.042 25.536 0.042 25.56 ;
    END
  END vmr[221]
  PIN vmr[222]
    DIRECTION INPUT ;
    USE SIGNAL ;
    PORT
      LAYER M4 ;
        RECT  -0.042 25.632 0.042 25.656 ;
    END
  END vmr[222]
  PIN vmr[223]
    DIRECTION INPUT ;
    USE SIGNAL ;
    PORT
      LAYER M4 ;
        RECT  -0.042 25.728 0.042 25.752 ;
    END
  END vmr[223]
  PIN vmr[224]
    DIRECTION INPUT ;
    USE SIGNAL ;
    PORT
      LAYER M4 ;
        RECT  -0.042 25.824 0.042 25.848 ;
    END
  END vmr[224]
  PIN vmr[225]
    DIRECTION INPUT ;
    USE SIGNAL ;
    PORT
      LAYER M4 ;
        RECT  -0.042 25.92 0.042 25.944 ;
    END
  END vmr[225]
  PIN vmr[226]
    DIRECTION INPUT ;
    USE SIGNAL ;
    PORT
      LAYER M4 ;
        RECT  -0.042 26.016 0.042 26.04 ;
    END
  END vmr[226]
  PIN vmr[227]
    DIRECTION INPUT ;
    USE SIGNAL ;
    PORT
      LAYER M4 ;
        RECT  -0.042 26.112 0.042 26.136 ;
    END
  END vmr[227]
  PIN vmr[228]
    DIRECTION INPUT ;
    USE SIGNAL ;
    PORT
      LAYER M4 ;
        RECT  -0.042 26.208 0.042 26.232 ;
    END
  END vmr[228]
  PIN vmr[229]
    DIRECTION INPUT ;
    USE SIGNAL ;
    PORT
      LAYER M4 ;
        RECT  -0.042 26.304 0.042 26.328 ;
    END
  END vmr[229]
  PIN vmr[22]
    DIRECTION INPUT ;
    USE SIGNAL ;
    PORT
      LAYER M4 ;
        RECT  -0.042 6.432 0.042 6.456 ;
    END
  END vmr[22]
  PIN vmr[230]
    DIRECTION INPUT ;
    USE SIGNAL ;
    PORT
      LAYER M4 ;
        RECT  -0.042 26.4 0.042 26.424 ;
    END
  END vmr[230]
  PIN vmr[231]
    DIRECTION INPUT ;
    USE SIGNAL ;
    PORT
      LAYER M4 ;
        RECT  -0.042 26.496 0.042 26.52 ;
    END
  END vmr[231]
  PIN vmr[232]
    DIRECTION INPUT ;
    USE SIGNAL ;
    PORT
      LAYER M4 ;
        RECT  -0.042 26.592 0.042 26.616 ;
    END
  END vmr[232]
  PIN vmr[233]
    DIRECTION INPUT ;
    USE SIGNAL ;
    PORT
      LAYER M4 ;
        RECT  -0.042 26.688 0.042 26.712 ;
    END
  END vmr[233]
  PIN vmr[234]
    DIRECTION INPUT ;
    USE SIGNAL ;
    PORT
      LAYER M4 ;
        RECT  -0.042 26.784 0.042 26.808 ;
    END
  END vmr[234]
  PIN vmr[235]
    DIRECTION INPUT ;
    USE SIGNAL ;
    PORT
      LAYER M4 ;
        RECT  -0.042 26.88 0.042 26.904 ;
    END
  END vmr[235]
  PIN vmr[236]
    DIRECTION INPUT ;
    USE SIGNAL ;
    PORT
      LAYER M4 ;
        RECT  -0.042 26.976 0.042 27 ;
    END
  END vmr[236]
  PIN vmr[237]
    DIRECTION INPUT ;
    USE SIGNAL ;
    PORT
      LAYER M4 ;
        RECT  -0.042 27.072 0.042 27.096 ;
    END
  END vmr[237]
  PIN vmr[238]
    DIRECTION INPUT ;
    USE SIGNAL ;
    PORT
      LAYER M4 ;
        RECT  -0.042 27.168 0.042 27.192 ;
    END
  END vmr[238]
  PIN vmr[239]
    DIRECTION INPUT ;
    USE SIGNAL ;
    PORT
      LAYER M4 ;
        RECT  -0.042 27.264 0.042 27.288 ;
    END
  END vmr[239]
  PIN vmr[23]
    DIRECTION INPUT ;
    USE SIGNAL ;
    PORT
      LAYER M4 ;
        RECT  -0.042 6.528 0.042 6.552 ;
    END
  END vmr[23]
  PIN vmr[240]
    DIRECTION INPUT ;
    USE SIGNAL ;
    PORT
      LAYER M4 ;
        RECT  -0.042 27.36 0.042 27.384 ;
    END
  END vmr[240]
  PIN vmr[241]
    DIRECTION INPUT ;
    USE SIGNAL ;
    PORT
      LAYER M4 ;
        RECT  -0.042 27.456 0.042 27.48 ;
    END
  END vmr[241]
  PIN vmr[242]
    DIRECTION INPUT ;
    USE SIGNAL ;
    PORT
      LAYER M4 ;
        RECT  -0.042 27.552 0.042 27.576 ;
    END
  END vmr[242]
  PIN vmr[243]
    DIRECTION INPUT ;
    USE SIGNAL ;
    PORT
      LAYER M4 ;
        RECT  -0.042 27.648 0.042 27.672 ;
    END
  END vmr[243]
  PIN vmr[244]
    DIRECTION INPUT ;
    USE SIGNAL ;
    PORT
      LAYER M4 ;
        RECT  -0.042 27.744 0.042 27.768 ;
    END
  END vmr[244]
  PIN vmr[245]
    DIRECTION INPUT ;
    USE SIGNAL ;
    PORT
      LAYER M4 ;
        RECT  -0.042 27.84 0.042 27.864 ;
    END
  END vmr[245]
  PIN vmr[246]
    DIRECTION INPUT ;
    USE SIGNAL ;
    PORT
      LAYER M4 ;
        RECT  -0.042 27.936 0.042 27.96 ;
    END
  END vmr[246]
  PIN vmr[247]
    DIRECTION INPUT ;
    USE SIGNAL ;
    PORT
      LAYER M4 ;
        RECT  -0.042 28.032 0.042 28.056 ;
    END
  END vmr[247]
  PIN vmr[248]
    DIRECTION INPUT ;
    USE SIGNAL ;
    PORT
      LAYER M4 ;
        RECT  -0.042 28.128 0.042 28.152 ;
    END
  END vmr[248]
  PIN vmr[249]
    DIRECTION INPUT ;
    USE SIGNAL ;
    PORT
      LAYER M4 ;
        RECT  -0.042 28.224 0.042 28.248 ;
    END
  END vmr[249]
  PIN vmr[24]
    DIRECTION INPUT ;
    USE SIGNAL ;
    PORT
      LAYER M4 ;
        RECT  -0.042 6.624 0.042 6.648 ;
    END
  END vmr[24]
  PIN vmr[250]
    DIRECTION INPUT ;
    USE SIGNAL ;
    PORT
      LAYER M4 ;
        RECT  -0.042 28.32 0.042 28.344 ;
    END
  END vmr[250]
  PIN vmr[251]
    DIRECTION INPUT ;
    USE SIGNAL ;
    PORT
      LAYER M4 ;
        RECT  -0.042 28.416 0.042 28.44 ;
    END
  END vmr[251]
  PIN vmr[252]
    DIRECTION INPUT ;
    USE SIGNAL ;
    PORT
      LAYER M4 ;
        RECT  -0.042 28.512 0.042 28.536 ;
    END
  END vmr[252]
  PIN vmr[253]
    DIRECTION INPUT ;
    USE SIGNAL ;
    PORT
      LAYER M4 ;
        RECT  -0.042 28.608 0.042 28.632 ;
    END
  END vmr[253]
  PIN vmr[254]
    DIRECTION INPUT ;
    USE SIGNAL ;
    PORT
      LAYER M4 ;
        RECT  -0.042 28.704 0.042 28.728 ;
    END
  END vmr[254]
  PIN vmr[255]
    DIRECTION INPUT ;
    USE SIGNAL ;
    PORT
      LAYER M4 ;
        RECT  -0.042 28.8 0.042 28.824 ;
    END
  END vmr[255]
  PIN vmr[256]
    DIRECTION INPUT ;
    USE SIGNAL ;
    PORT
      LAYER M4 ;
        RECT  -0.042 73.536 0.042 73.56 ;
    END
  END vmr[256]
  PIN vmr[257]
    DIRECTION INPUT ;
    USE SIGNAL ;
    PORT
      LAYER M4 ;
        RECT  -0.042 28.992 0.042 29.016 ;
    END
  END vmr[257]
  PIN vmr[258]
    DIRECTION INPUT ;
    USE SIGNAL ;
    PORT
      LAYER M4 ;
        RECT  -0.042 29.088 0.042 29.112 ;
    END
  END vmr[258]
  PIN vmr[259]
    DIRECTION INPUT ;
    USE SIGNAL ;
    PORT
      LAYER M4 ;
        RECT  -0.042 29.184 0.042 29.208 ;
    END
  END vmr[259]
  PIN vmr[25]
    DIRECTION INPUT ;
    USE SIGNAL ;
    PORT
      LAYER M4 ;
        RECT  -0.042 6.72 0.042 6.744 ;
    END
  END vmr[25]
  PIN vmr[260]
    DIRECTION INPUT ;
    USE SIGNAL ;
    PORT
      LAYER M4 ;
        RECT  -0.042 29.28 0.042 29.304 ;
    END
  END vmr[260]
  PIN vmr[261]
    DIRECTION INPUT ;
    USE SIGNAL ;
    PORT
      LAYER M4 ;
        RECT  -0.042 29.376 0.042 29.4 ;
    END
  END vmr[261]
  PIN vmr[262]
    DIRECTION INPUT ;
    USE SIGNAL ;
    PORT
      LAYER M4 ;
        RECT  -0.042 29.472 0.042 29.496 ;
    END
  END vmr[262]
  PIN vmr[263]
    DIRECTION INPUT ;
    USE SIGNAL ;
    PORT
      LAYER M4 ;
        RECT  -0.042 29.568 0.042 29.592 ;
    END
  END vmr[263]
  PIN vmr[264]
    DIRECTION INPUT ;
    USE SIGNAL ;
    PORT
      LAYER M4 ;
        RECT  -0.042 29.664 0.042 29.688 ;
    END
  END vmr[264]
  PIN vmr[265]
    DIRECTION INPUT ;
    USE SIGNAL ;
    PORT
      LAYER M4 ;
        RECT  -0.042 29.76 0.042 29.784 ;
    END
  END vmr[265]
  PIN vmr[266]
    DIRECTION INPUT ;
    USE SIGNAL ;
    PORT
      LAYER M4 ;
        RECT  -0.042 29.856 0.042 29.88 ;
    END
  END vmr[266]
  PIN vmr[267]
    DIRECTION INPUT ;
    USE SIGNAL ;
    PORT
      LAYER M4 ;
        RECT  -0.042 29.952 0.042 29.976 ;
    END
  END vmr[267]
  PIN vmr[268]
    DIRECTION INPUT ;
    USE SIGNAL ;
    PORT
      LAYER M4 ;
        RECT  -0.042 30.048 0.042 30.072 ;
    END
  END vmr[268]
  PIN vmr[269]
    DIRECTION INPUT ;
    USE SIGNAL ;
    PORT
      LAYER M4 ;
        RECT  -0.042 30.144 0.042 30.168 ;
    END
  END vmr[269]
  PIN vmr[26]
    DIRECTION INPUT ;
    USE SIGNAL ;
    PORT
      LAYER M4 ;
        RECT  -0.042 6.816 0.042 6.84 ;
    END
  END vmr[26]
  PIN vmr[270]
    DIRECTION INPUT ;
    USE SIGNAL ;
    PORT
      LAYER M4 ;
        RECT  -0.042 30.24 0.042 30.264 ;
    END
  END vmr[270]
  PIN vmr[271]
    DIRECTION INPUT ;
    USE SIGNAL ;
    PORT
      LAYER M4 ;
        RECT  -0.042 30.336 0.042 30.36 ;
    END
  END vmr[271]
  PIN vmr[272]
    DIRECTION INPUT ;
    USE SIGNAL ;
    PORT
      LAYER M4 ;
        RECT  -0.042 30.432 0.042 30.456 ;
    END
  END vmr[272]
  PIN vmr[273]
    DIRECTION INPUT ;
    USE SIGNAL ;
    PORT
      LAYER M4 ;
        RECT  -0.042 73.44 0.042 73.464 ;
    END
  END vmr[273]
  PIN vmr[27]
    DIRECTION INPUT ;
    USE SIGNAL ;
    PORT
      LAYER M4 ;
        RECT  -0.042 6.912 0.042 6.936 ;
    END
  END vmr[27]
  PIN vmr[28]
    DIRECTION INPUT ;
    USE SIGNAL ;
    PORT
      LAYER M4 ;
        RECT  -0.042 7.008 0.042 7.032 ;
    END
  END vmr[28]
  PIN vmr[29]
    DIRECTION INPUT ;
    USE SIGNAL ;
    PORT
      LAYER M4 ;
        RECT  -0.042 7.104 0.042 7.128 ;
    END
  END vmr[29]
  PIN vmr[2]
    DIRECTION INPUT ;
    USE SIGNAL ;
    PORT
      LAYER M4 ;
        RECT  -0.042 4.512 0.042 4.536 ;
    END
  END vmr[2]
  PIN vmr[30]
    DIRECTION INPUT ;
    USE SIGNAL ;
    PORT
      LAYER M4 ;
        RECT  -0.042 7.2 0.042 7.224 ;
    END
  END vmr[30]
  PIN vmr[31]
    DIRECTION INPUT ;
    USE SIGNAL ;
    PORT
      LAYER M4 ;
        RECT  -0.042 7.296 0.042 7.32 ;
    END
  END vmr[31]
  PIN vmr[32]
    DIRECTION INPUT ;
    USE SIGNAL ;
    PORT
      LAYER M4 ;
        RECT  -0.042 7.392 0.042 7.416 ;
    END
  END vmr[32]
  PIN vmr[33]
    DIRECTION INPUT ;
    USE SIGNAL ;
    PORT
      LAYER M4 ;
        RECT  -0.042 7.488 0.042 7.512 ;
    END
  END vmr[33]
  PIN vmr[34]
    DIRECTION INPUT ;
    USE SIGNAL ;
    PORT
      LAYER M4 ;
        RECT  -0.042 7.584 0.042 7.608 ;
    END
  END vmr[34]
  PIN vmr[35]
    DIRECTION INPUT ;
    USE SIGNAL ;
    PORT
      LAYER M4 ;
        RECT  -0.042 7.68 0.042 7.704 ;
    END
  END vmr[35]
  PIN vmr[36]
    DIRECTION INPUT ;
    USE SIGNAL ;
    PORT
      LAYER M4 ;
        RECT  -0.042 7.776 0.042 7.8 ;
    END
  END vmr[36]
  PIN vmr[37]
    DIRECTION INPUT ;
    USE SIGNAL ;
    PORT
      LAYER M4 ;
        RECT  -0.042 7.872 0.042 7.896 ;
    END
  END vmr[37]
  PIN vmr[38]
    DIRECTION INPUT ;
    USE SIGNAL ;
    PORT
      LAYER M4 ;
        RECT  -0.042 7.968 0.042 7.992 ;
    END
  END vmr[38]
  PIN vmr[39]
    DIRECTION INPUT ;
    USE SIGNAL ;
    PORT
      LAYER M4 ;
        RECT  -0.042 8.064 0.042 8.088 ;
    END
  END vmr[39]
  PIN vmr[3]
    DIRECTION INPUT ;
    USE SIGNAL ;
    PORT
      LAYER M4 ;
        RECT  -0.042 4.608 0.042 4.632 ;
    END
  END vmr[3]
  PIN vmr[40]
    DIRECTION INPUT ;
    USE SIGNAL ;
    PORT
      LAYER M4 ;
        RECT  -0.042 8.16 0.042 8.184 ;
    END
  END vmr[40]
  PIN vmr[41]
    DIRECTION INPUT ;
    USE SIGNAL ;
    PORT
      LAYER M4 ;
        RECT  -0.042 8.256 0.042 8.28 ;
    END
  END vmr[41]
  PIN vmr[42]
    DIRECTION INPUT ;
    USE SIGNAL ;
    PORT
      LAYER M4 ;
        RECT  -0.042 8.352 0.042 8.376 ;
    END
  END vmr[42]
  PIN vmr[43]
    DIRECTION INPUT ;
    USE SIGNAL ;
    PORT
      LAYER M4 ;
        RECT  -0.042 8.448 0.042 8.472 ;
    END
  END vmr[43]
  PIN vmr[44]
    DIRECTION INPUT ;
    USE SIGNAL ;
    PORT
      LAYER M4 ;
        RECT  -0.042 8.544 0.042 8.568 ;
    END
  END vmr[44]
  PIN vmr[45]
    DIRECTION INPUT ;
    USE SIGNAL ;
    PORT
      LAYER M4 ;
        RECT  -0.042 8.64 0.042 8.664 ;
    END
  END vmr[45]
  PIN vmr[46]
    DIRECTION INPUT ;
    USE SIGNAL ;
    PORT
      LAYER M4 ;
        RECT  -0.042 8.736 0.042 8.76 ;
    END
  END vmr[46]
  PIN vmr[47]
    DIRECTION INPUT ;
    USE SIGNAL ;
    PORT
      LAYER M4 ;
        RECT  -0.042 8.832 0.042 8.856 ;
    END
  END vmr[47]
  PIN vmr[48]
    DIRECTION INPUT ;
    USE SIGNAL ;
    PORT
      LAYER M4 ;
        RECT  -0.042 8.928 0.042 8.952 ;
    END
  END vmr[48]
  PIN vmr[49]
    DIRECTION INPUT ;
    USE SIGNAL ;
    PORT
      LAYER M4 ;
        RECT  -0.042 9.024 0.042 9.048 ;
    END
  END vmr[49]
  PIN vmr[4]
    DIRECTION INPUT ;
    USE SIGNAL ;
    PORT
      LAYER M4 ;
        RECT  -0.042 4.704 0.042 4.728 ;
    END
  END vmr[4]
  PIN vmr[50]
    DIRECTION INPUT ;
    USE SIGNAL ;
    PORT
      LAYER M4 ;
        RECT  -0.042 9.12 0.042 9.144 ;
    END
  END vmr[50]
  PIN vmr[51]
    DIRECTION INPUT ;
    USE SIGNAL ;
    PORT
      LAYER M4 ;
        RECT  -0.042 9.216 0.042 9.24 ;
    END
  END vmr[51]
  PIN vmr[52]
    DIRECTION INPUT ;
    USE SIGNAL ;
    PORT
      LAYER M4 ;
        RECT  -0.042 9.312 0.042 9.336 ;
    END
  END vmr[52]
  PIN vmr[53]
    DIRECTION INPUT ;
    USE SIGNAL ;
    PORT
      LAYER M4 ;
        RECT  -0.042 9.408 0.042 9.432 ;
    END
  END vmr[53]
  PIN vmr[54]
    DIRECTION INPUT ;
    USE SIGNAL ;
    PORT
      LAYER M4 ;
        RECT  -0.042 9.504 0.042 9.528 ;
    END
  END vmr[54]
  PIN vmr[55]
    DIRECTION INPUT ;
    USE SIGNAL ;
    PORT
      LAYER M4 ;
        RECT  -0.042 9.6 0.042 9.624 ;
    END
  END vmr[55]
  PIN vmr[56]
    DIRECTION INPUT ;
    USE SIGNAL ;
    PORT
      LAYER M4 ;
        RECT  -0.042 9.696 0.042 9.72 ;
    END
  END vmr[56]
  PIN vmr[57]
    DIRECTION INPUT ;
    USE SIGNAL ;
    PORT
      LAYER M4 ;
        RECT  -0.042 9.792 0.042 9.816 ;
    END
  END vmr[57]
  PIN vmr[58]
    DIRECTION INPUT ;
    USE SIGNAL ;
    PORT
      LAYER M4 ;
        RECT  -0.042 9.888 0.042 9.912 ;
    END
  END vmr[58]
  PIN vmr[59]
    DIRECTION INPUT ;
    USE SIGNAL ;
    PORT
      LAYER M4 ;
        RECT  -0.042 9.984 0.042 10.008 ;
    END
  END vmr[59]
  PIN vmr[5]
    DIRECTION INPUT ;
    USE SIGNAL ;
    PORT
      LAYER M4 ;
        RECT  -0.042 4.8 0.042 4.824 ;
    END
  END vmr[5]
  PIN vmr[60]
    DIRECTION INPUT ;
    USE SIGNAL ;
    PORT
      LAYER M4 ;
        RECT  -0.042 10.08 0.042 10.104 ;
    END
  END vmr[60]
  PIN vmr[61]
    DIRECTION INPUT ;
    USE SIGNAL ;
    PORT
      LAYER M4 ;
        RECT  -0.042 10.176 0.042 10.2 ;
    END
  END vmr[61]
  PIN vmr[62]
    DIRECTION INPUT ;
    USE SIGNAL ;
    PORT
      LAYER M4 ;
        RECT  -0.042 10.272 0.042 10.296 ;
    END
  END vmr[62]
  PIN vmr[63]
    DIRECTION INPUT ;
    USE SIGNAL ;
    PORT
      LAYER M4 ;
        RECT  -0.042 10.368 0.042 10.392 ;
    END
  END vmr[63]
  PIN vmr[64]
    DIRECTION INPUT ;
    USE SIGNAL ;
    PORT
      LAYER M4 ;
        RECT  -0.042 10.464 0.042 10.488 ;
    END
  END vmr[64]
  PIN vmr[65]
    DIRECTION INPUT ;
    USE SIGNAL ;
    PORT
      LAYER M4 ;
        RECT  -0.042 10.56 0.042 10.584 ;
    END
  END vmr[65]
  PIN vmr[66]
    DIRECTION INPUT ;
    USE SIGNAL ;
    PORT
      LAYER M4 ;
        RECT  -0.042 10.656 0.042 10.68 ;
    END
  END vmr[66]
  PIN vmr[67]
    DIRECTION INPUT ;
    USE SIGNAL ;
    PORT
      LAYER M4 ;
        RECT  -0.042 10.752 0.042 10.776 ;
    END
  END vmr[67]
  PIN vmr[68]
    DIRECTION INPUT ;
    USE SIGNAL ;
    PORT
      LAYER M4 ;
        RECT  -0.042 10.848 0.042 10.872 ;
    END
  END vmr[68]
  PIN vmr[69]
    DIRECTION INPUT ;
    USE SIGNAL ;
    PORT
      LAYER M4 ;
        RECT  -0.042 10.944 0.042 10.968 ;
    END
  END vmr[69]
  PIN vmr[6]
    DIRECTION INPUT ;
    USE SIGNAL ;
    PORT
      LAYER M4 ;
        RECT  -0.042 4.896 0.042 4.92 ;
    END
  END vmr[6]
  PIN vmr[70]
    DIRECTION INPUT ;
    USE SIGNAL ;
    PORT
      LAYER M4 ;
        RECT  -0.042 11.04 0.042 11.064 ;
    END
  END vmr[70]
  PIN vmr[71]
    DIRECTION INPUT ;
    USE SIGNAL ;
    PORT
      LAYER M4 ;
        RECT  -0.042 11.136 0.042 11.16 ;
    END
  END vmr[71]
  PIN vmr[72]
    DIRECTION INPUT ;
    USE SIGNAL ;
    PORT
      LAYER M4 ;
        RECT  -0.042 11.232 0.042 11.256 ;
    END
  END vmr[72]
  PIN vmr[73]
    DIRECTION INPUT ;
    USE SIGNAL ;
    PORT
      LAYER M4 ;
        RECT  -0.042 11.328 0.042 11.352 ;
    END
  END vmr[73]
  PIN vmr[74]
    DIRECTION INPUT ;
    USE SIGNAL ;
    PORT
      LAYER M4 ;
        RECT  -0.042 11.424 0.042 11.448 ;
    END
  END vmr[74]
  PIN vmr[75]
    DIRECTION INPUT ;
    USE SIGNAL ;
    PORT
      LAYER M4 ;
        RECT  -0.042 11.52 0.042 11.544 ;
    END
  END vmr[75]
  PIN vmr[76]
    DIRECTION INPUT ;
    USE SIGNAL ;
    PORT
      LAYER M4 ;
        RECT  -0.042 11.616 0.042 11.64 ;
    END
  END vmr[76]
  PIN vmr[77]
    DIRECTION INPUT ;
    USE SIGNAL ;
    PORT
      LAYER M4 ;
        RECT  -0.042 11.712 0.042 11.736 ;
    END
  END vmr[77]
  PIN vmr[78]
    DIRECTION INPUT ;
    USE SIGNAL ;
    PORT
      LAYER M4 ;
        RECT  -0.042 11.808 0.042 11.832 ;
    END
  END vmr[78]
  PIN vmr[79]
    DIRECTION INPUT ;
    USE SIGNAL ;
    PORT
      LAYER M4 ;
        RECT  -0.042 11.904 0.042 11.928 ;
    END
  END vmr[79]
  PIN vmr[7]
    DIRECTION INPUT ;
    USE SIGNAL ;
    PORT
      LAYER M4 ;
        RECT  -0.042 4.992 0.042 5.016 ;
    END
  END vmr[7]
  PIN vmr[80]
    DIRECTION INPUT ;
    USE SIGNAL ;
    PORT
      LAYER M4 ;
        RECT  -0.042 12 0.042 12.024 ;
    END
  END vmr[80]
  PIN vmr[81]
    DIRECTION INPUT ;
    USE SIGNAL ;
    PORT
      LAYER M4 ;
        RECT  -0.042 12.096 0.042 12.12 ;
    END
  END vmr[81]
  PIN vmr[82]
    DIRECTION INPUT ;
    USE SIGNAL ;
    PORT
      LAYER M4 ;
        RECT  -0.042 12.192 0.042 12.216 ;
    END
  END vmr[82]
  PIN vmr[83]
    DIRECTION INPUT ;
    USE SIGNAL ;
    PORT
      LAYER M4 ;
        RECT  -0.042 12.288 0.042 12.312 ;
    END
  END vmr[83]
  PIN vmr[84]
    DIRECTION INPUT ;
    USE SIGNAL ;
    PORT
      LAYER M4 ;
        RECT  -0.042 12.384 0.042 12.408 ;
    END
  END vmr[84]
  PIN vmr[85]
    DIRECTION INPUT ;
    USE SIGNAL ;
    PORT
      LAYER M4 ;
        RECT  -0.042 12.48 0.042 12.504 ;
    END
  END vmr[85]
  PIN vmr[86]
    DIRECTION INPUT ;
    USE SIGNAL ;
    PORT
      LAYER M4 ;
        RECT  -0.042 12.576 0.042 12.6 ;
    END
  END vmr[86]
  PIN vmr[87]
    DIRECTION INPUT ;
    USE SIGNAL ;
    PORT
      LAYER M4 ;
        RECT  -0.042 12.672 0.042 12.696 ;
    END
  END vmr[87]
  PIN vmr[88]
    DIRECTION INPUT ;
    USE SIGNAL ;
    PORT
      LAYER M4 ;
        RECT  -0.042 12.768 0.042 12.792 ;
    END
  END vmr[88]
  PIN vmr[89]
    DIRECTION INPUT ;
    USE SIGNAL ;
    PORT
      LAYER M4 ;
        RECT  -0.042 12.864 0.042 12.888 ;
    END
  END vmr[89]
  PIN vmr[8]
    DIRECTION INPUT ;
    USE SIGNAL ;
    PORT
      LAYER M4 ;
        RECT  -0.042 5.088 0.042 5.112 ;
    END
  END vmr[8]
  PIN vmr[90]
    DIRECTION INPUT ;
    USE SIGNAL ;
    PORT
      LAYER M4 ;
        RECT  -0.042 12.96 0.042 12.984 ;
    END
  END vmr[90]
  PIN vmr[91]
    DIRECTION INPUT ;
    USE SIGNAL ;
    PORT
      LAYER M4 ;
        RECT  -0.042 13.056 0.042 13.08 ;
    END
  END vmr[91]
  PIN vmr[92]
    DIRECTION INPUT ;
    USE SIGNAL ;
    PORT
      LAYER M4 ;
        RECT  -0.042 13.152 0.042 13.176 ;
    END
  END vmr[92]
  PIN vmr[93]
    DIRECTION INPUT ;
    USE SIGNAL ;
    PORT
      LAYER M4 ;
        RECT  -0.042 13.248 0.042 13.272 ;
    END
  END vmr[93]
  PIN vmr[94]
    DIRECTION INPUT ;
    USE SIGNAL ;
    PORT
      LAYER M4 ;
        RECT  -0.042 13.344 0.042 13.368 ;
    END
  END vmr[94]
  PIN vmr[95]
    DIRECTION INPUT ;
    USE SIGNAL ;
    PORT
      LAYER M4 ;
        RECT  -0.042 13.44 0.042 13.464 ;
    END
  END vmr[95]
  PIN vmr[96]
    DIRECTION INPUT ;
    USE SIGNAL ;
    PORT
      LAYER M4 ;
        RECT  -0.042 13.536 0.042 13.56 ;
    END
  END vmr[96]
  PIN vmr[97]
    DIRECTION INPUT ;
    USE SIGNAL ;
    PORT
      LAYER M4 ;
        RECT  -0.042 13.632 0.042 13.656 ;
    END
  END vmr[97]
  PIN vmr[98]
    DIRECTION INPUT ;
    USE SIGNAL ;
    PORT
      LAYER M4 ;
        RECT  -0.042 13.728 0.042 13.752 ;
    END
  END vmr[98]
  PIN vmr[99]
    DIRECTION INPUT ;
    USE SIGNAL ;
    PORT
      LAYER M4 ;
        RECT  -0.042 13.824 0.042 13.848 ;
    END
  END vmr[99]
  PIN vmr[9]
    DIRECTION INPUT ;
    USE SIGNAL ;
    PORT
      LAYER M4 ;
        RECT  -0.042 5.184 0.042 5.208 ;
    END
  END vmr[9]
  PIN VDD
    DIRECTION INOUT ;
    USE POWER ;
    PORT
      LAYER M5 ;
        RECT  40.392 2.151 40.512 84.249 ;
        RECT  34.992 2.151 35.112 84.249 ;
        RECT  29.592 2.151 29.712 84.249 ;
        RECT  24.192 2.151 24.312 84.249 ;
        RECT  18.792 2.151 18.912 84.249 ;
        RECT  13.392 2.151 13.512 84.249 ;
        RECT  7.992 2.151 8.112 84.249 ;
        RECT  2.592 2.151 2.712 84.249 ;
    END
  END VDD
  PIN VSS
    DIRECTION INOUT ;
    USE GROUND ;
    PORT
      LAYER M5 ;
        RECT  40.2 2.137 40.32 84.263 ;
        RECT  34.8 2.137 34.92 84.263 ;
        RECT  29.4 2.137 29.52 84.263 ;
        RECT  24 2.137 24.12 84.263 ;
        RECT  18.6 2.137 18.72 84.263 ;
        RECT  13.2 2.137 13.32 84.263 ;
        RECT  7.8 2.137 7.92 84.263 ;
        RECT  2.4 2.137 2.52 84.263 ;
    END
  END VSS
  # OT_OBS_CLOSED layer=M5 d_um=1.536 added=44
  OBS
    LAYER RVTN ;
     RECT  2.16 2.16 41.04 2.295 ;
     RECT  2.16 2.565 41.04 2.835 ;
     RECT  2.16 3.105 41.04 3.375 ;
     RECT  2.16 3.645 41.04 3.915 ;
     RECT  2.16 4.185 41.04 4.455 ;
     RECT  2.16 4.725 41.04 4.995 ;
     RECT  2.16 5.265 41.04 5.535 ;
     RECT  2.16 5.805 41.04 6.075 ;
     RECT  2.16 6.345 41.04 6.615 ;
     RECT  2.16 6.885 41.04 7.155 ;
     RECT  2.16 7.425 41.04 7.695 ;
     RECT  2.16 7.965 41.04 8.235 ;
     RECT  2.16 8.505 41.04 8.775 ;
     RECT  2.16 9.045 41.04 9.315 ;
     RECT  2.16 9.585 41.04 9.855 ;
     RECT  2.16 10.125 41.04 10.395 ;
     RECT  2.16 10.665 41.04 10.935 ;
     RECT  2.16 11.205 41.04 11.475 ;
     RECT  2.16 11.745 41.04 12.015 ;
     RECT  2.16 12.285 41.04 12.555 ;
     RECT  2.16 12.825 41.04 13.095 ;
     RECT  2.16 13.365 41.04 13.635 ;
     RECT  2.16 13.905 41.04 14.175 ;
     RECT  2.16 14.445 41.04 14.715 ;
     RECT  2.16 14.985 41.04 15.255 ;
     RECT  2.16 15.525 41.04 15.795 ;
     RECT  2.16 16.065 41.04 16.335 ;
     RECT  2.16 16.605 41.04 16.875 ;
     RECT  2.16 17.145 41.04 17.415 ;
     RECT  2.16 17.685 41.04 17.955 ;
     RECT  2.16 18.225 41.04 18.495 ;
     RECT  2.16 18.765 41.04 19.035 ;
     RECT  2.16 19.305 41.04 19.575 ;
     RECT  2.16 19.845 41.04 20.115 ;
     RECT  2.16 20.385 41.04 20.655 ;
     RECT  2.16 20.925 41.04 21.195 ;
     RECT  2.16 21.465 41.04 21.735 ;
     RECT  2.16 22.005 41.04 22.275 ;
     RECT  2.16 22.545 41.04 22.815 ;
     RECT  2.16 23.085 41.04 23.355 ;
     RECT  2.16 23.625 41.04 23.895 ;
     RECT  2.16 24.165 41.04 24.435 ;
     RECT  2.16 24.705 41.04 24.975 ;
     RECT  2.16 25.245 41.04 25.515 ;
     RECT  2.16 25.785 41.04 26.055 ;
     RECT  2.16 26.325 41.04 26.595 ;
     RECT  2.16 26.865 41.04 27.135 ;
     RECT  2.16 27.405 41.04 27.675 ;
     RECT  2.16 27.945 41.04 28.215 ;
     RECT  2.16 28.485 41.04 28.755 ;
     RECT  2.16 29.025 41.04 29.295 ;
     RECT  2.16 29.565 41.04 29.835 ;
     RECT  2.16 30.105 41.04 30.375 ;
     RECT  2.16 30.645 41.04 30.915 ;
     RECT  2.16 31.185 41.04 31.455 ;
     RECT  2.16 31.725 41.04 31.995 ;
     RECT  2.16 32.265 41.04 32.535 ;
     RECT  2.16 32.805 41.04 33.075 ;
     RECT  2.16 33.345 41.04 33.615 ;
     RECT  2.16 33.885 41.04 34.155 ;
     RECT  2.16 34.425 41.04 34.695 ;
     RECT  2.16 34.965 41.04 35.235 ;
     RECT  2.16 35.505 41.04 35.775 ;
     RECT  2.16 36.045 41.04 36.315 ;
     RECT  2.16 36.585 41.04 36.855 ;
     RECT  2.16 37.125 41.04 37.395 ;
     RECT  2.16 37.665 41.04 37.935 ;
     RECT  2.16 38.205 41.04 38.475 ;
     RECT  2.16 38.745 41.04 39.015 ;
     RECT  2.16 39.285 41.04 39.555 ;
     RECT  2.16 39.825 41.04 40.095 ;
     RECT  2.16 40.365 41.04 40.635 ;
     RECT  2.16 40.905 41.04 41.175 ;
     RECT  2.16 41.445 41.04 41.715 ;
     RECT  2.16 41.985 41.04 42.255 ;
     RECT  2.16 42.525 41.04 42.795 ;
     RECT  2.16 43.065 41.04 43.335 ;
     RECT  2.16 43.605 41.04 43.875 ;
     RECT  2.16 44.145 41.04 44.415 ;
     RECT  2.16 44.685 41.04 44.955 ;
     RECT  2.16 45.225 41.04 45.495 ;
     RECT  2.16 45.765 41.04 46.035 ;
     RECT  2.16 46.305 41.04 46.575 ;
     RECT  2.16 46.845 41.04 47.115 ;
     RECT  2.16 47.385 41.04 47.655 ;
     RECT  2.16 47.925 41.04 48.195 ;
     RECT  2.16 48.465 41.04 48.735 ;
     RECT  2.16 49.005 41.04 49.275 ;
     RECT  2.16 49.545 41.04 49.815 ;
     RECT  2.16 50.085 41.04 50.355 ;
     RECT  2.16 50.625 41.04 50.895 ;
     RECT  2.16 51.165 41.04 51.435 ;
     RECT  2.16 51.705 41.04 51.975 ;
     RECT  2.16 52.245 41.04 52.515 ;
     RECT  2.16 52.785 41.04 53.055 ;
     RECT  2.16 53.325 41.04 53.595 ;
     RECT  2.16 53.865 41.04 54.135 ;
     RECT  2.16 54.405 41.04 54.675 ;
     RECT  2.16 54.945 41.04 55.215 ;
     RECT  2.16 55.485 41.04 55.755 ;
     RECT  2.16 56.025 41.04 56.295 ;
     RECT  2.16 56.565 41.04 56.835 ;
     RECT  2.16 57.105 41.04 57.375 ;
     RECT  2.16 57.645 41.04 57.915 ;
     RECT  2.16 58.185 41.04 58.455 ;
     RECT  2.16 58.725 41.04 58.995 ;
     RECT  2.16 59.265 41.04 59.535 ;
     RECT  2.16 59.805 41.04 60.075 ;
     RECT  2.16 60.345 41.04 60.615 ;
     RECT  2.16 60.885 41.04 61.155 ;
     RECT  2.16 61.425 41.04 61.695 ;
     RECT  2.16 61.965 41.04 62.235 ;
     RECT  2.16 62.505 41.04 62.775 ;
     RECT  2.16 63.045 41.04 63.315 ;
     RECT  2.16 63.585 41.04 63.855 ;
     RECT  2.16 64.125 41.04 64.395 ;
     RECT  2.16 64.665 41.04 64.935 ;
     RECT  2.16 65.205 41.04 65.475 ;
     RECT  2.16 65.745 41.04 66.015 ;
     RECT  2.16 66.285 41.04 66.555 ;
     RECT  2.16 66.825 41.04 67.095 ;
     RECT  2.16 67.365 41.04 67.635 ;
     RECT  2.16 67.905 41.04 68.175 ;
     RECT  2.16 68.445 41.04 68.715 ;
     RECT  2.16 68.985 41.04 69.255 ;
     RECT  2.16 69.525 41.04 69.795 ;
     RECT  2.16 70.065 41.04 70.335 ;
     RECT  2.16 70.605 41.04 70.875 ;
     RECT  2.16 71.145 41.04 71.415 ;
     RECT  2.16 71.685 41.04 71.955 ;
     RECT  2.16 72.225 41.04 72.495 ;
     RECT  2.16 72.765 41.04 73.035 ;
     RECT  2.16 73.305 41.04 73.575 ;
     RECT  2.16 73.845 41.04 74.115 ;
     RECT  2.16 74.385 41.04 74.655 ;
     RECT  2.16 74.925 41.04 75.195 ;
     RECT  2.16 75.465 41.04 75.735 ;
     RECT  2.16 76.005 41.04 76.275 ;
     RECT  2.16 76.545 41.04 76.815 ;
     RECT  2.16 77.085 41.04 77.355 ;
     RECT  2.16 77.625 41.04 77.895 ;
     RECT  2.16 78.165 41.04 78.435 ;
     RECT  2.16 78.705 41.04 78.975 ;
     RECT  2.16 79.245 41.04 79.515 ;
     RECT  2.16 79.785 41.04 80.055 ;
     RECT  2.16 80.325 41.04 80.595 ;
     RECT  2.16 80.865 41.04 81.135 ;
     RECT  2.16 81.405 41.04 81.675 ;
     RECT  2.16 81.945 41.04 82.215 ;
     RECT  2.16 82.485 41.04 82.755 ;
     RECT  2.16 83.025 41.04 83.295 ;
     RECT  2.16 83.565 41.04 83.835 ;
     RECT  2.16 84.105 41.04 84.24 ;
    LAYER RVTP ;
     RECT  2.16 2.295 41.04 2.565 ;
     RECT  2.16 2.835 41.04 3.105 ;
     RECT  2.16 3.375 41.04 3.645 ;
     RECT  2.16 3.915 41.04 4.185 ;
     RECT  2.16 4.455 41.04 4.725 ;
     RECT  2.16 4.995 41.04 5.265 ;
     RECT  2.16 5.535 41.04 5.805 ;
     RECT  2.16 6.075 41.04 6.345 ;
     RECT  2.16 6.615 41.04 6.885 ;
     RECT  2.16 7.155 41.04 7.425 ;
     RECT  2.16 7.695 41.04 7.965 ;
     RECT  2.16 8.235 41.04 8.505 ;
     RECT  2.16 8.775 41.04 9.045 ;
     RECT  2.16 9.315 41.04 9.585 ;
     RECT  2.16 9.855 41.04 10.125 ;
     RECT  2.16 10.395 41.04 10.665 ;
     RECT  2.16 10.935 41.04 11.205 ;
     RECT  2.16 11.475 41.04 11.745 ;
     RECT  2.16 12.015 41.04 12.285 ;
     RECT  2.16 12.555 41.04 12.825 ;
     RECT  2.16 13.095 41.04 13.365 ;
     RECT  2.16 13.635 41.04 13.905 ;
     RECT  2.16 14.175 41.04 14.445 ;
     RECT  2.16 14.715 41.04 14.985 ;
     RECT  2.16 15.255 41.04 15.525 ;
     RECT  2.16 15.795 41.04 16.065 ;
     RECT  2.16 16.335 41.04 16.605 ;
     RECT  2.16 16.875 41.04 17.145 ;
     RECT  2.16 17.415 41.04 17.685 ;
     RECT  2.16 17.955 41.04 18.225 ;
     RECT  2.16 18.495 41.04 18.765 ;
     RECT  2.16 19.035 41.04 19.305 ;
     RECT  2.16 19.575 41.04 19.845 ;
     RECT  2.16 20.115 41.04 20.385 ;
     RECT  2.16 20.655 41.04 20.925 ;
     RECT  2.16 21.195 41.04 21.465 ;
     RECT  2.16 21.735 41.04 22.005 ;
     RECT  2.16 22.275 41.04 22.545 ;
     RECT  2.16 22.815 41.04 23.085 ;
     RECT  2.16 23.355 41.04 23.625 ;
     RECT  2.16 23.895 41.04 24.165 ;
     RECT  2.16 24.435 41.04 24.705 ;
     RECT  2.16 24.975 41.04 25.245 ;
     RECT  2.16 25.515 41.04 25.785 ;
     RECT  2.16 26.055 41.04 26.325 ;
     RECT  2.16 26.595 41.04 26.865 ;
     RECT  2.16 27.135 41.04 27.405 ;
     RECT  2.16 27.675 41.04 27.945 ;
     RECT  2.16 28.215 41.04 28.485 ;
     RECT  2.16 28.755 41.04 29.025 ;
     RECT  2.16 29.295 41.04 29.565 ;
     RECT  2.16 29.835 41.04 30.105 ;
     RECT  2.16 30.375 41.04 30.645 ;
     RECT  2.16 30.915 41.04 31.185 ;
     RECT  2.16 31.455 41.04 31.725 ;
     RECT  2.16 31.995 41.04 32.265 ;
     RECT  2.16 32.535 41.04 32.805 ;
     RECT  2.16 33.075 41.04 33.345 ;
     RECT  2.16 33.615 41.04 33.885 ;
     RECT  2.16 34.155 41.04 34.425 ;
     RECT  2.16 34.695 41.04 34.965 ;
     RECT  2.16 35.235 41.04 35.505 ;
     RECT  2.16 35.775 41.04 36.045 ;
     RECT  2.16 36.315 41.04 36.585 ;
     RECT  2.16 36.855 41.04 37.125 ;
     RECT  2.16 37.395 41.04 37.665 ;
     RECT  2.16 37.935 41.04 38.205 ;
     RECT  2.16 38.475 41.04 38.745 ;
     RECT  2.16 39.015 41.04 39.285 ;
     RECT  2.16 39.555 41.04 39.825 ;
     RECT  2.16 40.095 41.04 40.365 ;
     RECT  2.16 40.635 41.04 40.905 ;
     RECT  2.16 41.175 41.04 41.445 ;
     RECT  2.16 41.715 41.04 41.985 ;
     RECT  2.16 42.255 41.04 42.525 ;
     RECT  2.16 42.795 41.04 43.065 ;
     RECT  2.16 43.335 41.04 43.605 ;
     RECT  2.16 43.875 41.04 44.145 ;
     RECT  2.16 44.415 41.04 44.685 ;
     RECT  2.16 44.955 41.04 45.225 ;
     RECT  2.16 45.495 41.04 45.765 ;
     RECT  2.16 46.035 41.04 46.305 ;
     RECT  2.16 46.575 41.04 46.845 ;
     RECT  2.16 47.115 41.04 47.385 ;
     RECT  2.16 47.655 41.04 47.925 ;
     RECT  2.16 48.195 41.04 48.465 ;
     RECT  2.16 48.735 41.04 49.005 ;
     RECT  2.16 49.275 41.04 49.545 ;
     RECT  2.16 49.815 41.04 50.085 ;
     RECT  2.16 50.355 41.04 50.625 ;
     RECT  2.16 50.895 41.04 51.165 ;
     RECT  2.16 51.435 41.04 51.705 ;
     RECT  2.16 51.975 41.04 52.245 ;
     RECT  2.16 52.515 41.04 52.785 ;
     RECT  2.16 53.055 41.04 53.325 ;
     RECT  2.16 53.595 41.04 53.865 ;
     RECT  2.16 54.135 41.04 54.405 ;
     RECT  2.16 54.675 41.04 54.945 ;
     RECT  2.16 55.215 41.04 55.485 ;
     RECT  2.16 55.755 41.04 56.025 ;
     RECT  2.16 56.295 41.04 56.565 ;
     RECT  2.16 56.835 41.04 57.105 ;
     RECT  2.16 57.375 41.04 57.645 ;
     RECT  2.16 57.915 41.04 58.185 ;
     RECT  2.16 58.455 41.04 58.725 ;
     RECT  2.16 58.995 41.04 59.265 ;
     RECT  2.16 59.535 41.04 59.805 ;
     RECT  2.16 60.075 41.04 60.345 ;
     RECT  2.16 60.615 41.04 60.885 ;
     RECT  2.16 61.155 41.04 61.425 ;
     RECT  2.16 61.695 41.04 61.965 ;
     RECT  2.16 62.235 41.04 62.505 ;
     RECT  2.16 62.775 41.04 63.045 ;
     RECT  2.16 63.315 41.04 63.585 ;
     RECT  2.16 63.855 41.04 64.125 ;
     RECT  2.16 64.395 41.04 64.665 ;
     RECT  2.16 64.935 41.04 65.205 ;
     RECT  2.16 65.475 41.04 65.745 ;
     RECT  2.16 66.015 41.04 66.285 ;
     RECT  2.16 66.555 41.04 66.825 ;
     RECT  2.16 67.095 41.04 67.365 ;
     RECT  2.16 67.635 41.04 67.905 ;
     RECT  2.16 68.175 41.04 68.445 ;
     RECT  2.16 68.715 41.04 68.985 ;
     RECT  2.16 69.255 41.04 69.525 ;
     RECT  2.16 69.795 41.04 70.065 ;
     RECT  2.16 70.335 41.04 70.605 ;
     RECT  2.16 70.875 41.04 71.145 ;
     RECT  2.16 71.415 41.04 71.685 ;
     RECT  2.16 71.955 41.04 72.225 ;
     RECT  2.16 72.495 41.04 72.765 ;
     RECT  2.16 73.035 41.04 73.305 ;
     RECT  2.16 73.575 41.04 73.845 ;
     RECT  2.16 74.115 41.04 74.385 ;
     RECT  2.16 74.655 41.04 74.925 ;
     RECT  2.16 75.195 41.04 75.465 ;
     RECT  2.16 75.735 41.04 76.005 ;
     RECT  2.16 76.275 41.04 76.545 ;
     RECT  2.16 76.815 41.04 77.085 ;
     RECT  2.16 77.355 41.04 77.625 ;
     RECT  2.16 77.895 41.04 78.165 ;
     RECT  2.16 78.435 41.04 78.705 ;
     RECT  2.16 78.975 41.04 79.245 ;
     RECT  2.16 79.515 41.04 79.785 ;
     RECT  2.16 80.055 41.04 80.325 ;
     RECT  2.16 80.595 41.04 80.865 ;
     RECT  2.16 81.135 41.04 81.405 ;
     RECT  2.16 81.675 41.04 81.945 ;
     RECT  2.16 82.215 41.04 82.485 ;
     RECT  2.16 82.755 41.04 83.025 ;
     RECT  2.16 83.295 41.04 83.565 ;
     RECT  2.16 83.835 41.04 84.105 ;
    LAYER M1 ;
     RECT  2.16 2.151 41.04 84.249 ;
    LAYER M2 ;
     RECT  0.031 31.806 0.067 31.824 ;
     RECT  0.031 45.27 0.067 45.288 ;
     RECT  0.031 64.566 0.067 64.584 ;
     RECT  0.067 31.806 0.103 32.454 ;
     RECT  0.031 41.22 0.131 41.364 ;
     RECT  0.031 43.416 0.131 44.064 ;
     RECT  0.031 51.606 0.131 52.2 ;
     RECT  0.031 53.136 0.131 53.154 ;
     RECT  0.031 56.376 0.131 56.394 ;
     RECT  0.031 58.194 0.131 59.094 ;
     RECT  0.031 59.976 0.131 60.264 ;
     RECT  0.131 58.194 0.167 58.644 ;
     RECT  0.139 34.056 0.175 34.074 ;
     RECT  0.131 41.22 0.239 41.238 ;
     RECT  0.067 45.27 0.239 45.369 ;
     RECT  0.031 50.634 0.239 50.652 ;
     RECT  0.131 52.182 0.239 52.2 ;
     RECT  0.167 58.194 0.239 58.599 ;
     RECT  0.239 45.27 0.275 45.288 ;
     RECT  0.067 54.648 0.275 54.666 ;
     RECT  0.139 63.486 0.275 63.504 ;
     RECT  0.239 58.194 0.347 58.212 ;
     RECT  0.067 68.616 0.859 68.634 ;
     RECT  0.067 37.674 1.147 37.692 ;
     RECT  0.175 34.056 1.399 34.452 ;
     RECT  1.399 34.056 1.435 34.722 ;
     RECT  1.147 37.674 1.615 38.124 ;
     RECT  0.175 39.186 1.615 39.204 ;
     RECT  1.615 37.674 1.651 39.699 ;
     RECT  1.651 37.44 1.687 39.699 ;
     RECT  0.103 31.806 1.723 33.066 ;
     RECT  1.435 33.93 1.723 34.722 ;
     RECT  0.535 36.288 1.723 36.306 ;
     RECT  1.687 37.368 1.723 39.699 ;
     RECT  1.687 44.424 1.723 44.442 ;
     RECT  1.147 48.978 1.723 48.996 ;
     RECT  0.067 64.476 1.723 64.584 ;
     RECT  0.031 67.266 1.723 67.284 ;
     RECT  0.571 70.416 1.723 70.434 ;
     RECT  1.723 31.806 1.759 34.722 ;
     RECT  1.723 35.748 1.759 40.284 ;
     RECT  1.723 41.148 1.759 41.166 ;
     RECT  1.723 45.738 1.759 45.756 ;
     RECT  1.723 47.286 1.759 48.114 ;
     RECT  1.723 48.978 1.759 49.194 ;
     RECT  1.723 50.634 1.759 50.652 ;
     RECT  1.723 51.408 1.759 51.426 ;
     RECT  1.723 52.326 1.759 53.424 ;
     RECT  1.723 54.306 1.759 59.364 ;
     RECT  1.723 60.786 1.759 61.488 ;
     RECT  1.723 62.316 1.759 62.334 ;
     RECT  1.723 64.206 1.759 64.584 ;
     RECT  1.723 65.682 1.759 65.934 ;
     RECT  1.723 66.762 1.759 67.284 ;
     RECT  1.759 45.738 1.795 45.954 ;
     RECT  1.759 46.746 1.795 48.114 ;
     RECT  1.759 50.634 1.795 59.526 ;
     RECT  1.759 60.588 1.795 62.424 ;
     RECT  1.759 63.216 1.795 64.854 ;
     RECT  1.759 65.682 1.795 67.554 ;
     RECT  0.859 68.616 1.795 68.904 ;
     RECT  1.831 42.156 1.867 42.174 ;
     RECT  1.867 42.066 1.903 42.174 ;
     RECT  1.759 48.978 1.903 49.572 ;
     RECT  1.795 50.4 1.903 59.526 ;
     RECT  1.795 45.738 1.939 48.114 ;
     RECT  1.903 48.978 1.939 59.526 ;
     RECT  1.759 31.806 1.975 40.284 ;
     RECT  1.903 42.066 2.155 42.444 ;
     RECT  1.723 43.236 2.155 44.604 ;
     RECT  1.975 31.662 2.16 40.284 ;
     RECT  1.759 41.076 2.16 41.166 ;
     RECT  2.155 42.066 2.16 44.604 ;
     RECT  1.939 45.738 2.16 59.526 ;
     RECT  1.795 60.426 2.16 62.424 ;
     RECT  1.795 63.216 2.16 68.904 ;
     RECT  1.723 70.416 2.16 70.56 ;
     RECT  1.723 73.08 2.16 73.098 ;
     RECT  1.723 78.606 2.16 78.624 ;
     RECT  2.16 2.151 41.04 84.249 ;
     RECT  41.04 32.706 41.603 36.27 ;
     RECT  41.04 44.352 41.603 55.17 ;
     RECT  41.603 35.982 41.639 36.27 ;
     RECT  41.603 44.352 41.927 53.28 ;
     RECT  41.04 37.872 42.143 43.29 ;
     RECT  41.927 44.352 42.143 47.61 ;
     RECT  41.04 30.042 42.179 31.752 ;
     RECT  42.143 38.106 42.179 43.29 ;
     RECT  41.927 48.402 42.179 53.28 ;
     RECT  41.603 54.036 42.179 55.17 ;
     RECT  41.04 56.538 42.179 56.556 ;
     RECT  41.04 68.346 42.179 68.364 ;
     RECT  41.603 32.706 42.215 35.19 ;
     RECT  42.179 42.426 42.215 43.29 ;
     RECT  42.179 48.402 42.215 51.498 ;
     RECT  42.179 54.882 42.215 55.17 ;
     RECT  42.215 48.402 43.007 49.77 ;
     RECT  42.143 46.386 43.015 47.61 ;
     RECT  43.007 48.402 43.015 48.42 ;
     RECT  42.215 50.94 43.015 51.498 ;
     RECT  42.215 54.882 43.015 54.9 ;
     RECT  43.015 46.386 43.043 48.42 ;
     RECT  42.215 32.706 43.051 34.92 ;
     RECT  41.639 35.982 43.051 36 ;
     RECT  42.179 38.142 43.051 41.634 ;
     RECT  42.215 42.426 43.051 43.02 ;
     RECT  43.015 54.882 43.051 55.089 ;
     RECT  43.051 35.982 43.079 41.634 ;
     RECT  42.143 44.352 43.079 45.45 ;
     RECT  43.043 47.592 43.079 48.42 ;
     RECT  43.007 49.212 43.079 49.77 ;
     RECT  42.179 52.758 43.079 53.28 ;
     RECT  43.015 50.706 43.087 51.498 ;
     RECT  43.079 39.222 43.115 41.634 ;
     RECT  43.079 44.892 43.115 45.45 ;
     RECT  43.043 46.386 43.115 46.836 ;
     RECT  43.087 50.634 43.115 51.498 ;
     RECT  43.079 52.794 43.115 53.28 ;
     RECT  42.179 30.042 43.151 31.14 ;
     RECT  43.051 32.166 43.151 34.92 ;
     RECT  43.079 35.982 43.151 38.466 ;
     RECT  43.115 39.222 43.151 40.428 ;
     RECT  43.115 41.382 43.151 41.4 ;
     RECT  43.051 42.426 43.151 43.524 ;
     RECT  43.079 47.592 43.151 47.844 ;
     RECT  43.115 51.408 43.151 51.498 ;
     RECT  43.115 52.794 43.151 52.812 ;
     RECT  42.179 54.036 43.151 54.054 ;
     RECT  43.051 54.882 43.151 55.134 ;
     RECT  43.115 50.634 43.187 50.652 ;
     RECT  43.151 51.408 43.187 51.426 ;
    LAYER M3 ;
     RECT  2.415 2.143 2.505 2.413 ;
     RECT  7.815 2.143 7.905 2.413 ;
     RECT  13.215 2.143 13.305 2.413 ;
     RECT  18.615 2.143 18.705 2.413 ;
     RECT  24.015 2.143 24.105 2.413 ;
     RECT  29.415 2.143 29.505 2.413 ;
     RECT  34.815 2.143 34.905 2.413 ;
     RECT  40.215 2.143 40.305 2.413 ;
     RECT  29.415 2.413 29.697 26.635 ;
     RECT  29.415 26.635 30.366 26.789 ;
     RECT  29.415 26.789 30.222 26.825 ;
     RECT  26.388 29.851 26.406 30.043 ;
     RECT  24.015 2.413 24.297 30.139 ;
     RECT  26.208 30.043 26.406 30.271 ;
     RECT  6.732 30.181 6.75 30.307 ;
     RECT  22.824 30.073 22.842 30.307 ;
     RECT  40.215 2.413 40.497 30.307 ;
     RECT  41.58 30.235 41.598 30.307 ;
     RECT  11.412 30.307 11.502 30.331 ;
     RECT  40.215 30.307 41.598 30.365 ;
     RECT  11.412 30.331 11.574 30.406 ;
     RECT  22.824 30.307 23.058 30.407 ;
     RECT  22.824 30.407 22.986 30.443 ;
     RECT  30.708 30.307 30.726 30.443 ;
     RECT  6.732 30.307 6.858 30.451 ;
     RECT  7.815 2.413 8.097 30.451 ;
     RECT  9.216 30.415 9.234 30.451 ;
     RECT  11.412 30.406 11.61 30.451 ;
     RECT  24.015 30.139 24.822 30.451 ;
     RECT  41.58 30.365 41.598 30.451 ;
     RECT  7.815 30.451 8.262 30.541 ;
     RECT  9.216 30.451 9.666 30.541 ;
     RECT  27.828 30.427 27.846 30.541 ;
     RECT  7.815 30.541 9.666 30.569 ;
     RECT  7.815 30.569 9.594 30.605 ;
     RECT  11.16 30.451 11.61 30.605 ;
     RECT  41.58 30.451 42.21 30.641 ;
     RECT  22.824 30.443 22.914 30.677 ;
     RECT  6.66 30.451 6.858 30.685 ;
     RECT  27.324 30.541 27.846 30.713 ;
     RECT  11.16 30.605 11.178 30.721 ;
     RECT  42.192 30.641 42.21 30.749 ;
     RECT  6.66 30.685 6.894 30.883 ;
     RECT  26.208 30.271 26.514 30.907 ;
     RECT  6.66 30.883 6.966 30.991 ;
     RECT  7.815 30.605 8.73 30.991 ;
     RECT  11.088 30.721 11.178 30.991 ;
     RECT  43.128 29.947 43.146 31.003 ;
     RECT  26.064 30.907 26.514 31.099 ;
     RECT  43.056 31.003 43.146 31.145 ;
     RECT  24.015 30.451 25.038 31.195 ;
     RECT  24.015 31.195 25.146 31.243 ;
     RECT  34.815 2.413 35.097 31.243 ;
     RECT  40.215 30.365 40.497 31.243 ;
     RECT  2.415 2.413 2.697 31.261 ;
     RECT  34.704 31.243 35.097 31.289 ;
     RECT  40.104 31.243 40.497 31.289 ;
     RECT  9.576 30.605 9.594 31.351 ;
     RECT  10.836 30.991 11.178 31.351 ;
     RECT  26.064 31.099 26.802 31.415 ;
     RECT  24.015 31.243 25.254 31.423 ;
     RECT  2.415 31.261 3.006 31.495 ;
     RECT  22.824 30.677 22.842 31.495 ;
     RECT  5.544 30.991 5.562 31.531 ;
     RECT  6.66 30.991 8.73 31.531 ;
     RECT  26.604 31.415 26.802 31.531 ;
     RECT  40.215 31.289 40.497 31.579 ;
     RECT  2.415 31.495 3.078 31.621 ;
     RECT  40.215 31.579 40.59 31.649 ;
     RECT  2.415 31.621 3.762 31.657 ;
     RECT  30.672 31.627 30.69 31.657 ;
     RECT  27.828 30.713 27.846 31.693 ;
     RECT  22.824 31.495 22.986 31.723 ;
     RECT  26.604 31.531 26.874 31.723 ;
     RECT  30.672 31.657 30.762 31.757 ;
     RECT  38.772 31.657 38.79 31.757 ;
     RECT  42.156 31.675 42.174 31.757 ;
     RECT  1.98 31.657 3.762 31.801 ;
     RECT  4.752 31.765 4.77 31.801 ;
     RECT  13.215 2.413 13.497 31.801 ;
     RECT  22.824 31.723 23.022 31.829 ;
     RECT  22.896 31.829 22.914 31.919 ;
     RECT  27.828 31.693 28.026 31.919 ;
     RECT  27.828 31.919 27.846 31.955 ;
     RECT  43.056 31.145 43.074 32.152 ;
     RECT  26.604 31.723 26.982 32.233 ;
     RECT  35.928 32.197 35.946 32.237 ;
     RECT  30.708 31.757 30.762 32.333 ;
     RECT  43.056 32.152 43.146 32.369 ;
     RECT  0.036 31.801 0.054 32.431 ;
     RECT  34.815 31.289 35.097 32.431 ;
     RECT  34.704 32.431 35.097 32.477 ;
     RECT  14.796 32.341 14.814 32.495 ;
     RECT  36.468 32.251 36.486 32.495 ;
     RECT  26.604 32.233 27.378 32.731 ;
     RECT  26.604 32.731 27.846 32.827 ;
     RECT  5.544 31.531 8.73 32.845 ;
     RECT  9.576 31.351 11.178 32.845 ;
     RECT  24.015 31.423 25.542 32.845 ;
     RECT  26.604 32.827 28.134 32.845 ;
     RECT  12.6 31.801 13.497 32.971 ;
     RECT  42.156 32.635 42.174 32.999 ;
     RECT  0.036 32.431 0.09 33.043 ;
     RECT  30.708 32.333 30.726 33.071 ;
     RECT  5.544 32.845 11.178 33.079 ;
     RECT  12.204 32.971 13.497 33.079 ;
     RECT  43.128 32.369 43.146 33.211 ;
     RECT  1.98 31.801 4.77 33.269 ;
     RECT  24.015 32.845 28.134 33.305 ;
     RECT  43.092 33.211 43.146 33.307 ;
     RECT  1.98 33.269 4.698 33.313 ;
     RECT  14.724 33.313 14.742 33.349 ;
     RECT  1.764 33.313 4.698 33.385 ;
     RECT  14.652 33.349 14.742 33.385 ;
     RECT  34.815 32.477 35.097 33.403 ;
     RECT  22.86 33.385 22.878 33.421 ;
     RECT  14.652 33.385 14.814 33.449 ;
     RECT  34.704 33.403 35.097 33.449 ;
     RECT  14.796 33.449 14.814 33.539 ;
     RECT  22.86 33.421 22.95 33.575 ;
     RECT  22.86 33.575 22.914 33.619 ;
     RECT  22.824 33.619 22.914 33.719 ;
     RECT  22.896 33.719 22.914 33.809 ;
     RECT  41.58 33.787 41.598 33.883 ;
     RECT  1.728 33.385 4.698 33.925 ;
     RECT  0.036 33.043 0.126 34.051 ;
     RECT  24.015 33.305 25.866 34.075 ;
     RECT  26.604 33.305 28.134 34.075 ;
     RECT  30.708 34.051 30.726 34.151 ;
     RECT  1.44 33.925 4.698 34.159 ;
     RECT  5.544 33.079 13.497 34.159 ;
     RECT  41.58 33.883 42.174 34.171 ;
     RECT  41.544 34.171 42.174 34.349 ;
     RECT  14.724 34.321 14.742 34.357 ;
     RECT  24.015 34.075 28.134 34.385 ;
     RECT  0.036 34.051 0.162 34.429 ;
     RECT  26.604 34.385 28.134 34.493 ;
     RECT  30.744 34.321 30.762 34.591 ;
     RECT  36.468 34.363 36.486 34.603 ;
     RECT  40.215 31.649 40.497 34.603 ;
     RECT  27.72 34.493 28.134 34.627 ;
     RECT  14.724 34.357 14.814 34.655 ;
     RECT  1.44 34.159 13.497 34.663 ;
     RECT  14.796 34.655 14.814 34.691 ;
     RECT  1.44 34.663 13.626 34.699 ;
     RECT  43.056 33.307 43.146 34.733 ;
     RECT  30.744 34.591 30.798 34.771 ;
     RECT  40.104 34.603 40.497 34.861 ;
     RECT  30.744 34.771 30.87 34.897 ;
     RECT  43.128 34.733 43.146 34.925 ;
     RECT  15.732 34.861 15.75 34.933 ;
     RECT  39.924 34.861 40.497 34.973 ;
     RECT  30.708 34.897 30.87 35.033 ;
     RECT  15.732 34.933 15.786 35.041 ;
     RECT  36.432 34.603 36.486 35.069 ;
     RECT  34.815 33.449 35.097 35.125 ;
     RECT  15.732 35.041 15.858 35.159 ;
     RECT  34.704 35.125 35.097 35.165 ;
     RECT  26.604 34.493 26.874 35.227 ;
     RECT  27.72 34.627 28.53 35.227 ;
     RECT  42.192 34.501 42.21 35.227 ;
     RECT  26.604 35.227 28.53 35.303 ;
     RECT  1.404 34.699 13.626 35.311 ;
     RECT  27.972 35.303 28.53 35.311 ;
     RECT  29.415 26.825 29.697 35.311 ;
     RECT  40.215 34.973 40.497 35.323 ;
     RECT  24.015 34.385 25.866 35.339 ;
     RECT  30.708 35.033 30.798 35.437 ;
     RECT  41.58 35.227 42.21 35.453 ;
     RECT  26.604 35.303 27.162 35.465 ;
     RECT  30.672 35.437 30.798 35.473 ;
     RECT  26.712 35.465 27.162 35.501 ;
     RECT  41.58 35.453 41.598 35.501 ;
     RECT  30.6 35.473 30.798 35.549 ;
     RECT  30.672 35.549 30.798 35.573 ;
     RECT  42.948 35.611 42.966 35.707 ;
     RECT  42.948 35.707 43.146 35.899 ;
     RECT  15.732 35.159 15.75 35.941 ;
     RECT  35.892 35.515 35.91 35.969 ;
     RECT  42.912 35.899 43.146 36.029 ;
     RECT  1.404 35.311 13.914 36.049 ;
     RECT  15.66 35.941 15.75 36.049 ;
     RECT  22.896 35.977 22.914 36.049 ;
     RECT  30.708 35.573 30.798 36.049 ;
     RECT  40.215 35.323 40.59 36.049 ;
     RECT  0.036 34.429 0.198 36.077 ;
     RECT  22.824 36.049 22.914 36.077 ;
     RECT  15.588 36.049 15.75 36.085 ;
     RECT  39.24 35.995 39.258 36.091 ;
     RECT  30.708 36.049 30.87 36.113 ;
     RECT  1.404 36.049 14.13 36.121 ;
     RECT  14.904 36.085 15.75 36.121 ;
     RECT  26.784 35.501 27.162 36.121 ;
     RECT  27.972 35.311 29.697 36.121 ;
     RECT  43.02 36.029 43.146 36.125 ;
     RECT  39.24 36.091 39.294 36.211 ;
     RECT  40.215 36.049 41.058 36.211 ;
     RECT  39.24 36.211 41.058 36.221 ;
     RECT  22.824 36.077 22.842 36.239 ;
     RECT  26.784 36.121 29.697 36.239 ;
     RECT  39.24 36.221 40.497 36.269 ;
     RECT  0.072 36.077 0.198 36.283 ;
     RECT  1.404 36.121 15.75 36.311 ;
     RECT  26.856 36.239 28.674 36.311 ;
     RECT  41.616 36.247 41.634 36.317 ;
     RECT  39.24 36.269 39.294 36.347 ;
     RECT  15.552 36.311 15.75 36.383 ;
     RECT  39.24 36.347 39.258 36.383 ;
     RECT  30.744 36.113 30.87 36.413 ;
     RECT  26.856 36.311 28.494 36.419 ;
     RECT  30.852 36.413 30.87 36.419 ;
     RECT  25.848 35.339 25.866 36.523 ;
     RECT  0.072 36.283 0.558 36.557 ;
     RECT  25.848 36.523 25.974 36.571 ;
     RECT  34.815 35.165 35.097 36.751 ;
     RECT  25.848 36.571 26.118 36.763 ;
     RECT  25.74 36.763 26.118 36.811 ;
     RECT  1.404 36.311 14.742 36.851 ;
     RECT  24.015 35.339 24.678 36.859 ;
     RECT  25.632 36.811 26.118 36.859 ;
     RECT  1.404 36.851 14.13 37.037 ;
     RECT  26.964 36.419 27.234 37.049 ;
     RECT  28.44 36.419 28.494 37.147 ;
     RECT  40.215 36.269 40.497 37.285 ;
     RECT  24.015 36.859 26.118 37.291 ;
     RECT  26.964 37.049 27.162 37.291 ;
     RECT  34.704 36.751 35.097 37.325 ;
     RECT  40.104 37.285 40.497 37.325 ;
     RECT  0.108 36.557 0.558 37.669 ;
     RECT  42.156 37.723 42.174 37.819 ;
     RECT  1.656 37.037 14.13 37.831 ;
     RECT  14.904 37.741 14.922 37.831 ;
     RECT  42.12 37.819 42.174 37.895 ;
     RECT  24.015 37.291 27.162 37.939 ;
     RECT  28.008 37.147 28.494 37.939 ;
     RECT  24.015 37.939 28.494 38.011 ;
     RECT  29.415 36.239 29.697 38.011 ;
     RECT  38.16 37.915 38.178 38.039 ;
     RECT  0.072 37.669 0.558 38.101 ;
     RECT  1.656 37.831 14.922 38.101 ;
     RECT  30.924 37.939 30.942 38.101 ;
     RECT  42.156 37.895 42.174 38.129 ;
     RECT  40.215 37.325 40.497 38.155 ;
     RECT  22.824 37.975 22.842 38.201 ;
     RECT  30.852 38.101 30.942 38.201 ;
     RECT  39.888 38.155 40.497 38.201 ;
     RECT  24.015 38.011 29.697 38.273 ;
     RECT  0.072 38.101 14.922 38.371 ;
     RECT  15.732 36.383 15.75 38.371 ;
     RECT  22.86 38.245 22.878 38.371 ;
     RECT  22.86 38.371 22.95 38.399 ;
     RECT  28.008 38.273 29.697 38.491 ;
     RECT  22.932 38.399 22.95 38.507 ;
     RECT  43.056 36.125 43.146 38.587 ;
     RECT  28.008 38.491 29.79 38.705 ;
     RECT  43.02 38.587 43.146 38.765 ;
     RECT  0.072 38.371 15.75 38.821 ;
     RECT  17.136 38.779 17.154 38.911 ;
     RECT  36.612 38.911 36.63 38.923 ;
     RECT  40.104 38.201 40.497 38.957 ;
     RECT  36.468 38.923 36.63 38.975 ;
     RECT  0.072 38.821 16.254 38.983 ;
     RECT  36.612 38.975 36.63 39.005 ;
     RECT  17.136 38.911 17.478 39.011 ;
     RECT  39.312 38.971 39.33 39.011 ;
     RECT  28.872 38.705 29.79 39.019 ;
     RECT  41.616 38.641 41.634 39.067 ;
     RECT  28.872 39.019 29.934 39.119 ;
     RECT  41.616 39.067 42.174 39.163 ;
     RECT  41.58 39.163 42.174 39.181 ;
     RECT  28.872 39.119 29.79 39.209 ;
     RECT  30.78 39.181 30.798 39.217 ;
     RECT  37.62 39.181 37.638 39.245 ;
     RECT  41.508 39.181 42.174 39.245 ;
     RECT  28.944 39.209 29.79 39.281 ;
     RECT  0.072 38.983 16.398 39.289 ;
     RECT  17.136 39.011 17.154 39.289 ;
     RECT  30.78 39.217 30.87 39.325 ;
     RECT  0.072 39.289 17.154 39.353 ;
     RECT  41.58 39.245 42.174 39.353 ;
     RECT  18.615 2.413 18.897 39.403 ;
     RECT  19.62 39.361 19.71 39.403 ;
     RECT  0.072 39.353 9.378 39.437 ;
     RECT  34.815 37.325 35.097 39.487 ;
     RECT  30.78 39.325 31.158 39.559 ;
     RECT  43.092 38.765 43.146 39.595 ;
     RECT  18.615 39.403 19.71 39.631 ;
     RECT  30.78 39.559 31.266 39.631 ;
     RECT  42.984 39.595 43.146 39.643 ;
     RECT  30.636 39.631 31.266 39.721 ;
     RECT  30.636 39.721 31.626 39.757 ;
     RECT  10.116 39.353 17.154 39.787 ;
     RECT  39.096 39.595 39.294 39.787 ;
     RECT  39.024 39.787 39.294 39.821 ;
     RECT  42.912 39.643 43.146 39.821 ;
     RECT  36.648 39.739 36.666 39.835 ;
     RECT  34.74 39.487 35.097 39.857 ;
     RECT  42.984 39.821 43.146 39.857 ;
     RECT  18.36 39.631 19.854 39.865 ;
     RECT  39.024 39.821 39.222 39.869 ;
     RECT  43.02 39.857 43.146 39.869 ;
     RECT  30.636 39.757 31.698 39.893 ;
     RECT  10.116 39.787 17.19 39.991 ;
     RECT  29.415 39.281 29.79 39.991 ;
     RECT  1.152 39.437 9.378 40.013 ;
     RECT  29.415 39.991 29.898 40.027 ;
     RECT  30.636 39.893 31.05 40.027 ;
     RECT  36.648 39.835 37.098 40.055 ;
     RECT  36.756 40.055 37.098 40.061 ;
     RECT  29.415 40.027 31.05 40.063 ;
     RECT  18.36 39.865 20.07 40.099 ;
     RECT  1.656 40.013 9.378 40.135 ;
     RECT  10.116 39.991 17.334 40.135 ;
     RECT  18.324 40.099 20.07 40.135 ;
     RECT  38.736 40.027 38.754 40.163 ;
     RECT  37.08 40.061 37.098 40.261 ;
     RECT  29.304 40.063 31.05 40.289 ;
     RECT  29.304 40.289 30.942 40.325 ;
     RECT  37.08 40.261 37.206 40.325 ;
     RECT  37.188 40.325 37.206 40.349 ;
     RECT  41.616 39.353 42.174 40.361 ;
     RECT  29.412 40.325 30.942 40.397 ;
     RECT  29.415 40.397 30.942 40.433 ;
     RECT  0.072 39.437 0.198 40.493 ;
     RECT  1.656 40.135 20.07 40.603 ;
     RECT  41.58 40.507 41.598 40.699 ;
     RECT  28.008 38.705 28.026 40.801 ;
     RECT  29.415 40.433 30.042 40.829 ;
     RECT  41.544 40.699 41.598 40.865 ;
     RECT  1.656 40.603 20.178 40.877 ;
     RECT  43.128 39.869 43.146 40.891 ;
     RECT  39.312 40.603 39.33 40.901 ;
     RECT  43.092 40.891 43.146 40.987 ;
     RECT  1.692 40.877 20.178 41.009 ;
     RECT  0.108 40.493 0.198 41.035 ;
     RECT  30.78 40.433 30.942 41.107 ;
     RECT  24.015 38.273 27.162 41.135 ;
     RECT  0.108 41.035 0.306 41.165 ;
     RECT  1.692 41.009 19.782 41.171 ;
     RECT  41.544 40.865 41.562 41.171 ;
     RECT  1.692 41.171 19.494 41.213 ;
     RECT  0.108 41.165 0.234 41.215 ;
     RECT  0.036 41.215 0.234 41.243 ;
     RECT  22.824 39.901 22.842 41.243 ;
     RECT  30.78 41.107 31.59 41.243 ;
     RECT  25.02 41.135 27.162 41.341 ;
     RECT  0.036 41.243 0.198 41.369 ;
     RECT  28.008 40.801 28.134 41.371 ;
     RECT  43.056 40.987 43.146 41.405 ;
     RECT  25.02 41.341 27.27 41.413 ;
     RECT  28.008 41.371 28.494 41.413 ;
     RECT  43.056 41.405 43.11 41.453 ;
     RECT  25.02 41.413 28.494 41.467 ;
     RECT  34.815 39.857 35.097 41.512 ;
     RECT  30.78 41.243 30.87 41.513 ;
     RECT  40.215 38.957 40.497 41.515 ;
     RECT  34.704 41.512 35.097 41.549 ;
     RECT  40.104 41.515 40.497 41.555 ;
     RECT  0.108 41.369 0.198 41.741 ;
     RECT  25.02 41.467 28.674 41.783 ;
     RECT  37.008 41.659 37.026 41.945 ;
     RECT  42.156 41.851 42.174 41.947 ;
     RECT  22.716 41.791 22.734 42.017 ;
     RECT  42.12 41.947 42.174 42.043 ;
     RECT  1.728 41.213 19.494 42.061 ;
     RECT  42.084 42.043 42.174 42.139 ;
     RECT  28.116 41.783 28.674 42.151 ;
     RECT  29.415 40.829 29.97 42.151 ;
     RECT  30.708 41.515 30.726 42.151 ;
     RECT  1.728 42.061 19.638 42.179 ;
     RECT  43.092 41.453 43.11 42.235 ;
     RECT  43.092 42.235 43.146 42.331 ;
     RECT  42.048 42.139 42.174 42.359 ;
     RECT  28.116 42.151 30.726 42.457 ;
     RECT  42.048 42.359 42.066 42.485 ;
     RECT  25.02 41.783 27.27 42.523 ;
     RECT  28.116 42.457 31.158 42.523 ;
     RECT  25.02 42.523 31.158 42.593 ;
     RECT  25.02 42.593 30.726 42.749 ;
     RECT  1.728 42.179 19.494 43.097 ;
     RECT  24.015 41.135 24.297 43.099 ;
     RECT  25.02 42.749 29.697 43.099 ;
     RECT  34.74 41.549 35.097 43.231 ;
     RECT  40.215 41.555 40.497 43.231 ;
     RECT  40.104 43.231 40.497 43.277 ;
     RECT  42.192 43.267 42.21 43.325 ;
     RECT  0.108 41.741 0.126 43.411 ;
     RECT  24.015 43.099 29.697 43.601 ;
     RECT  34.704 43.231 35.097 43.805 ;
     RECT  28.476 43.601 29.697 43.867 ;
     RECT  28.476 43.867 29.718 43.907 ;
     RECT  0.036 43.411 0.126 44.069 ;
     RECT  24.015 43.601 27.738 44.249 ;
     RECT  25.02 44.249 27.738 44.375 ;
     RECT  43.056 42.331 43.146 44.375 ;
     RECT  1.728 43.097 17.046 44.419 ;
     RECT  40.215 43.277 40.497 44.539 ;
     RECT  36.468 44.059 36.486 44.587 ;
     RECT  40.215 44.539 40.59 44.609 ;
     RECT  22.824 44.653 22.842 44.725 ;
     RECT  25.056 44.375 27.738 44.725 ;
     RECT  28.476 43.907 29.697 44.725 ;
     RECT  30.708 42.749 30.726 44.731 ;
     RECT  36.468 44.587 37.026 44.789 ;
     RECT  42.156 44.827 42.174 44.851 ;
     RECT  30.708 44.731 30.762 44.875 ;
     RECT  22.824 44.725 22.914 44.951 ;
     RECT  25.056 44.725 29.697 44.995 ;
     RECT  30.42 44.875 30.762 44.995 ;
     RECT  0.108 44.069 0.126 45.067 ;
     RECT  43.092 44.375 43.146 45.115 ;
     RECT  34.815 43.805 35.097 45.157 ;
     RECT  42.084 44.851 42.174 45.157 ;
     RECT  0.108 45.067 0.306 45.197 ;
     RECT  42.084 45.157 42.21 45.211 ;
     RECT  0.108 45.197 0.27 45.256 ;
     RECT  37.548 45.019 37.566 45.259 ;
     RECT  43.056 45.115 43.146 45.259 ;
     RECT  0.036 45.256 0.27 45.293 ;
     RECT  43.02 45.259 43.146 45.329 ;
     RECT  0.072 45.293 0.27 45.389 ;
     RECT  25.056 44.995 30.762 45.391 ;
     RECT  37.548 45.259 38.178 45.419 ;
     RECT  1.692 44.419 17.046 45.499 ;
     RECT  17.964 43.097 19.494 45.499 ;
     RECT  25.056 45.391 31.338 45.563 ;
     RECT  41.904 45.211 42.21 45.629 ;
     RECT  22.788 45.427 22.806 45.697 ;
     RECT  1.692 45.499 19.494 45.797 ;
     RECT  22.752 45.697 22.806 45.805 ;
     RECT  0.108 45.389 0.198 45.821 ;
     RECT  0.18 45.821 0.198 45.869 ;
     RECT  41.904 45.629 42.174 45.931 ;
     RECT  22.752 45.805 22.914 45.967 ;
     RECT  25.056 45.563 31.266 45.995 ;
     RECT  41.616 45.931 42.174 46.013 ;
     RECT  22.716 45.967 22.914 46.031 ;
     RECT  22.716 46.031 22.842 46.067 ;
     RECT  22.752 46.067 22.842 46.103 ;
     RECT  26.784 45.995 31.266 46.103 ;
     RECT  43.056 45.329 43.146 46.171 ;
     RECT  39.312 45.691 39.33 46.229 ;
     RECT  34.74 45.157 35.097 46.237 ;
     RECT  1.692 45.797 17.046 46.253 ;
     RECT  43.02 46.171 43.146 46.267 ;
     RECT  26.784 46.103 30.87 46.301 ;
     RECT  22.824 46.103 22.842 46.373 ;
     RECT  31.824 46.381 32.058 46.471 ;
     RECT  37.548 45.419 37.566 46.471 ;
     RECT  26.784 46.301 27.558 46.499 ;
     RECT  42.984 46.267 43.146 46.555 ;
     RECT  20.376 46.273 20.394 46.579 ;
     RECT  37.548 46.471 37.962 46.589 ;
     RECT  1.728 46.253 17.046 46.603 ;
     RECT  37.548 46.589 37.854 46.637 ;
     RECT  26.784 46.499 27.486 46.643 ;
     RECT  42.912 46.555 43.146 46.643 ;
     RECT  20.376 46.579 20.466 46.651 ;
     RECT  21.96 46.345 21.978 46.651 ;
     RECT  21.888 46.651 21.978 46.679 ;
     RECT  20.34 46.651 20.466 46.741 ;
     RECT  24.015 44.249 24.297 46.741 ;
     RECT  25.884 45.995 25.938 46.741 ;
     RECT  25.056 45.995 25.074 46.805 ;
     RECT  25.884 46.741 26.01 46.805 ;
     RECT  37.548 46.637 37.71 46.805 ;
     RECT  23.58 46.741 24.297 46.813 ;
     RECT  41.904 46.013 42.174 46.843 ;
     RECT  31.824 46.471 32.382 46.849 ;
     RECT  1.728 46.603 17.19 46.885 ;
     RECT  17.964 45.797 19.494 46.885 ;
     RECT  21.888 46.679 21.906 46.921 ;
     RECT  25.92 46.805 26.01 46.921 ;
     RECT  26.784 46.643 27.378 46.921 ;
     RECT  40.215 44.609 40.497 46.939 ;
     RECT  41.58 46.843 42.174 46.939 ;
     RECT  1.728 46.885 19.494 46.949 ;
     RECT  25.164 46.843 25.182 46.949 ;
     RECT  37.692 46.805 37.71 46.949 ;
     RECT  28.548 46.301 30.87 47.011 ;
     RECT  31.824 46.849 32.526 47.011 ;
     RECT  25.92 46.921 27.378 47.075 ;
     RECT  33.48 47.047 33.498 47.147 ;
     RECT  28.548 47.011 32.526 47.155 ;
     RECT  25.92 47.075 26.046 47.183 ;
     RECT  23.256 46.813 24.297 47.191 ;
     RECT  26.784 47.075 27.378 47.213 ;
     RECT  25.92 47.183 26.01 47.309 ;
     RECT  42.948 46.643 43.146 47.345 ;
     RECT  40.215 46.939 42.174 47.381 ;
     RECT  23.076 47.191 24.297 47.389 ;
     RECT  26.784 47.213 26.946 47.417 ;
     RECT  36.468 44.789 36.486 47.453 ;
     RECT  20.34 46.741 20.538 47.461 ;
     RECT  36.54 47.461 36.558 47.551 ;
     RECT  38.736 47.419 38.754 47.563 ;
     RECT  40.215 47.381 41.922 47.563 ;
     RECT  36.54 47.551 36.63 47.579 ;
     RECT  36.612 47.579 36.63 47.651 ;
     RECT  28.512 47.155 32.526 47.659 ;
     RECT  40.104 47.563 41.922 47.693 ;
     RECT  1.728 46.949 19.314 47.695 ;
     RECT  20.052 47.461 20.538 47.695 ;
     RECT  21.528 46.921 21.906 47.695 ;
     RECT  22.788 47.389 24.297 47.695 ;
     RECT  34.704 46.237 35.097 47.723 ;
     RECT  25.92 47.309 25.938 47.759 ;
     RECT  38.7 47.563 38.754 47.759 ;
     RECT  1.728 47.695 20.538 47.821 ;
     RECT  21.528 47.695 24.297 47.821 ;
     RECT  1.728 47.821 24.297 47.885 ;
     RECT  28.512 47.659 33.102 47.957 ;
     RECT  40.215 47.693 41.922 47.993 ;
     RECT  38.16 47.851 38.178 48.029 ;
     RECT  43.02 47.345 43.146 48.091 ;
     RECT  39.204 47.947 39.222 48.187 ;
     RECT  39.204 48.187 39.33 48.221 ;
     RECT  28.512 47.957 32.454 48.227 ;
     RECT  40.215 47.993 41.598 48.389 ;
     RECT  28.656 48.227 32.454 48.461 ;
     RECT  42.876 48.091 43.146 48.461 ;
     RECT  26.784 47.417 26.874 48.505 ;
     RECT  39.276 48.221 39.33 48.569 ;
     RECT  0.108 47.131 0.126 48.653 ;
     RECT  26.784 48.505 26.946 48.695 ;
     RECT  40.215 48.389 41.022 48.695 ;
     RECT  25.704 48.505 25.722 48.739 ;
     RECT  27.684 48.703 27.702 48.739 ;
     RECT  26.82 48.695 26.946 48.811 ;
     RECT  27.684 48.739 27.918 48.811 ;
     RECT  28.656 48.461 32.238 48.839 ;
     RECT  0.18 48.667 0.198 48.845 ;
     RECT  42.192 48.739 42.21 48.893 ;
     RECT  1.728 47.885 19.35 48.901 ;
     RECT  20.196 47.885 24.297 48.901 ;
     RECT  1.728 48.901 24.297 48.929 ;
     RECT  25.632 48.739 25.722 48.955 ;
     RECT  26.82 48.811 27.918 48.965 ;
     RECT  1.728 48.929 12.15 48.973 ;
     RECT  42.984 48.461 43.146 49.001 ;
     RECT  28.656 48.839 30.762 49.009 ;
     RECT  1.152 48.973 12.15 49.037 ;
     RECT  28.224 49.009 30.762 49.037 ;
     RECT  25.632 48.955 25.758 49.051 ;
     RECT  25.524 49.051 25.758 49.351 ;
     RECT  40.215 48.695 40.986 49.435 ;
     RECT  28.224 49.037 30.186 49.469 ;
     RECT  39.312 48.569 39.33 49.483 ;
     RECT  40.215 49.435 41.022 49.483 ;
     RECT  26.82 48.965 27.234 49.531 ;
     RECT  39.312 49.483 41.022 49.541 ;
     RECT  0.108 49.387 0.126 49.565 ;
     RECT  31.68 48.839 32.238 49.613 ;
     RECT  39.312 49.541 40.497 49.649 ;
     RECT  12.96 48.929 24.297 49.709 ;
     RECT  25.488 49.351 25.758 49.711 ;
     RECT  34.815 47.723 35.097 49.711 ;
     RECT  25.488 49.711 25.866 49.723 ;
     RECT  26.712 49.531 27.234 49.723 ;
     RECT  34.704 49.711 35.097 49.757 ;
     RECT  28.368 49.469 30.186 49.775 ;
     RECT  1.728 49.037 12.15 49.783 ;
     RECT  25.488 49.723 27.234 49.783 ;
     RECT  1.728 49.783 12.222 49.855 ;
     RECT  12.96 49.709 20.934 49.855 ;
     RECT  43.02 49.001 43.146 49.867 ;
     RECT  25.488 49.783 27.27 50.011 ;
     RECT  39.312 49.649 39.33 50.045 ;
     RECT  28.656 49.775 30.186 50.287 ;
     RECT  28.656 50.287 30.762 50.387 ;
     RECT  42.156 50.203 42.174 50.431 ;
     RECT  1.728 49.855 20.934 50.443 ;
     RECT  21.888 49.709 24.297 50.443 ;
     RECT  0.288 50.443 0.306 50.491 ;
     RECT  40.215 49.649 40.497 50.491 ;
     RECT  0.216 50.491 0.306 50.539 ;
     RECT  25.452 50.011 27.27 50.549 ;
     RECT  0.144 50.539 0.306 50.573 ;
     RECT  40.215 50.491 41.022 50.593 ;
     RECT  42.156 50.431 42.21 50.593 ;
     RECT  40.215 50.593 42.21 50.621 ;
     RECT  0.144 50.573 0.234 50.629 ;
     RECT  42.984 49.867 43.146 50.629 ;
     RECT  0.036 50.629 0.234 50.657 ;
     RECT  1.728 50.443 24.297 50.657 ;
     RECT  25.452 50.549 26.766 50.657 ;
     RECT  0.036 50.657 0.162 50.669 ;
     RECT  40.215 50.621 41.634 50.717 ;
     RECT  42.984 50.629 43.182 50.779 ;
     RECT  25.452 50.657 25.902 50.855 ;
     RECT  28.656 50.387 30.186 50.855 ;
     RECT  40.215 50.717 41.022 50.875 ;
     RECT  42.912 50.779 43.182 50.909 ;
     RECT  43.02 50.909 43.182 51.161 ;
     RECT  39.888 50.875 41.022 51.197 ;
     RECT  25.596 50.855 25.902 51.233 ;
     RECT  33.588 48.139 33.606 51.233 ;
     RECT  31.68 49.613 31.698 51.241 ;
     RECT  26.748 50.657 26.766 51.331 ;
     RECT  31.68 51.241 32.13 51.331 ;
     RECT  1.728 50.657 21.114 51.397 ;
     RECT  21.888 50.657 24.297 51.397 ;
     RECT  27.936 51.163 27.954 51.403 ;
     RECT  43.056 51.161 43.182 51.431 ;
     RECT  28.764 50.855 30.186 51.503 ;
     RECT  43.056 51.431 43.146 51.503 ;
     RECT  0.144 51.451 0.162 51.592 ;
     RECT  28.764 51.503 29.754 51.643 ;
     RECT  26.748 51.331 26.802 51.665 ;
     RECT  27.72 51.403 27.954 51.691 ;
     RECT  28.692 51.643 29.754 51.691 ;
     RECT  43.056 51.503 43.11 51.725 ;
     RECT  26.784 51.665 26.802 51.781 ;
     RECT  27.72 51.691 29.754 51.781 ;
     RECT  0.036 51.592 0.162 51.883 ;
     RECT  39.924 51.197 41.022 51.965 ;
     RECT  25.632 51.233 25.902 52.007 ;
     RECT  0.036 51.883 0.27 52.013 ;
     RECT  40.215 51.965 41.022 52.123 ;
     RECT  42.156 51.835 42.174 52.123 ;
     RECT  30.78 51.871 30.798 52.177 ;
     RECT  0.036 52.013 0.234 52.205 ;
     RECT  1.728 51.397 24.297 52.205 ;
     RECT  40.215 52.123 42.174 52.205 ;
     RECT  30.78 52.177 30.87 52.213 ;
     RECT  31.608 51.331 32.13 52.213 ;
     RECT  39.312 52.027 39.33 52.241 ;
     RECT  0.216 52.205 0.234 52.253 ;
     RECT  25.884 52.007 25.902 52.301 ;
     RECT  30.78 52.213 32.13 52.313 ;
     RECT  40.215 52.205 41.598 52.475 ;
     RECT  43.092 51.725 43.11 52.507 ;
     RECT  43.092 52.507 43.146 52.603 ;
     RECT  26.784 51.781 29.754 52.681 ;
     RECT  43.056 52.603 43.146 52.781 ;
     RECT  43.092 52.781 43.146 52.817 ;
     RECT  34.815 49.757 35.097 52.843 ;
     RECT  40.215 52.475 41.022 52.843 ;
     RECT  40.104 52.843 41.022 52.853 ;
     RECT  34.704 52.843 35.097 52.889 ;
     RECT  26.244 52.681 29.754 53.015 ;
     RECT  0.108 53.083 0.126 53.131 ;
     RECT  0.036 53.131 0.126 53.168 ;
     RECT  27.288 53.015 29.754 53.227 ;
     RECT  40.104 52.853 40.59 53.249 ;
     RECT  27.288 53.227 29.79 53.357 ;
     RECT  30.78 52.313 30.798 53.357 ;
     RECT  41.58 53.467 41.598 53.555 ;
     RECT  40.104 53.249 40.497 53.557 ;
     RECT  39.924 53.557 40.497 53.597 ;
     RECT  43.092 52.817 43.11 53.659 ;
     RECT  43.056 53.659 43.11 53.755 ;
     RECT  31.608 52.313 32.13 53.789 ;
     RECT  21.888 52.205 24.297 53.797 ;
     RECT  39.312 53.797 39.33 53.803 ;
     RECT  1.728 52.205 20.862 53.833 ;
     RECT  21.672 53.797 24.297 53.833 ;
     RECT  39.204 53.803 39.33 53.837 ;
     RECT  42.984 53.755 43.11 53.851 ;
     RECT  26.244 53.015 26.514 53.869 ;
     RECT  27.288 53.357 29.697 53.869 ;
     RECT  30.708 53.797 30.726 53.933 ;
     RECT  39.204 53.837 39.222 53.933 ;
     RECT  42.984 53.851 43.146 53.933 ;
     RECT  0.144 53.851 0.162 53.995 ;
     RECT  34.815 52.889 35.097 54.043 ;
     RECT  26.244 53.869 29.697 54.091 ;
     RECT  42.156 54.328 42.174 54.365 ;
     RECT  0.144 53.995 0.27 54.427 ;
     RECT  26.136 54.091 29.697 54.427 ;
     RECT  30.744 54.337 30.762 54.437 ;
     RECT  40.215 53.597 40.497 54.565 ;
     RECT  25.776 54.427 29.697 54.571 ;
     RECT  1.728 53.833 24.297 54.599 ;
     RECT  40.104 54.565 40.497 54.605 ;
     RECT  0.108 54.427 0.27 54.643 ;
     RECT  0.072 54.643 0.27 54.671 ;
     RECT  0.072 54.671 0.09 54.701 ;
     RECT  43.056 53.933 43.146 54.859 ;
     RECT  25.092 54.571 29.697 55.021 ;
     RECT  31.608 53.789 31.626 55.049 ;
     RECT  34.704 54.043 35.097 55.049 ;
     RECT  43.02 54.859 43.146 55.112 ;
     RECT  43.056 55.112 43.146 55.139 ;
     RECT  25.02 55.021 29.697 55.175 ;
     RECT  30.672 55.003 30.69 55.181 ;
     RECT  25.2 55.175 29.697 55.229 ;
     RECT  42.192 55.147 42.21 55.229 ;
     RECT  1.728 54.599 11.07 55.381 ;
     RECT  11.844 54.599 24.297 55.381 ;
     RECT  36.396 55.387 36.414 55.435 ;
     RECT  25.308 55.229 29.697 55.445 ;
     RECT  0.252 55.435 0.27 55.531 ;
     RECT  0.144 55.531 0.27 55.565 ;
     RECT  0.144 55.565 0.162 55.709 ;
     RECT  1.728 55.381 24.297 55.715 ;
     RECT  25.344 55.445 29.697 55.715 ;
     RECT  1.728 55.715 23.094 55.859 ;
     RECT  1.728 55.859 22.914 55.949 ;
     RECT  43.056 55.139 43.074 56.045 ;
     RECT  34.815 55.049 35.097 56.191 ;
     RECT  40.215 54.605 40.497 56.191 ;
     RECT  24.015 55.715 24.297 56.203 ;
     RECT  25.344 55.715 28.53 56.203 ;
     RECT  17.856 55.949 22.914 56.219 ;
     RECT  17.856 56.219 22.77 56.228 ;
     RECT  17.892 56.228 22.77 56.237 ;
     RECT  34.704 56.191 35.097 56.237 ;
     RECT  17.892 56.237 22.014 56.363 ;
     RECT  22.752 56.237 22.77 56.363 ;
     RECT  0.108 56.347 0.126 56.371 ;
     RECT  1.728 55.949 17.046 56.381 ;
     RECT  0.036 56.371 0.126 56.399 ;
     RECT  0.036 56.399 0.054 56.429 ;
     RECT  1.728 56.381 17.01 56.525 ;
     RECT  17.928 56.363 20.07 56.525 ;
     RECT  21.06 56.363 22.014 56.525 ;
     RECT  40.104 56.191 40.497 56.539 ;
     RECT  42.156 56.443 42.174 56.561 ;
     RECT  21.06 56.525 21.762 56.597 ;
     RECT  18.18 56.525 19.566 56.633 ;
     RECT  39.6 56.539 40.497 56.641 ;
     RECT  18.18 56.633 19.062 56.669 ;
     RECT  1.728 56.525 16.578 56.939 ;
     RECT  39.6 56.641 40.842 57.029 ;
     RECT  24.015 56.203 28.53 57.173 ;
     RECT  1.728 56.939 16.47 57.443 ;
     RECT  22.824 57.343 22.842 57.443 ;
     RECT  36.396 55.435 36.486 57.749 ;
     RECT  18.18 56.669 18.897 58.019 ;
     RECT  36.396 57.749 36.414 58.109 ;
     RECT  0.252 58.123 0.27 58.171 ;
     RECT  0.252 58.171 0.342 58.189 ;
     RECT  0.036 58.189 0.342 58.217 ;
     RECT  1.728 57.443 16.326 58.253 ;
     RECT  21.096 56.597 21.654 58.289 ;
     RECT  0.036 58.217 0.306 58.445 ;
     RECT  27.612 57.173 28.53 58.451 ;
     RECT  18.615 58.019 18.897 58.459 ;
     RECT  0.036 58.445 0.234 58.604 ;
     RECT  0.036 58.604 0.162 58.685 ;
     RECT  1.728 58.253 15.966 58.757 ;
     RECT  24.015 57.173 26.802 58.765 ;
     RECT  24.015 58.765 26.838 58.955 ;
     RECT  1.728 58.757 15.93 59.027 ;
     RECT  21.096 58.289 21.114 59.099 ;
     RECT  0.036 58.685 0.126 59.117 ;
     RECT  26.712 58.955 26.838 59.189 ;
     RECT  24.015 58.955 25.902 59.225 ;
     RECT  26.712 59.189 26.802 59.225 ;
     RECT  25.884 59.225 25.902 59.495 ;
     RECT  26.784 59.225 26.802 59.603 ;
     RECT  18.615 58.459 19.422 59.639 ;
     RECT  22.824 59.503 22.842 59.639 ;
     RECT  1.728 59.027 15.786 59.881 ;
     RECT  0.108 59.117 0.126 59.947 ;
     RECT  24.015 59.225 25.11 59.971 ;
     RECT  24.015 59.971 25.218 60.077 ;
     RECT  1.728 59.881 16.038 60.079 ;
     RECT  1.728 60.079 16.074 60.115 ;
     RECT  27.612 58.451 28.386 60.143 ;
     RECT  0.036 59.947 0.126 60.269 ;
     RECT  0.108 60.269 0.126 60.317 ;
     RECT  1.728 60.115 16.506 60.611 ;
     RECT  1.728 60.611 15.894 60.683 ;
     RECT  27.612 60.143 28.206 60.683 ;
     RECT  24.015 60.077 24.894 60.881 ;
     RECT  1.728 60.683 15.102 60.893 ;
     RECT  15.876 60.683 15.894 60.917 ;
     RECT  1.728 60.893 14.994 61.079 ;
     RECT  1.728 61.079 14.85 61.115 ;
     RECT  1.728 61.115 14.778 61.259 ;
     RECT  0.144 61.147 0.162 61.291 ;
     RECT  0.144 61.291 0.306 61.421 ;
     RECT  1.728 61.259 14.274 61.493 ;
     RECT  1.764 61.493 14.274 61.619 ;
     RECT  0.144 61.421 0.27 61.709 ;
     RECT  0.144 61.709 0.162 61.771 ;
     RECT  0.108 61.771 0.162 61.949 ;
     RECT  12.564 61.619 14.274 61.997 ;
     RECT  0.108 61.949 0.126 62.045 ;
     RECT  12.564 61.997 14.022 62.231 ;
     RECT  1.764 61.619 11.79 62.251 ;
     RECT  12.744 62.231 14.022 62.303 ;
     RECT  1.728 62.251 11.79 62.339 ;
     RECT  1.728 62.339 10.89 62.573 ;
     RECT  0.036 62.731 0.054 63.019 ;
     RECT  11.664 62.339 11.79 63.113 ;
     RECT  0.036 63.019 0.09 63.259 ;
     RECT  0.036 63.259 0.198 63.307 ;
     RECT  0.036 63.307 0.342 63.533 ;
     RECT  0.036 63.533 0.27 64.013 ;
     RECT  0.036 64.013 0.162 64.157 ;
     RECT  11.664 63.113 11.682 64.463 ;
     RECT  0.036 64.157 0.126 64.589 ;
     RECT  28.188 60.683 28.206 64.697 ;
     RECT  0.108 64.589 0.126 64.925 ;
     RECT  39.6 57.029 40.497 64.931 ;
     RECT  1.728 62.573 10.386 65.201 ;
     RECT  39.348 65.011 39.366 65.399 ;
     RECT  10.368 65.201 10.386 65.443 ;
     RECT  10.368 65.443 10.818 65.543 ;
     RECT  13.215 62.303 14.022 65.849 ;
     RECT  24.015 60.881 24.297 66.181 ;
     RECT  10.368 65.543 10.386 66.245 ;
     RECT  23.94 66.181 24.297 66.793 ;
     RECT  1.728 65.201 9.162 67.019 ;
     RECT  0.036 65.803 0.054 67.051 ;
     RECT  5.76 67.019 9.162 67.163 ;
     RECT  0.036 67.051 0.09 67.289 ;
     RECT  0.072 67.289 0.09 67.339 ;
     RECT  0.864 65.899 0.882 67.339 ;
     RECT  5.76 67.163 8.097 67.361 ;
     RECT  9.144 67.163 9.162 67.559 ;
     RECT  23.94 66.793 24.894 67.559 ;
     RECT  23.94 67.559 24.297 67.595 ;
     RECT  6.156 67.361 8.097 67.631 ;
     RECT  42.156 68.251 42.174 68.369 ;
     RECT  40.215 64.931 40.497 68.485 ;
     RECT  38.772 67.531 38.79 68.521 ;
     RECT  40.215 68.485 40.734 68.521 ;
     RECT  0.072 67.339 0.882 68.639 ;
     RECT  38.772 68.521 40.734 68.639 ;
     RECT  6.192 67.631 8.097 68.711 ;
     RECT  40.14 68.639 40.497 68.711 ;
     RECT  37.872 68.683 37.89 68.72 ;
     RECT  38.772 68.639 38.79 68.747 ;
     RECT  0.576 68.639 0.882 68.909 ;
     RECT  1.728 67.019 4.986 68.909 ;
     RECT  38.664 68.755 38.682 68.909 ;
     RECT  1.728 68.909 4.59 69.251 ;
     RECT  6.552 68.711 8.097 69.521 ;
     RECT  6.804 69.521 8.097 69.719 ;
     RECT  6.804 69.719 6.822 69.791 ;
     RECT  1.728 69.251 4.302 70.097 ;
     RECT  0.576 68.909 0.594 70.439 ;
     RECT  1.728 70.097 2.862 70.565 ;
     RECT  3.924 70.097 4.302 70.673 ;
     RECT  3.924 70.673 3.942 70.871 ;
     RECT  20.7 68.611 20.718 71.069 ;
     RECT  2.34 70.565 2.862 71.077 ;
     RECT  2.34 71.077 2.934 72.959 ;
     RECT  2.34 72.959 2.79 73.031 ;
     RECT  2.34 73.031 2.697 73.075 ;
     RECT  1.728 73.075 2.697 73.469 ;
     RECT  2.304 73.469 2.697 73.565 ;
     RECT  2.34 73.565 2.697 78.601 ;
     RECT  1.728 78.601 2.862 78.653 ;
     RECT  2.34 78.653 2.862 78.899 ;
     RECT  2.415 78.899 2.697 83.987 ;
     RECT  7.815 69.719 8.097 83.987 ;
     RECT  13.215 65.849 13.497 83.987 ;
     RECT  18.615 59.639 18.897 83.987 ;
     RECT  24.015 67.595 24.297 83.987 ;
     RECT  29.415 55.715 29.697 83.987 ;
     RECT  34.815 56.237 35.097 83.987 ;
     RECT  40.215 68.711 40.497 83.987 ;
     RECT  2.415 83.987 2.505 84.257 ;
     RECT  7.815 83.987 7.905 84.257 ;
     RECT  13.215 83.987 13.305 84.257 ;
     RECT  18.615 83.987 18.705 84.257 ;
     RECT  24.015 83.987 24.105 84.257 ;
     RECT  29.415 83.987 29.505 84.257 ;
     RECT  34.815 83.987 34.905 84.257 ;
     RECT  40.215 83.987 40.305 84.257 ;
    LAYER M4 ;
     RECT  0.012 34.992 0.605 67.368 ;
     RECT  0.605 34.992 1.753 67.272 ;
     RECT  1.753 34.944 2.293 67.272 ;
     RECT  2.293 34.896 2.408 67.272 ;
     RECT  0.012 73.44 2.408 73.56 ;
     RECT  2.408 2.148 2.512 84.252 ;
     RECT  2.512 2.418 2.704 83.982 ;
     RECT  2.704 36.336 2.837 66.792 ;
     RECT  2.837 36.336 3.305 66.504 ;
     RECT  2.704 34.464 3.665 35.064 ;
     RECT  3.305 36.336 3.701 60.36 ;
     RECT  3.665 34.656 3.733 35.064 ;
     RECT  3.733 34.656 3.737 35.256 ;
     RECT  3.737 35.232 3.845 35.256 ;
     RECT  3.701 36.624 3.845 60.36 ;
     RECT  3.305 61.344 4.241 66.504 ;
     RECT  3.845 36.768 4.273 60.36 ;
     RECT  4.241 61.344 4.273 64.92 ;
     RECT  4.241 66.192 4.493 66.504 ;
     RECT  4.493 66.48 4.633 66.504 ;
     RECT  4.633 66.48 4.817 66.696 ;
     RECT  4.817 66.48 4.997 66.504 ;
     RECT  4.273 36.768 5.177 64.92 ;
     RECT  5.177 37.584 5.213 64.92 ;
     RECT  5.213 37.584 5.285 61.656 ;
     RECT  5.285 37.584 5.465 60.936 ;
     RECT  5.213 62.64 5.681 64.92 ;
     RECT  5.681 62.64 5.717 64.152 ;
     RECT  5.717 62.64 6.253 63.768 ;
     RECT  6.253 62.592 6.293 63.768 ;
     RECT  5.641 66.096 6.293 66.12 ;
     RECT  5.317 36.336 6.361 36.36 ;
     RECT  5.465 37.584 6.361 38.136 ;
     RECT  6.293 62.592 6.361 63.528 ;
     RECT  6.361 62.496 6.365 63.528 ;
     RECT  6.361 36.336 6.865 38.136 ;
     RECT  5.465 39.12 6.865 60.936 ;
     RECT  6.865 36.336 7.369 60.936 ;
     RECT  6.365 62.496 7.369 63.048 ;
     RECT  6.253 35.28 7.372 35.304 ;
     RECT  7.261 33.312 7.808 33.336 ;
     RECT  7.372 35.232 7.808 35.304 ;
     RECT  7.369 36.336 7.808 63.048 ;
     RECT  7.808 2.148 7.912 84.252 ;
     RECT  7.912 2.418 8.104 83.982 ;
     RECT  8.104 62.976 8.273 63.144 ;
     RECT  8.104 33.312 8.525 60.648 ;
     RECT  8.525 57.024 8.669 60.648 ;
     RECT  8.525 33.312 9.107 55.992 ;
     RECT  8.669 57.36 9.133 60.648 ;
     RECT  9.107 35.232 9.173 55.992 ;
     RECT  9.173 37.968 9.196 55.992 ;
     RECT  9.196 37.968 9.209 38.76 ;
     RECT  9.196 40.08 9.281 55.992 ;
     RECT  8.273 62.976 9.341 63.096 ;
     RECT  9.281 44.16 9.425 55.992 ;
     RECT  9.341 62.976 9.425 63.288 ;
     RECT  9.107 33.312 9.457 34.104 ;
     RECT  9.425 62.976 9.457 63.048 ;
     RECT  9.133 57.36 9.644 60.696 ;
     RECT  8.104 61.728 9.644 61.752 ;
     RECT  9.644 57.36 9.731 61.752 ;
     RECT  9.457 62.784 9.785 63.048 ;
     RECT  9.173 35.232 9.821 36.936 ;
     RECT  9.731 57.36 9.821 60.648 ;
     RECT  9.785 62.976 9.893 63.048 ;
     RECT  9.821 35.232 10.145 36.072 ;
     RECT  9.209 37.968 10.217 38.664 ;
     RECT  9.457 33.12 10.321 34.104 ;
     RECT  9.731 61.728 10.325 61.752 ;
     RECT  10.321 33.12 10.393 34.2 ;
     RECT  10.145 35.232 10.393 35.64 ;
     RECT  9.425 44.496 10.429 55.992 ;
     RECT  9.821 57.36 10.429 57.96 ;
     RECT  9.281 40.08 10.501 42.936 ;
     RECT  10.429 44.496 10.573 57.96 ;
     RECT  10.393 33.12 10.748 35.64 ;
     RECT  10.217 38.64 10.825 38.664 ;
     RECT  10.501 40.08 10.825 43.176 ;
     RECT  10.825 38.64 10.829 43.176 ;
     RECT  10.748 33.072 10.835 35.64 ;
     RECT  9.893 63.024 10.835 63.048 ;
     RECT  10.835 33.12 10.893 35.64 ;
     RECT  10.573 44.208 11.009 57.96 ;
     RECT  10.829 38.784 11.045 43.176 ;
     RECT  11.045 39.36 11.113 43.176 ;
     RECT  11.009 44.208 11.113 55.896 ;
     RECT  11.009 56.88 11.293 57.96 ;
     RECT  9.821 58.944 11.293 60.648 ;
     RECT  10.357 37.056 11.441 37.08 ;
     RECT  11.293 56.88 11.545 60.648 ;
     RECT  10.789 61.776 11.545 61.8 ;
     RECT  11.401 30.336 11.585 30.36 ;
     RECT  10.893 33.12 11.585 35.256 ;
     RECT  11.545 56.88 11.585 61.8 ;
     RECT  11.113 39.36 12.009 55.896 ;
     RECT  12.009 39.36 12.265 55.8 ;
     RECT  11.585 56.88 12.481 61.608 ;
     RECT  12.265 38.688 13.021 55.8 ;
     RECT  12.481 56.784 13.021 61.608 ;
     RECT  11.585 33.312 13.208 35.256 ;
     RECT  13.021 38.688 13.208 61.608 ;
     RECT  13.208 2.148 13.312 84.252 ;
     RECT  13.312 2.418 13.504 83.982 ;
     RECT  13.504 39.552 13.637 60.888 ;
     RECT  13.637 39.888 13.745 60.888 ;
     RECT  13.745 39.888 13.817 48.216 ;
     RECT  13.745 49.344 13.817 60.888 ;
     RECT  13.817 39.888 14.357 43.416 ;
     RECT  13.817 49.584 14.573 60.888 ;
     RECT  14.357 39.888 14.821 42.84 ;
     RECT  13.817 44.736 14.893 48.216 ;
     RECT  14.893 44.448 15.001 48.216 ;
     RECT  14.573 59.616 15.113 60.888 ;
     RECT  15.113 59.616 15.221 60.072 ;
     RECT  14.821 39.648 15.325 42.84 ;
     RECT  15.325 39.312 15.361 42.84 ;
     RECT  14.573 49.584 15.539 58.152 ;
     RECT  15.539 49.584 15.58 57.816 ;
     RECT  15.58 57.792 15.587 57.816 ;
     RECT  15.361 39.312 15.617 43.368 ;
     RECT  15.001 44.448 15.977 48.408 ;
     RECT  15.977 44.448 16.049 46.872 ;
     RECT  15.617 39.312 16.301 42.984 ;
     RECT  15.58 49.584 16.405 56.52 ;
     RECT  16.301 39.792 16.445 42.984 ;
     RECT  15.977 47.856 16.549 48.408 ;
     RECT  16.405 49.488 16.549 56.52 ;
     RECT  16.049 44.448 16.585 45.576 ;
     RECT  16.445 41.184 16.739 42.984 ;
     RECT  16.049 46.608 16.94 46.872 ;
     RECT  16.549 47.856 16.94 56.52 ;
     RECT  16.585 44.4 16.949 45.576 ;
     RECT  16.445 39.792 17.201 40.104 ;
     RECT  16.94 46.608 17.201 56.52 ;
     RECT  17.125 38.784 17.209 38.808 ;
     RECT  16.739 41.184 17.273 42.84 ;
     RECT  17.273 41.184 17.417 42.792 ;
     RECT  17.201 40.08 17.449 40.104 ;
     RECT  17.417 41.184 17.449 42.168 ;
     RECT  17.201 46.848 17.597 56.52 ;
     RECT  17.125 26.64 18.608 26.664 ;
     RECT  13.504 33.312 18.608 33.336 ;
     RECT  13.504 35.232 18.608 35.256 ;
     RECT  17.449 40.08 18.608 42.168 ;
     RECT  16.949 45.552 18.608 45.576 ;
     RECT  17.597 46.848 18.608 48.408 ;
     RECT  17.597 49.488 18.608 56.52 ;
     RECT  15.221 60.048 18.608 60.072 ;
     RECT  18.608 2.148 18.712 84.252 ;
     RECT  18.712 2.418 18.904 83.982 ;
     RECT  18.904 39.408 19.001 41.976 ;
     RECT  18.904 46.752 19.145 47.928 ;
     RECT  19.001 39.408 19.721 40.104 ;
     RECT  18.904 49.008 20.081 56.52 ;
     RECT  19.145 46.848 20.153 47.928 ;
     RECT  20.153 47.904 20.225 47.928 ;
     RECT  20.081 49.008 20.585 56.232 ;
     RECT  20.585 49.488 20.765 56.232 ;
     RECT  20.765 49.584 21.155 56.232 ;
     RECT  21.155 49.584 21.305 53.256 ;
     RECT  21.155 54.912 22.345 56.232 ;
     RECT  22.345 54.576 22.565 56.232 ;
     RECT  21.305 52.272 22.853 53.256 ;
     RECT  22.565 54.576 22.889 55.848 ;
     RECT  22.889 54.768 22.997 55.848 ;
     RECT  22.849 31.728 23.033 31.752 ;
     RECT  20.153 46.848 23.245 46.872 ;
     RECT  18.904 26.64 24.008 26.664 ;
     RECT  18.904 33.312 24.008 33.336 ;
     RECT  18.904 35.232 24.008 35.256 ;
     RECT  19.721 40.08 24.008 40.104 ;
     RECT  19.001 41.184 24.008 41.976 ;
     RECT  23.245 46.848 24.008 47.112 ;
     RECT  21.305 49.584 24.008 50.616 ;
     RECT  22.853 52.272 24.008 53.064 ;
     RECT  22.997 54.768 24.008 55.8 ;
     RECT  18.904 60.048 24.008 60.072 ;
     RECT  20.293 68.688 24.008 68.712 ;
     RECT  24.008 2.148 24.112 84.252 ;
     RECT  24.112 2.418 24.304 83.982 ;
     RECT  24.304 33.312 25.193 35.256 ;
     RECT  24.304 46.848 25.193 46.872 ;
     RECT  24.304 60.048 25.229 60.072 ;
     RECT  24.304 36.864 25.333 36.936 ;
     RECT  25.193 33.312 25.409 34.44 ;
     RECT  24.304 41.184 25.409 43.272 ;
     RECT  24.304 30.144 25.513 31.752 ;
     RECT  24.304 49.584 25.513 50.616 ;
     RECT  25.333 36.864 25.621 37.464 ;
     RECT  25.409 41.952 25.657 43.272 ;
     RECT  25.621 36.816 25.729 37.464 ;
     RECT  25.513 49.056 25.729 50.616 ;
     RECT  24.304 54.576 25.765 56.376 ;
     RECT  24.304 40.08 25.841 40.104 ;
     RECT  24.304 52.272 25.913 53.064 ;
     RECT  25.729 36.768 25.945 37.464 ;
     RECT  25.945 36.528 25.981 37.464 ;
     RECT  25.765 54.432 26.125 56.376 ;
     RECT  25.409 33.312 26.161 34.104 ;
     RECT  25.513 30.144 26.197 31.992 ;
     RECT  26.125 54.096 26.305 56.376 ;
     RECT  26.197 30.048 26.377 31.992 ;
     RECT  25.913 53.04 26.485 53.064 ;
     RECT  26.305 54.048 26.485 56.376 ;
     RECT  26.377 29.856 26.593 31.992 ;
     RECT  26.161 33.024 26.593 34.104 ;
     RECT  26.593 29.856 26.737 34.104 ;
     RECT  25.729 48.96 26.737 50.616 ;
     RECT  25.981 36.528 26.917 37.608 ;
     RECT  26.737 29.856 26.957 34.632 ;
     RECT  26.917 35.712 27.025 37.608 ;
     RECT  25.657 41.952 27.025 43.896 ;
     RECT  27.025 35.232 27.133 37.608 ;
     RECT  26.485 53.04 27.277 56.376 ;
     RECT  27.025 41.952 27.281 44.664 ;
     RECT  26.773 47.184 27.389 47.208 ;
     RECT  26.737 48.96 27.925 51.096 ;
     RECT  27.277 52.8 28.033 56.376 ;
     RECT  26.957 29.856 28.429 34.104 ;
     RECT  27.133 35.232 28.429 37.656 ;
     RECT  27.281 42.288 28.465 44.664 ;
     RECT  27.925 48.96 28.465 51.192 ;
     RECT  28.465 48.96 28.573 51.72 ;
     RECT  28.033 52.704 28.573 56.376 ;
     RECT  28.573 48.96 28.645 56.376 ;
     RECT  24.304 26.64 29.408 26.664 ;
     RECT  28.429 29.856 29.408 37.656 ;
     RECT  25.981 38.736 29.408 38.76 ;
     RECT  28.465 41.376 29.408 44.664 ;
     RECT  28.645 48.192 29.408 56.376 ;
     RECT  24.304 68.688 29.408 68.712 ;
     RECT  29.408 2.148 29.512 84.252 ;
     RECT  29.512 2.418 29.704 83.982 ;
     RECT  29.704 26.64 30.277 26.808 ;
     RECT  30.277 26.64 30.377 26.664 ;
     RECT  29.704 40.032 30.913 40.056 ;
     RECT  31.021 45.936 31.277 45.96 ;
     RECT  29.704 48.192 31.741 56.376 ;
     RECT  31.813 46.608 31.861 46.632 ;
     RECT  31.861 46.608 32.317 46.776 ;
     RECT  31.741 47.856 32.897 56.376 ;
     RECT  32.317 46.56 34.765 46.776 ;
     RECT  29.704 14.4 34.808 14.424 ;
     RECT  29.704 29.856 34.808 39 ;
     RECT  30.913 40.032 34.808 40.344 ;
     RECT  29.704 41.376 34.808 44.904 ;
     RECT  34.765 46.56 34.808 46.872 ;
     RECT  32.897 48.144 34.808 56.376 ;
     RECT  29.704 68.688 34.808 68.712 ;
     RECT  34.808 2.148 34.912 84.252 ;
     RECT  34.912 2.418 35.104 83.982 ;
     RECT  35.104 29.856 36.637 39 ;
     RECT  35.104 40.032 36.637 40.344 ;
     RECT  36.637 29.856 37.217 40.344 ;
     RECT  35.104 41.376 37.537 44.904 ;
     RECT  35.104 46.56 37.573 46.872 ;
     RECT  37.573 46.512 37.721 46.872 ;
     RECT  35.104 68.688 37.901 68.712 ;
     RECT  37.537 41.376 38.149 45.048 ;
     RECT  35.104 48 38.149 56.376 ;
     RECT  37.721 46.512 38.689 46.632 ;
     RECT  38.149 47.856 38.689 56.376 ;
     RECT  37.217 29.856 38.725 39.864 ;
     RECT  38.725 29.856 39.301 40.056 ;
     RECT  38.149 41.376 39.301 45.288 ;
     RECT  38.689 46.512 39.301 56.376 ;
     RECT  39.301 29.856 39.589 56.376 ;
     RECT  35.104 14.4 40.208 14.424 ;
     RECT  39.589 29.856 40.208 56.568 ;
     RECT  40.208 2.148 40.312 84.252 ;
     RECT  40.312 2.418 40.504 83.982 ;
     RECT  40.504 29.856 43.2 56.568 ;
    LAYER M5 ;
     RECT  2.4 2.137 2.52 2.151 ;
     RECT  13.2 2.137 13.32 2.151 ;
     RECT  18.6 2.137 18.72 2.151 ;
     RECT  24 2.137 24.12 2.151 ;
     RECT  29.4 2.137 29.52 2.151 ;
     RECT  34.8 2.137 34.92 2.151 ;
     RECT  40.2 2.137 40.32 2.151 ;
     RECT  29.4 2.151 29.712 14.389 ;
     RECT  29.4 14.389 30.264 26.819 ;
     RECT  26.784 31.429 26.808 31.763 ;
     RECT  30.768 31.429 30.792 31.763 ;
     RECT  7.8 2.137 8.664 34.069 ;
     RECT  9.696 33.349 9.72 34.069 ;
     RECT  7.8 34.069 9.72 34.115 ;
     RECT  7.8 34.115 9.096 34.835 ;
     RECT  7.8 34.835 8.664 35.221 ;
     RECT  7.392 35.221 8.664 36.949 ;
     RECT  9.648 35.845 9.672 36.949 ;
     RECT  10.848 35.029 10.872 37.091 ;
     RECT  7.392 36.949 9.672 37.667 ;
     RECT  17.136 26.629 17.16 38.819 ;
     RECT  7.392 37.667 8.664 39.109 ;
     RECT  6.864 39.109 8.664 39.301 ;
     RECT  9.648 37.667 9.672 39.301 ;
     RECT  10.848 38.773 10.872 39.395 ;
     RECT  6.864 39.301 9.672 40.355 ;
     RECT  13.2 2.151 13.512 41.413 ;
     RECT  6.864 40.355 8.664 41.651 ;
     RECT  9.648 40.355 9.672 41.651 ;
     RECT  9.84 41.893 9.864 42.467 ;
     RECT  11.952 40.549 11.976 42.565 ;
     RECT  13.2 41.413 13.704 42.755 ;
     RECT  16.704 42.133 16.728 42.995 ;
     RECT  11.424 42.565 11.976 43.477 ;
     RECT  7.296 41.651 8.664 43.763 ;
     RECT  11.328 43.477 11.976 43.909 ;
     RECT  13.2 42.755 13.656 43.909 ;
     RECT  11.328 43.909 13.656 45.155 ;
     RECT  7.392 43.763 8.664 45.397 ;
     RECT  11.328 45.155 11.976 45.443 ;
     RECT  18.6 2.151 18.912 45.541 ;
     RECT  7.296 45.397 8.664 45.587 ;
     RECT  13.2 45.155 13.656 45.877 ;
     RECT  11.328 45.443 11.88 45.971 ;
     RECT  7.8 45.587 8.664 46.261 ;
     RECT  7.8 46.261 8.952 46.837 ;
     RECT  7.8 46.837 9.048 47.075 ;
     RECT  13.2 45.877 13.8 47.317 ;
     RECT  11.856 45.971 11.88 47.363 ;
     RECT  13.2 47.317 14.232 47.891 ;
     RECT  31.872 46.741 31.896 47.939 ;
     RECT  10.224 47.269 10.248 48.419 ;
     RECT  15.888 47.317 15.912 48.419 ;
     RECT  18.048 45.541 18.912 48.419 ;
     RECT  16.992 47.461 17.016 48.467 ;
     RECT  7.8 47.075 8.664 49.043 ;
     RECT  7.8 49.043 8.112 50.101 ;
     RECT  7.536 50.101 8.112 50.869 ;
     RECT  6.864 50.869 8.112 51.155 ;
     RECT  15.6 50.005 15.624 51.205 ;
     RECT  16.992 50.773 17.016 51.347 ;
     RECT  7.8 51.155 8.112 52.213 ;
     RECT  20.304 49.525 20.328 52.405 ;
     RECT  7.8 52.213 8.664 52.787 ;
     RECT  14.736 51.205 15.624 53.507 ;
     RECT  18.6 48.419 18.912 53.557 ;
     RECT  6.624 54.469 6.648 54.565 ;
     RECT  6.624 54.565 6.696 54.805 ;
     RECT  6.624 54.805 6.744 54.851 ;
     RECT  22.512 54.901 22.776 55.091 ;
     RECT  15.6 53.507 15.624 55.139 ;
     RECT  20.304 52.405 21.144 55.139 ;
     RECT  22.512 55.091 22.536 55.235 ;
     RECT  18.192 53.557 18.912 55.237 ;
     RECT  30.768 55.141 30.792 55.283 ;
     RECT  10.944 53.221 10.968 55.379 ;
     RECT  9.408 55.765 9.432 55.861 ;
     RECT  13.2 47.891 13.656 55.861 ;
     RECT  15.552 55.237 15.576 55.861 ;
     RECT  9.408 55.861 9.528 55.907 ;
     RECT  6.72 54.851 6.744 56.005 ;
     RECT  7.8 52.787 8.112 56.005 ;
     RECT  6.72 56.005 8.112 56.341 ;
     RECT  17.856 55.237 18.912 56.387 ;
     RECT  6.72 56.341 8.232 56.531 ;
     RECT  13.2 55.861 15.576 56.869 ;
     RECT  7.536 56.531 8.232 57.059 ;
     RECT  13.104 56.869 15.576 57.059 ;
     RECT  7.536 57.059 8.112 57.155 ;
     RECT  13.104 57.059 13.656 57.731 ;
     RECT  15.504 57.059 15.576 57.827 ;
     RECT  11.952 55.861 11.976 58.115 ;
     RECT  9.504 55.907 9.528 58.117 ;
     RECT  15.504 57.827 15.528 58.163 ;
     RECT  6.624 58.117 6.648 58.451 ;
     RECT  9.408 58.117 9.528 58.645 ;
     RECT  9.36 58.645 9.528 58.691 ;
     RECT  6.768 58.693 6.792 58.835 ;
     RECT  13.104 57.731 13.512 59.219 ;
     RECT  9.36 58.691 9.432 59.701 ;
     RECT  7.8 57.155 8.112 60.037 ;
     RECT  13.2 59.219 13.512 60.373 ;
     RECT  12.576 60.373 13.512 61.619 ;
     RECT  7.392 60.037 8.112 61.717 ;
     RECT  9.36 59.701 9.72 61.717 ;
     RECT  7.392 61.717 9.72 61.763 ;
     RECT  7.392 61.763 9.384 62.771 ;
     RECT  10.8 61.765 10.824 63.059 ;
     RECT  7.8 62.771 9.384 63.107 ;
     RECT  9.36 63.107 9.384 63.299 ;
     RECT  20.304 55.139 20.328 68.723 ;
     RECT  2.4 2.151 2.712 84.249 ;
     RECT  7.8 63.107 8.112 84.249 ;
     RECT  13.2 61.619 13.512 84.249 ;
     RECT  18.6 56.387 18.912 84.249 ;
     RECT  24 2.151 24.312 84.249 ;
     RECT  29.4 26.819 29.712 84.249 ;
     RECT  34.8 2.151 35.112 84.249 ;
     RECT  40.2 2.151 40.512 84.249 ;
     RECT  2.4 84.249 2.52 84.263 ;
     RECT  7.8 84.249 7.92 84.263 ;
     RECT  13.2 84.249 13.32 84.263 ;
     RECT  18.6 84.249 18.72 84.263 ;
     RECT  24 84.249 24.12 84.263 ;
     RECT  29.4 84.249 29.52 84.263 ;
     RECT  34.8 84.249 34.92 84.263 ;
     RECT  40.2 84.249 40.32 84.263 ;
     RECT  17.16 26.629 18.6 38.819 ;
     RECT  29.712 31.429 30.768 31.763 ;
     RECT  8.664 33.349 9.696 34.069 ;
     RECT  8.664 34.835 9.096 35.845 ;
     RECT  8.664 35.845 9.648 36.949 ;
     RECT  9.672 35.845 10.848 37.091 ;
     RECT  8.664 37.667 9.648 39.301 ;
     RECT  9.672 38.773 10.848 39.395 ;
     RECT  8.664 40.355 9.648 41.651 ;
     RECT  11.976 40.549 13.2 43.909 ;
     RECT  8.664 41.651 9.672 41.893 ;
     RECT  8.664 41.893 9.84 42.467 ;
     RECT  11.976 45.155 13.2 45.443 ;
     RECT  11.88 45.443 13.2 47.363 ;
     RECT  15.912 47.461 16.992 48.419 ;
     RECT  17.016 47.461 18.048 48.419 ;
     RECT  18.912 49.525 20.304 68.723 ;
     RECT  15.624 50.773 16.992 51.347 ;
     RECT  13.656 51.205 14.736 53.507 ;
     RECT  6.648 54.469 7.8 54.565 ;
     RECT  6.696 54.565 7.8 54.805 ;
     RECT  6.744 54.805 7.8 56.005 ;
     RECT  21.144 54.901 22.512 55.139 ;
     RECT  22.776 54.901 24 55.091 ;
     RECT  22.536 55.091 24 55.235 ;
     RECT  29.712 55.141 30.768 55.283 ;
     RECT  8.112 55.765 9.408 55.907 ;
     RECT  11.976 55.861 13.2 56.869 ;
     RECT  8.112 55.907 9.504 56.341 ;
     RECT  8.232 56.341 9.504 57.059 ;
     RECT  11.976 56.869 13.104 58.115 ;
     RECT  8.112 57.059 9.504 58.117 ;
     RECT  7.536 57.155 7.8 58.117 ;
     RECT  6.648 58.117 7.8 58.451 ;
     RECT  8.112 58.117 9.408 58.645 ;
     RECT  6.768 58.451 7.8 58.693 ;
     RECT  8.112 58.645 9.36 61.717 ;
     RECT  9.432 58.691 9.528 59.701 ;
     RECT  6.792 58.693 7.8 58.835 ;
     RECT  7.392 58.835 7.8 60.037 ;
     RECT  13.104 59.219 13.2 60.373 ;
     RECT  9.384 61.763 9.72 61.765 ;
     RECT  9.384 61.765 10.8 63.059 ;
     RECT  8.112 63.107 9.36 63.299 ;
  END
END ot_hgi_sm_pub_vmport
END LIBRARY
